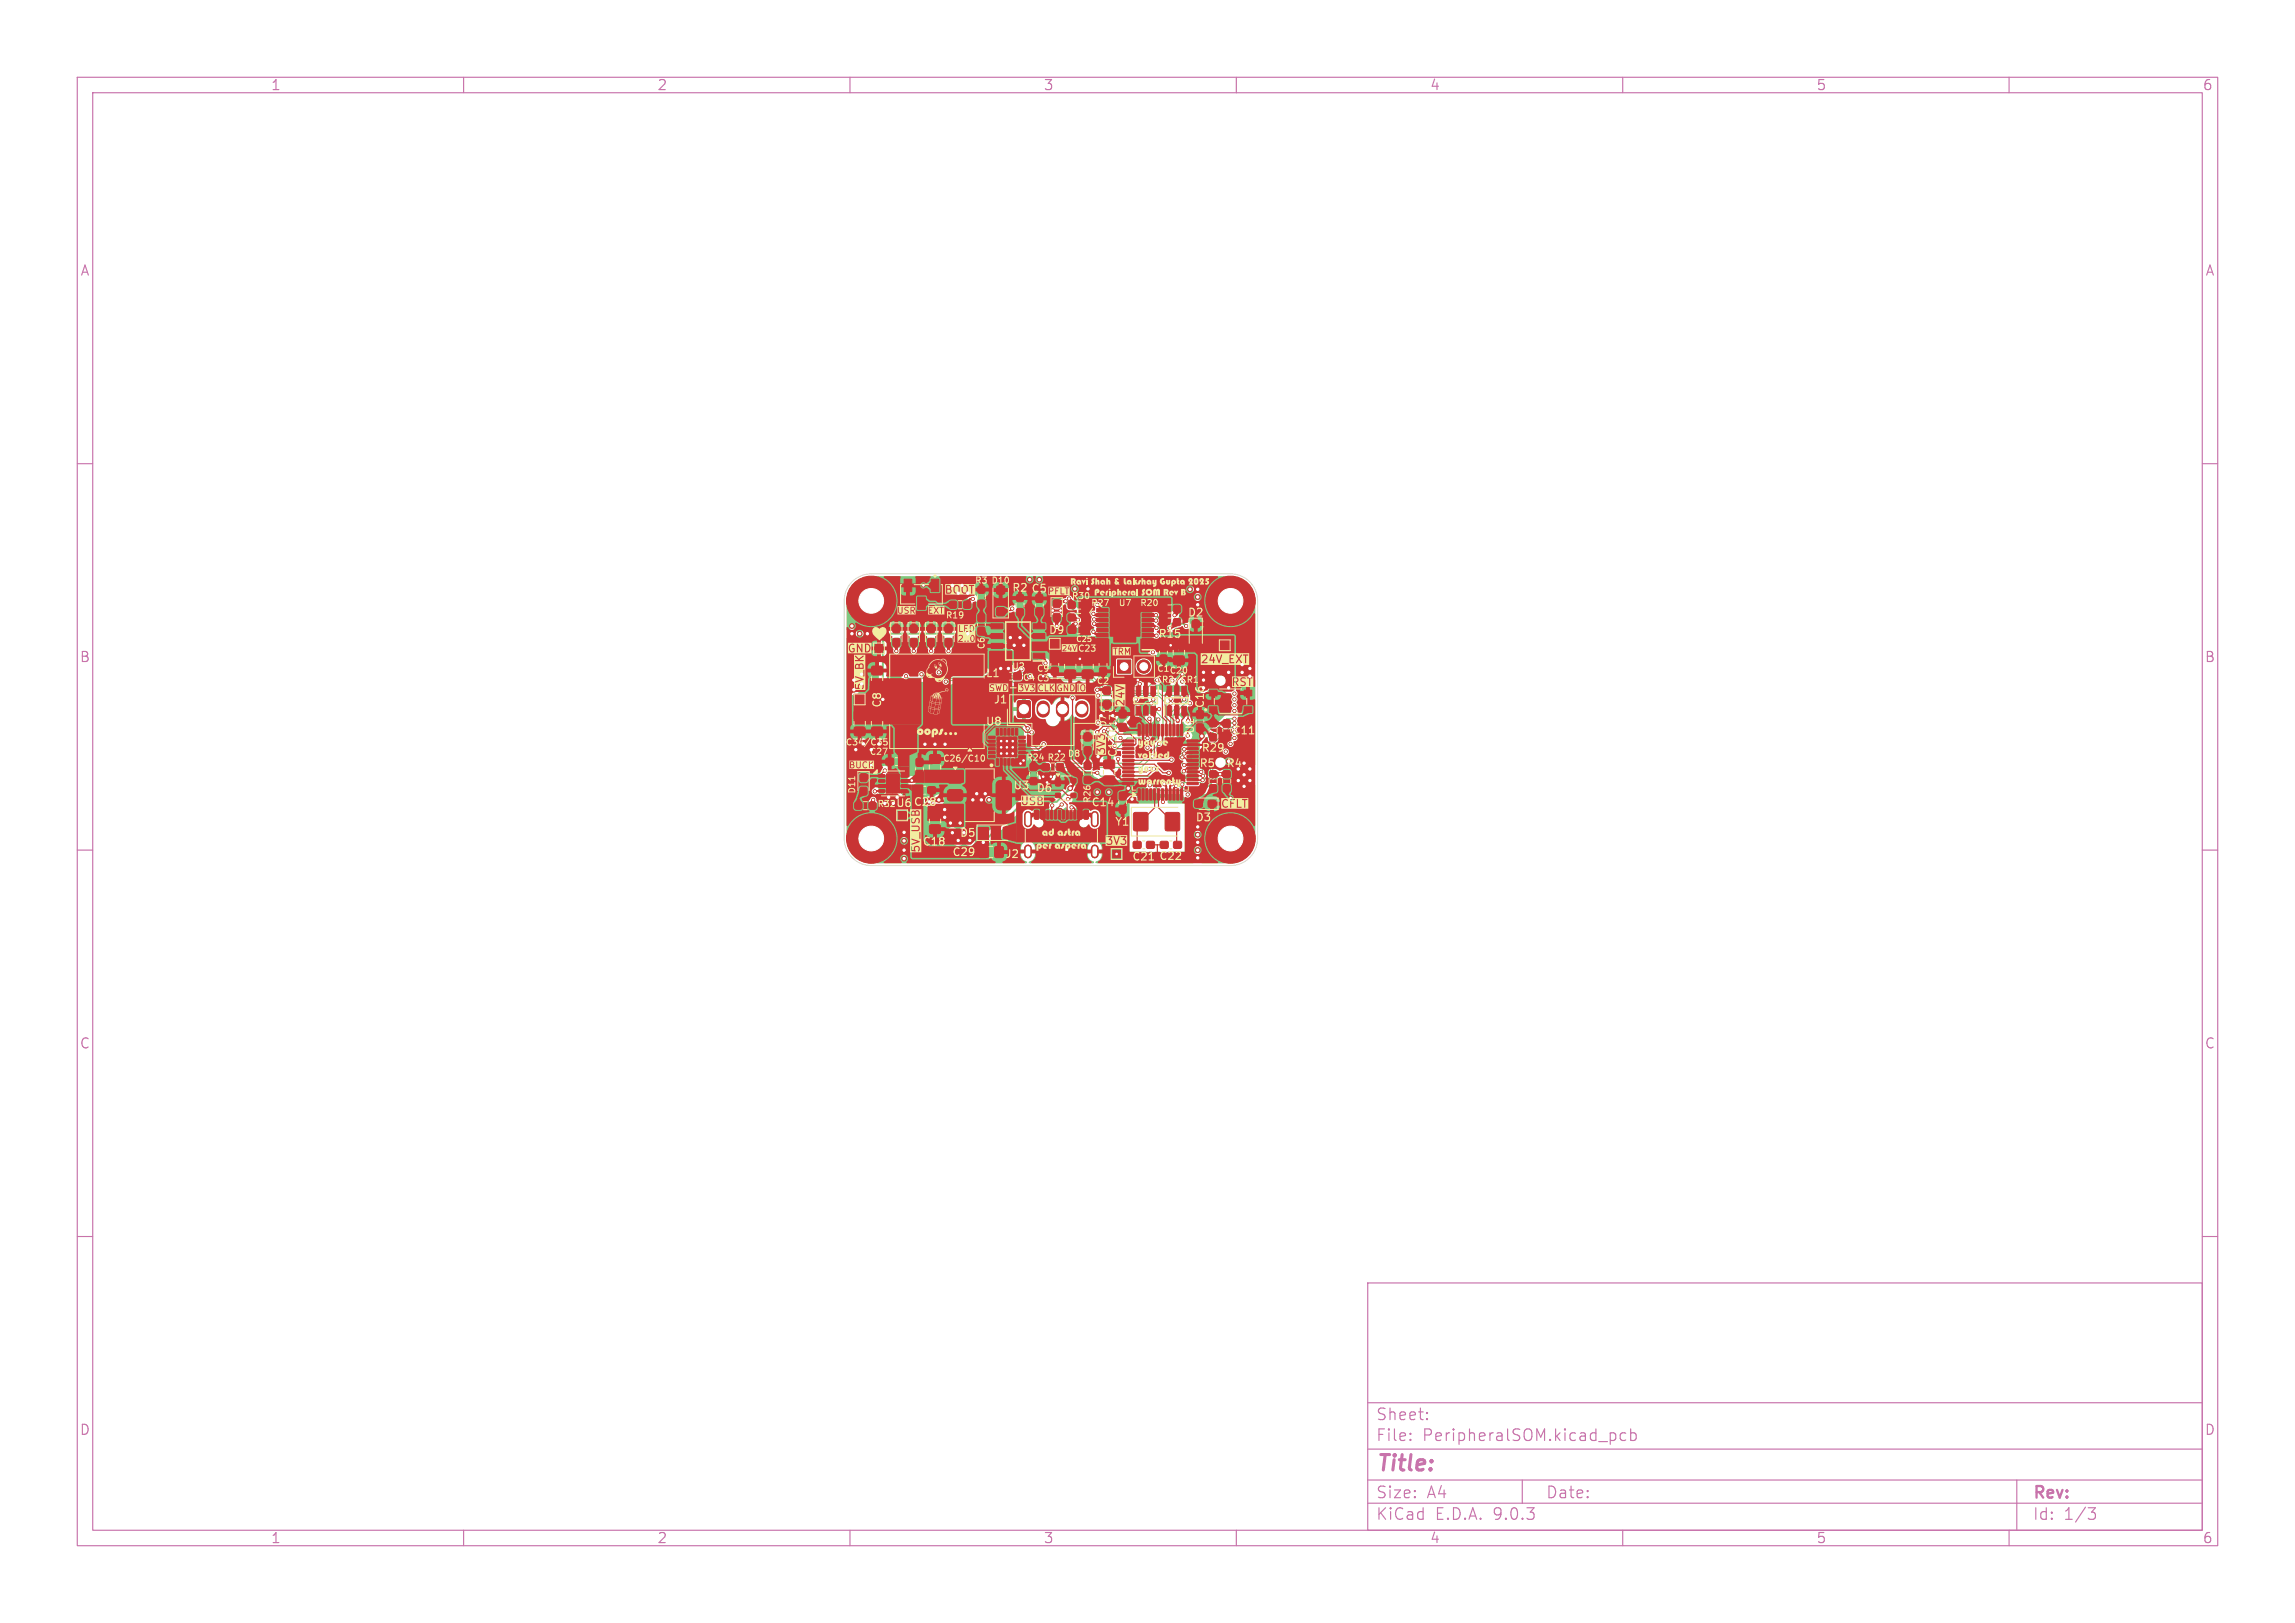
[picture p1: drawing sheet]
<svg xmlns="http://www.w3.org/2000/svg" width="297mm" height="210mm" viewBox="0 0 297 210" stroke-linecap="round" stroke-linejoin="round" font-family="sans-serif">
<defs><g id="words">
<text font-size="2.8" fill="#c872ab" x="178" y="190.9">Title:</text>
<g font-size="2.1" fill="#c872ab">
<text x="178" y="184">Sheet:</text>
<text x="178" y="186.7">File:</text>
<text x="184.1" y="186.7">PeripheralSOM.kicad_pcb</text>
<text x="178" y="196.9">KiCad</text>
<text x="178" y="194.1">Size:</text>
<text x="184.7" y="194.1">A4</text>
<text x="185.7" y="196.9">E.D.A.</text>
<text x="193.3" y="196.9">9.0.3</text>
<text x="200" y="194.1">Date:</text>
<text x="263" y="194.3">Rev:</text>
<text x="263" y="196.9">Id:</text>
<text x="267.1" y="196.9">1/3</text>
</g>
<g font-size="1.8" fill="#c872ab">
<text x="35" y="11.9">1</text>
<text x="85" y="11.9">2</text>
<text x="135" y="11.9">3</text>
<text x="185" y="11.9">4</text>
<text x="235" y="11.9">5</text>
<text x="285" y="11.9">6</text>
<text x="10.3" y="35.9">A</text>
<text x="285.4" y="35.9">A</text>
<text x="10.3" y="85.9">B</text>
<text x="285.3" y="85.9">B</text>
<text x="10.3" y="135.9">C</text>
<text x="285.3" y="135.9">C</text>
<text x="10.3" y="185.9">D</text>
<text x="285.3" y="185.9">D</text>
<text x="35" y="199.9">1</text>
<text x="85" y="199.9">2</text>
<text x="135" y="199.9">3</text>
<text x="185" y="199.9">4</text>
<text x="235" y="199.9">5</text>
<text x="285" y="199.9">6</text>
</g>
<g font-size="1.4" fill="#f2eda1">
<text x="130.9" y="76.8">R2 C5</text>
<text x="153.6" y="80">D2</text>
<text x="127.5" y="87.8">L1</text>
<text x="127.5" y="94.1">U8</text>
<text x="128.5" y="91.2">J1</text>
<text x="155.4" y="97.5">R29</text>
<text x="115.9" y="104.6">U6</text>
<text x="131.1" y="102.3">U3</text>
<text x="134.1" y="102.7">D6</text>
<text x="141.2" y="104.5">C14</text>
<text x="144.2" y="107">Y1</text>
<text x="154.6" y="106.5">D3</text>
<text x="119.3" y="109.6">C18</text>
<text x="123.2" y="111">C29</text>
<text x="130" y="111.2">J2</text>
<text x="146.4" y="111.5">C21 C22</text>
</g>
<g font-size="1.4" fill="#fff">
<text x="135.6" y="82.2">D9</text>
<text x="149.8" y="82.7">R15</text>
<text x="114.2" y="91.7" transform="rotate(-90 114.2 91.7)">C8</text>
<text x="154.7" y="95" transform="rotate(-90 154.7 95)">U1</text>
<text x="156" y="91.7" transform="rotate(-90 156 91.7)">C16</text>
<text x="159.4" y="95.2">C11</text>
<text x="144.7" y="98.1" transform="rotate(-90 144.7 98.1)">C13</text>
<text x="155.1" y="99.5">R5</text>
<text x="158.6" y="99.5">R4</text>
<text x="118.2" y="104.5">C28</text>
<text x="124.1" y="108.5">D5</text>
</g>
<g font-size="1.1" fill="#f2eda1">
<text x="126.1" y="75.7">R3 D10</text>
<text x="138.6" y="77.7">R30</text>
<text x="122.3" y="80.2">R19</text>
<text x="144.7" y="78.6">U7</text>
<text x="147.5" y="78.6">R20</text>
<text x="127.6" y="84.1" transform="rotate(-90 127.6 84.1)">C6</text>
<text x="134.1" y="87.1">C9</text>
<text x="139.4" y="84.5">C23</text>
<text x="141.9" y="88.7">C2</text>
<text x="122" y="98.6">C26/C10</text>
<text x="132.7" y="98.6">R24 R22</text>
<text x="138.1" y="98.1">D8</text>
<text x="110.8" y="102.8" transform="rotate(-90 110.8 102.8)">D11</text>
<text x="141.3" y="104" transform="rotate(-90 141.3 104)">R26</text>
</g>
<g font-size="1.1" fill="#fff">
<text x="141.1" y="78.6">R27</text>
<text x="130.9" y="86.8">U2</text>
<text x="132.3" y="88.2">C4 C3</text>
<text x="149.5" y="88.4">CR2/CR1</text>
<text x="149.7" y="87.1">C1 C20</text>
<text x="143.3" y="94.1" transform="rotate(-90 143.3 94.1)">D7</text>
<text x="144.6" y="94.9" transform="rotate(-90 144.6 94.9)">C17</text>
<text x="109.4" y="96.5">C34/C35</text>
<text x="112.5" y="97.8">C27</text>
<text x="113.5" y="104.6">R32</text>
</g>
<text font-size="1" fill="#f2eda1" x="139.2" y="83.2">C25</text>
</g></defs>
<g fill="none" stroke="#c872ab" stroke-width=".15">
<path d="M10 10h277v190h-277zM12 12h273v186h-273zM60 10v2M110 10v2M160 10v2M210 10v2M260 10v2M10 60h2M285 60h2M10 110h2M285 110h2M10 160h2"/>
<path d="M177 166h108v32h-108zM285 160h2M60 198v2M110 198v2M160 198v2M177 194.5h108M177 191.5h108M177 187.5h108M177 181.5h108M182.5 186.3h.1l-.1 .1M182.5 186.3v.1M182.5 185.5v.1"/>
<path d="M182.5 185.5h.1l-.1 .1M184.7 183.6v.1M184.7 183.6h-.1l.1 .1M184.7 182.8v.1M184.7 182.8h-.1l.1 .1M197 191.5v3M209 185.5l.1 .2v.4l-.1 .2M210 198v2M210.4 185.5l-.4-.1-.3 .3v.4l.1 .2 .2 .1 .4-.1M211 185.5l.5-.1 .2 .3v.4l-.1 .2-.1 .1-.5-.1M211 184.9v1.5M260 198v2"/>
<path d="M261 191.5v6.5M270.2 195.1h1l-.5 .6a.41 .41 0 0 1 .5 .3v.3l-.2 .2-.5 .1"/>
</g>
<g fill="#7fc87f" stroke="#7fc87f" stroke-width=".13">
<path d="M131.7 90.7h.2h1.4v.2v1.7v.2l-.2 .1-1.4-.1-.1-.2v-1.7z"/>
<path d="M144.6 85.4h1.7v1.7h-1.7z"/>
<circle cx="159.2" cy="108.5" r="1.8"/>
<circle cx="112.7" cy="108.5" r="1.8"/>
<circle cx="112.7" cy="77.8" r="1.8"/>
<circle cx="159.2" cy="77.8" r="1.8"/>
<circle cx="148" cy="86.2" r=".85"/>
<circle cx="153.2" cy="90.5" r=".2"/>
<circle cx="153.2" cy="97.5" r=".2"/>
<circle cx="154" cy="91" r=".2"/>
<circle cx="151.5" cy="90.4" r=".2"/>
<circle cx="151.5" cy="91" r=".2"/>
<circle cx="123.2" cy="107.7" r=".3"/>
<circle cx="129.6" cy="96.7" r=".2"/>
<circle cx="161.7" cy="99.5" r=".3"/>
<circle cx="117" cy="110" r=".3"/>
<circle cx="155" cy="111" r=".3"/>
<circle cx="110.2" cy="82" r=".3"/>
<circle cx="115" cy="103.1" r=".3"/>
<circle cx="112.7" cy="99" r=".2"/>
<circle cx="132" cy="82.5" r=".3"/>
<circle cx="147.2" cy="88" r=".2"/>
<circle cx="144" cy="92.6" r=".3"/>
<circle cx="160.7" cy="86" r=".3"/>
<circle cx="161.8" cy="101" r=".3"/>
<circle cx="142.5" cy="92.6" r=".3"/>
<circle cx="127.5" cy="102.7" r=".3"/>
<circle cx="122.3" cy="96.3" r=".3"/>
<circle cx="161" cy="100.2" r=".3"/>
<circle cx="125.9" cy="103.5" r=".3"/>
<circle cx="161" cy="101.7" r=".3"/>
<circle cx="126.4" cy="102.7" r=".3"/>
<circle cx="121" cy="96.3" r=".3"/>
<circle cx="142.1" cy="97.9" r=".3"/>
<circle cx="130.3" cy="96.7" r=".2"/>
<circle cx="155" cy="76.3" r=".3"/>
<circle cx="136" cy="100.5" r=".2"/>
<circle cx="110.5" cy="89.3" r=".3"/>
<circle cx="146.5" cy="103.4" r=".3"/>
<circle cx="124" cy="76.7" r=".3"/>
<circle cx="130.3" cy="95.9" r=".2"/>
<circle cx="131.1" cy="97.5" r=".2"/>
<circle cx="116.1" cy="103.1" r=".3"/>
<circle cx="127" cy="103.5" r=".3"/>
<circle cx="155" cy="107" r=".3"/>
<circle cx="137.1" cy="97.2" r=".2"/>
<circle cx="110.8" cy="97" r=".3"/>
<circle cx="117" cy="107.7" r=".3"/>
<circle cx="137.3" cy="79" r=".2"/>
<circle cx="135.5" cy="101.3" r=".2"/>
<circle cx="124" cy="108.8" r=".3"/>
<circle cx="119.7" cy="96.3" r=".3"/>
<circle cx="111.5" cy="88.5" r=".3"/>
<circle cx="130.8" cy="82.5" r=".3"/>
<circle cx="160.2" cy="101" r=".3"/>
<circle cx="161" cy="98.8" r=".3"/>
<circle cx="138.1" cy="109.9" r=".2"/>
<circle cx="136.3" cy="79" r=".2"/>
<circle cx="129.6" cy="97.5" r=".2"/>
<circle cx="112.2" cy="82" r=".3"/>
<circle cx="140.8" cy="76.2" r=".3"/>
<circle cx="125.2" cy="76.7" r=".3"/>
<circle cx="125.5" cy="108.8" r=".3"/>
<circle cx="132.5" cy="83.5" r=".3"/>
<circle cx="131.1" cy="96.7" r=".2"/>
<circle cx="131.1" cy="95.9" r=".2"/>
<circle cx="161.8" cy="86.5" r=".3"/>
<circle cx="130.3" cy="97.5" r=".2"/>
<circle cx="124.5" cy="75.7" r=".3"/>
<circle cx="115.6" cy="104" r=".3"/>
<circle cx="123.2" cy="75.7" r=".3"/>
<circle cx="152.4" cy="93.2" r=".2"/>
<circle cx="135" cy="100.5" r=".2"/>
<circle cx="160.7" cy="87" r=".3"/>
<circle cx="155" cy="109" r=".3"/>
<circle cx="155" cy="78.3" r=".3"/>
<circle cx="131.2" cy="83.5" r=".3"/>
<circle cx="129.6" cy="95.9" r=".2"/>
<circle cx="161.8" cy="87.5" r=".3"/>
<circle cx="110.5" cy="88" r=".3"/>
<circle cx="111.5" cy="87.3" r=".3"/>
<circle cx="121.5" cy="103.5" r=".3"/>
<circle cx="132.1" cy="98.8" r=".2"/>
<circle cx="155" cy="108" r=".3"/>
<circle cx="122.2" cy="105.7" r=".3"/>
<circle cx="155" cy="77.3" r=".3"/>
<circle cx="134.5" cy="75" r=".3"/>
<circle cx="117" cy="108.8" r=".3"/>
<circle cx="155" cy="110" r=".3"/>
<circle cx="146" cy="102" r=".3"/>
<circle cx="119.5" cy="75.8" r=".2"/>
<circle cx="144.5" cy="110.5" r=".2"/>
<circle cx="111.2" cy="82" r=".3"/>
<circle cx="142" cy="102.5" r=".3"/>
<circle cx="159.2" cy="103.3" r=".2"/>
<circle cx="132.5" cy="98.4" r=".2"/>
<circle cx="155.5" cy="95.3" r=".3"/>
<circle cx="149.9" cy="93.1" r=".2"/>
<circle cx="110.2" cy="81" r=".3"/>
<circle cx="154" cy="76.3" r=".3"/>
<circle cx="124.2" cy="106.5" r=".3"/>
<circle cx="128" cy="103.5" r=".3"/>
<circle cx="139.1" cy="76.2" r=".3"/>
<circle cx="122.2" cy="104.7" r=".3"/>
<circle cx="143.5" cy="102.5" r=".3"/>
<circle cx="123" cy="106.5" r=".3"/>
<circle cx="133.2" cy="75" r=".3"/>
<circle cx="149" cy="91" r=".2"/>
<circle cx="117" cy="111.1" r=".3"/>
<circle cx="147.5" cy="88.5" r=".2"/>
<circle cx="147" cy="90.5" r=".2"/>
<circle cx="159.8" cy="89.7" r=".2"/>
<circle cx="150" cy="91.7" r=".2"/>
<circle cx="159.8" cy="90.5" r=".2"/>
<circle cx="159.7" cy="91.2" r=".2"/>
<circle cx="153.2" cy="99" r=".2"/>
<circle cx="149.2" cy="90.5" r=".2"/>
<circle cx="159.8" cy="92" r=".2"/>
<circle cx="148.8" cy="93" r=".2"/>
<circle cx="137.4" cy="104.1" r=".2"/>
<circle cx="138.2" cy="103.4" r=".2"/>
<circle cx="127.2" cy="109" r=".3"/>
<circle cx="138.5" cy="102" r=".3"/>
<circle cx="159.2" cy="96.3" r=".2"/>
<circle cx="151.6" cy="98.3" r=".2"/>
<circle cx="155.4" cy="99.9" r=".2"/>
<circle cx="159.8" cy="93" r=".2"/>
<circle cx="149.2" cy="84.4" r=".2"/>
<circle cx="152.2" cy="101.7" r=".2"/>
<circle cx="155.8" cy="89" r=".3"/>
<circle cx="159" cy="87" r=".3"/>
<circle cx="157" cy="87" r=".3"/>
<circle cx="155.8" cy="88" r=".3"/>
<circle cx="159" cy="89" r=".3"/>
<circle cx="155.8" cy="87" r=".3"/>
<circle cx="151.5" cy="83.5" r=".2"/>
<circle cx="159.8" cy="93.6" r=".2"/>
<circle cx="155.7" cy="100.4" r=".2"/>
<circle cx="150.7" cy="101.5" r=".2"/>
<circle cx="151.7" cy="101.5" r=".2"/>
<circle cx="153" cy="101.5" r=".2"/>
<circle cx="158.6" cy="97.3" r=".2"/>
<circle cx="151.2" cy="100" r=".2"/>
<circle cx="155.6" cy="101" r=".2"/>
<circle cx="137.9" cy="77.8" r=".2"/>
<circle cx="141.5" cy="81.8" r=".2"/>
<circle cx="139.7" cy="85.3" r=".2"/>
<circle cx="157.9" cy="100.2" r=".2"/>
<circle cx="148.8" cy="101.6" r=".2"/>
<circle cx="119.2" cy="87.3" r=".2"/>
<circle cx="142" cy="94.7" r=".2"/>
<circle cx="118.2" cy="84.3" r=".2"/>
<circle cx="113" cy="103.5" r=".2"/>
<circle cx="118" cy="101" r=".2"/>
<circle cx="116" cy="84.2" r=".2"/>
<circle cx="117.3" cy="87.5" r=".2"/>
<circle cx="153.2" cy="96.9" r=".2"/>
<circle cx="149.7" cy="82.2" r=".2"/>
<circle cx="149.7" cy="81.2" r=".2"/>
<circle cx="151.4" cy="81.2" r=".2"/>
<circle cx="136.2" cy="104.2" r=".2"/>
<circle cx="138.7" cy="104.5" r=".2"/>
<circle cx="120.5" cy="84.3" r=".2"/>
<circle cx="121.5" cy="87" r=".2"/>
<circle cx="122.7" cy="84.3" r=".2"/>
<circle cx="138.8" cy="90.3" r=".2"/>
<circle cx="122.4" cy="88.2" r=".2"/>
<circle cx="153.2" cy="99.8" r=".2"/>
<circle cx="142" cy="100" r=".2"/>
<circle cx="142.1" cy="93.5" r=".2"/>
<circle cx="125.9" cy="77.5" r=".2"/>
<circle cx="149.6" cy="80.3" r=".2"/>
<circle cx="152" cy="79.6" r=".2"/>
<circle cx="149.6" cy="79.6" r=".2"/>
<circle cx="153.5" cy="81" r=".2"/>
<circle cx="142" cy="89.3" r=".2"/>
<circle cx="139.5" cy="80.2" r=".2"/>
<circle cx="141.6" cy="80.1" r=".2"/>
<circle cx="150.5" cy="103.8" r=".2"/>
<circle cx="153.7" cy="102.8" r=".2"/>
<circle cx="141.5" cy="79.4" r=".2"/>
<circle cx="138.4" cy="77.4" r=".2"/>
<circle cx="131" cy="78.7" r=".2"/>
<circle cx="153" cy="98" r=".2"/>
<circle cx="142.1" cy="90" r=".2"/>
<circle cx="142.9" cy="94.6" r=".2"/>
<circle cx="149.1" cy="97.9" r=".2"/>
<circle cx="133" cy="94.3" r=".2"/>
<circle cx="133.5" cy="94.7" r=".2"/>
<circle cx="150" cy="96.3" r=".2"/>
<circle cx="148.8" cy="99.5" r=".2"/>
<circle cx="148.5" cy="95.5" r=".2"/>
<circle cx="143.4" cy="94.4" r=".2"/>
<circle cx="149.3" cy="99.5" r=".2"/>
<circle cx="148.5" cy="96.7" r=".2"/>
<circle cx="125.2" cy="82" r=".3"/>
<circle cx="130.5" cy="86.5" r=".3"/>
<circle cx="129.5" cy="86.5" r=".3"/>
<circle cx="135.3" cy="85.8" r=".2"/>
<circle cx="139.2" cy="80.7" r=".2"/>
<circle cx="141.6" cy="80.7" r=".2"/>
<circle cx="135.1" cy="96.3" r=".2"/>
<circle cx="113.2" cy="102.4" r=".2"/>
<circle cx="114.5" cy="99.7" r=".2"/>
</g>
<path d="M135 91.5v.5M137.5 91.5v.5M140 91.5v.5" fill="none" stroke="#7fc87f" stroke-width="1.7"/>
<path d="M133 105.4v1.1M133 109.8v.8M141.7 105.4v1.1M141.7 109.8v.8" fill="none" stroke="#7fc87f" stroke-width="1"/>
<g fill="none" stroke="#7fc87f" stroke-width=".15">
<path d="M117.2 87.5l.3 .3h13.5l.2 .2h10.2l1.7 1.7h6.9l.3 .3h3.1l.3 .3v.4l-1.9 1.9v3.7l.7 .6h.7M119.3 87.3l.1 .1h13.8M121.5 87l.1 .1h13.6M122.4 88.2h.4l.1-.1h8l.2 .2h6.9l.8 .8v1.2M133 94.3v1.4l3.7 3.6h11l1.4-1.4M133.5 94.8l.5 .5v.7l2.7 2.8h10.8l2.5-2.5M135.8 87.7h5.8l1.6 1.7h4.9l1.4-1.4M142.1 90h7.8l1.1 1.1v5.2l1.7 1.7h.3M143.4 94.4v2M147 90.5v2l-2.7 2.8M148.5 95.5h-2.6l-1.5 1.5M149.3 90.5v.1l.2 .3v1.1l1 1v3.3l2.7 2.7"/>
<path d="M153.2 99.8l-.6 .6h-10.2l-.4-.4M153.2 90.5l-1.7 1.8v4.1l1.1 1.1h.6M159.1 94.1l-2.7 2.8v3.4l-.7 .7h-.1M159.3 95.5l-2.3 2.3v2.9l-1.3 1.2h-2.9l-.2-.2M159.3 94.8l-2.6 2.5v3.3l-.8 .8h-.4l-.2-.1h-2.1l-.2 .2M159.7 93h-1l-3 3v3.5M159.7 93.6h-.8l-2.8 2.8v3.6l-.4 .4M152.2 101.7h.4M152.6 101.7h.1M157.9 100.2l-2.1 2.1h-5.8l-.7-.7h-.5"/>
</g>
<path d="M137.9 77.8v.1l3.6 3.6v.3M149.6 79.6l1.1 1.1h2.5l.3 .3M125.2 82h-10l-.9 1v7.5M136 103.7v.1M136.4 103.7v.1M138.5 102l-1.8 1.8h-4.2l-5.3 5.2" fill="none" stroke="#7fc87f" stroke-width=".25"/>
<g fill="#7fc87f">
<path d="M147.6 90.5h1l.4 .6 .1 1.1a.15 .15 0 0 1 0 .2 .15 .15 0 0 1-.2 0 .61 .61 0 0 0-.7 .6 .61 .61 0 0 0 .7 .6 .61 .61 0 0 0 .4-.8l.2-.1 .5 .5v2.3l-.4 .3-.5 .6-.4-.3a.63 .63 0 0 0 .4-.8 .63 .63 0 0 0-.8-.4l-.3 .1h-2.2l-.3 .1-.2-.2 2.1-2.2 .1-1.7z"/>
<path d="M110.6 75.4a3.2 3.2 0 0 1 2.2-.8h46.4a3.2 3.2 0 0 1 3.2 3.2v8.1l-.1 .1a1.09 1.09 0 0 0-.9-.2 .72 .72 0 0 0-1-.4 .72 .72 0 0 0-.2 1.1 .74 .74 0 0 0 0 .9 .74 .74 0 0 0 .8 .3 .82 .82 0 0 0 1.4 .3v.1v10.8l-.1 .1-.5-.2a.77 .77 0 0 0-.8-.8 .77 .77 0 0 0-.8 .8 .72 .72 0 0 0-.6 .6 .72 .72 0 0 0 .4 .8v.1a.76 .76 0 0 0-.4 .9 .76 .76 0 0 0 .7 .6 .74 .74 0 0 0 .8 .6 .74 .74 0 0 0 .7-.7l.5-.2 .1 .1v6.9a3.2 3.2 0 0 1-3.2 3.2h-3.6l-.1-.1a.72 .72 0 0 0 0-1.1 .72 .72 0 0 0-1 0 .72 .72 0 0 0 0 1l-.1 .2h-12.5l-.1-.1v-.1a.89 .89 0 0 0 .8-.8l-.1-1.2a.9 .9 0 0 0-.9-.6 .9 .9 0 0 0-.8 .8v1.1a1.35 1.35 0 0 0 .8 .7l-.1 .2h-8.3l-.1-.1 .1-.1a.89 .89 0 0 0 .7-.8v-.8h3.6a.61 .61 0 0 0 .8 .6 .61 .61 0 0 0 .2-1 .61 .61 0 0 0-1 .2v.2h-3.6a.91 .91 0 0 0-.8-1 .91 .91 0 0 0-1 .8l.1 1.1a1.35 1.35 0 0 0 .7 .7l-.1 .2h-20.1a3.2 3.2 0 0 1-3.1-3.3h.9v.2a2.2 2.2 0 0 0 1.5 2 2.2 2.2 0 0 0 2.3-.5h2v.1a.7 .7 0 0 0 1.2 .3 .7 .7 0 0 0-.3-1.2 .7 .7 0 0 0-.9 .8h-2l.1-.1a2.2 2.2 0 0 0 .4-2.2h1.5v.1a.7 .7 0 0 0 .7 .5 .7 .7 0 0 0 .7-.6h4.8l.1 .2a1.11 1.11 0 0 0 .7 .5 .73 .73 0 0 0 .5 .9 .73 .73 0 0 0 .9-.4h.1a.72 .72 0 0 0 .6 .5 .72 .72 0 0 0 .7-.4h.4l.1 .1a.71 .71 0 0 0 .6 .5 .71 .71 0 0 0 .7-.4l.2-.4 3.9-3.9 .2 .1v1.7a.96 .96 0 0 0 .8 .6 .96 .96 0 0 0 1-.5 .62 .62 0 0 0 .7 .1 .62 .62 0 0 0 .3-.6h4.7v.2a.6 .6 0 0 0 .4 .5 .6 .6 0 0 0 .6-.2h.1a.9 .9 0 0 0 1 .5 .9 .9 0 0 0 .8-.8l-.1-1.4a.9 .9 0 0 0-.9-.7 .9 .9 0 0 0-.8 .9v.5l-.2 .1a.6 .6 0 0 0-.9 .4h-4.7v-.1a.62 .62 0 0 0-.9-.3l-.2-.1v-.5a.99 .99 0 0 0-1.3-.8v-.2l.2-.1h2.7l.1 .1a.62 .62 0 0 0 .6 .4 .62 .62 0 0 0 .6-.4l.1 .1a.64 .64 0 0 0 1 0h.2a.61 .61 0 0 0 .6 .6 .61 .61 0 0 0 .6-.6 .61 .61 0 0 0-.6-.7l.1-.3h7l.1 .2 .3 .4v6.1h7.1v-1.1h1a.7 .7 0 0 0 1.1 .5 .7 .7 0 0 0-.1-1.2h1.7v.2a2.21 2.21 0 0 0 3.4 1.8 2.21 2.21 0 0 0 0-3.8 2.21 2.21 0 0 0-3.4 1.8l-1.8-.1a.7 .7 0 0 0-.9 .8h-1v-2h1v.1a.7 .7 0 0 0 1.2 .3 .7 .7 0 0 0-.3-1.2 .7 .7 0 0 0-.9 .8h-1v-3.1h-2.1a.66 .66 0 0 0-.4-.7 .66 .66 0 0 0-.8 .1l-.1 .5-.1 .1h-2.6l-.1-.2a.71 .71 0 0 0-.4-1.1 .71 .71 0 0 0-.9 .8h-7v-.3l-.3-.4 .3-.2a.7 .7 0 0 0 .2-1.1 .7 .7 0 0 0-1.1 .2l-.3 .4-1.1 1.1h-4.1l-.2 .1-4.8 4.8-.7 .5-.2 .5h-.4a.78 .78 0 0 0-.7-1.1 .73 .73 0 0 0-.4-.9 .73 .73 0 0 0-.9 .4h-.2a.72 .72 0 0 0-.8-.4 .72 .72 0 0 0-.6 .7h-4.8a.7 .7 0 0 0-.7-.8 .7 .7 0 0 0-.7 .8h-1.5v-.1a2.2 2.2 0 0 0-2.4-1.4 2.2 2.2 0 0 0-1.9 2.1h-.9v-5h2.8v.2a.6 .6 0 0 0 .9 .4h.5v.2a.8 .8 0 0 0 1.3 .2 .75 .75 0 0 0 .8 .2 .75 .75 0 0 0 .4-.8h3.2l.1 .2a.7 .7 0 0 0 .6 .5 .7 .7 0 0 0 .7-.4l.1-.1 .2 .1a.7 .7 0 0 0 1-.5h3v.1a.8 .8 0 0 0 1.3 .3 .73 .73 0 0 0 .8 .1 .73 .73 0 0 0 .4-.7 .72 .72 0 0 0 .4-1.1 .72 .72 0 0 0-1.1-.1 .76 .76 0 0 0-.9-.1 .76 .76 0 0 0-.4 .7 .79 .79 0 0 0-.5 .8h-3v-.2a.7 .7 0 0 0-.6-.6 .7 .7 0 0 0-.7 .4h-.1l-.2-.1a.7 .7 0 0 0-1.1 .7h-3.1a.71 .71 0 0 0 .3-1.1 .71 .71 0 0 0-1.1 0 .76 .76 0 0 0-.9-.2 .76 .76 0 0 0-.4 .8 .79 .79 0 0 0-.5 .7h-.5h.1a.7 .7 0 0 0 0-1 .62 .62 0 0 0 .4-.9 .62 .62 0 0 0-.9-.2 .62 .62 0 0 0-.1 .9l-.4 .6h-2.8v-2.5h7.8a.6 .6 0 0 0 .5 .7 .6 .6 0 0 0 .7-.5 .6 .6 0 0 0-.4-.7h16.2v.2a.67 .67 0 0 0 .5 .5 .63 .63 0 0 0 .6 .8 .63 .63 0 0 0 .6-.8 .62 .62 0 0 0 .4-.9 .62 .62 0 0 0-1-.1 .67 .67 0 0 0-1.1 .3h-16.5l-.4 .2-.1 .3h-7.8v-1.3h4.3v.2a.61 .61 0 0 0 .9 .4 .61 .61 0 0 0 0-1 .61 .61 0 0 0-.9 .4h-4.3v-.7h2.5v.2a.61 .61 0 0 0 1 .4 .61 .61 0 0 0 0-1 .61 .61 0 0 0-1 .4h-2.5v-1.8h.4l.1 .1a.75 .75 0 0 0 .8 .5 .75 .75 0 0 0 .6-.8h.3a.32 .32 0 0 1 .3 .4 .75 .75 0 0 0 .9 .4 .75 .75 0 0 0 .5-.8h.1a.69 .69 0 0 0 .8-.5h4.6v.1a.77 .77 0 0 0 1.4 .2 .83 .83 0 0 0 1.3 0 .72 .72 0 0 0 1 .2 .72 .72 0 0 0 .1-1.1h6.2l.1 .5a.88 .88 0 0 0 0 .9 .64 .64 0 0 0 .1 .8 .64 .64 0 0 0 .8 0l.2 .1a1.04 1.04 0 0 1 .9 0 .69 .69 0 0 0 .5-1.1 .83 .83 0 0 0 0-.8 .62 .62 0 0 0-.1-.8 .62 .62 0 0 0-.8 0 .82 .82 0 0 0-.8 0 .6 .6 0 0 0-.9 .4h-6.3a.83 .83 0 0 0-1.1 .1h-.1a.79 .79 0 0 0-1.2 0 .73 .73 0 0 0-.8-.3 .73 .73 0 0 0-.5 .8l-4.5-.1a.71 .71 0 0 0-.7-.8 .71 .71 0 0 0-.8 .8h-.2a.34 .34 0 0 1-.4-.4 .75 .75 0 0 0-.9-.3 .75 .75 0 0 0-.5 .7 .74 .74 0 0 0-1 .8h-.4v-6.5h3.9l.1 .1a.7 .7 0 0 0 .9 .5 .7 .7 0 0 0 .4-.9l-.1-.5v-2.4h1.8a.93 .93 0 0 0 1 .8h4.2a.65 .65 0 0 0 .8 .6l.6-.3h7.4l.5 .3h6.7l.5 .5v.5l-.1 .5-.1 .1a1.32 1.32 0 0 0-1.8 .6h-.1a1.34 1.34 0 0 0-2.3-.2 1 1 0 0 0-.8-.6h-.3v1h-.6v-1a.83 .83 0 0 0-1 .7v.6h.8v.5h-.8a1.32 1.32 0 0 0 .1 1.1l.4 .2 .5 .1v-1.1h.6v1.1a.88 .88 0 0 0 1.1-.6h.1a1.54 1.54 0 0 0 1.4 .5 .92 .92 0 0 0 .9 .7 .92 .92 0 0 0 .9-.7 1.43 1.43 0 0 0 1.5-.8h.1a1.27 1.27 0 0 0 1.4 .7 1.27 1.27 0 0 0 1.1-1.1l-.1-.9a1.36 1.36 0 0 0-1.7-.9l-.2-.5v-.8l-.3-.4 .1-.1h2l.4 .3a1.09 1.09 0 0 0 0 1 .66 .66 0 0 0 .3 .7 .66 .66 0 0 0 .8 0h3.7l.1 .1 .1 .4v1.3l-2.3 2.3h-.2a.64 .64 0 0 0-.3-.7 .64 .64 0 0 0-.8 .1h-.3l.1-.4a.42 .42 0 0 1 .3-.6l.2-.2 .2 .1a.71 .71 0 0 0 1.1 .2 .71 .71 0 0 0-.1-1.1 .71 .71 0 0 0-1.1 .4h-.1a.72 .72 0 0 0-1-.5 .72 .72 0 0 0-.4 1 .72 .72 0 0 0 0 1.2 .64 .64 0 0 0-.3 1 .64 .64 0 0 0 1 0l.4 .2v1.1l.1 .3 .7 .7 .7 .1v.1l-.4 .7h-1.1l-.1-.2a.7 .7 0 0 0-.7-.9 .7 .7 0 0 0-.7 .9l-.1 .2h-4.3l-1.2-1.2h.7a.61 .61 0 0 0 .8 .7 .61 .61 0 0 0 .2-1 .61 .61 0 0 0-1 .2v.1h-.7l-.3-.3a.67 .67 0 0 0 0-.9 .67 .67 0 0 0-.9 0l-.2-.8-.4-.7-.3-.2a.66 .66 0 0 0-1-.5 .66 .66 0 0 0-.2 1v1l.1 .2 3.8 3.8 .2 .1h4.7l.1 .1a.61 .61 0 0 0 .4 .7l.6 .3h5.9l.2 .1-.1 .1a.63 .63 0 0 0-.1 .8 .63 .63 0 0 0 .8 .2l.6 .6 .2 .1h3.1l.1 .1a.61 .61 0 0 0 .6 .5 .61 .61 0 0 0 .6-.5l.1-.1 1.6-.1 1.9-1.8 .3-.2a.62 .62 0 0 0 .3-.7 .62 .62 0 0 0-.5-.4v-.2a.72 .72 0 0 0 .6-.8 .72 .72 0 0 0-.9-.6l-.1-.1v-.1l.3-.3h.2a.6 .6 0 0 0 .8 .3 .6 .6 0 0 0 .3-.8l.1-.1a.64 .64 0 0 0 .6-.8 .71 .71 0 0 0 .4-1l.1-.3-.1-1.6a.67 .67 0 0 0-.1-.7v-.1a.73 .73 0 0 0 .1-.8l.1-.3a1.04 1.04 0 0 1 0-.9l-.1-.3a.67 .67 0 0 0-.6-1 .79 .79 0 0 0-1-.8l-.1-.6 .1-.1a.72 .72 0 0 0 1-.6 .72 .72 0 0 0-.9-.7 .72 .72 0 0 0-.4 1l-.1 .1h-.6a.75 .75 0 0 0-.3-1 .75 .75 0 0 0-1 .2 .75 .75 0 0 0-.9-.2 .75 .75 0 0 0-.4 .8 .56 .56 0 0 1-.1 .7l.1 .3a.56 .56 0 0 1-.1 .7 .71 .71 0 0 0 1 .8 .71 .71 0 0 0 .3-1.2l.2-.4-.1-.5 .8 .1 .1 .1a.76 .76 0 0 0 .2 .8 .76 .76 0 0 0 .8 .2v.1a.73 .73 0 0 0 .8 .8l.2 .4-.2 .3 .2 .5-.2 .3 .2 .4-.2 .3 .1 .6-.7 .1-3.2 3.2-.1 3.5a.66 .66 0 0 0-.1 1.1v.3l-.1 .1h-1.9v-.2l.3-.2a.68 .68 0 0 0 .3-1 .79 .79 0 0 0-.2-1l.1-.4a.62 .62 0 0 0 .2-.7 .63 .63 0 0 0-.1-.8 .63 .63 0 0 0-.7-.1l-.3 .1-.4-.4v-1h.8a.61 .61 0 0 0 .8 .7 .61 .61 0 0 0 .2-1 .61 .61 0 0 0-1 .2v.1h-.8v-1.2a1.1 1.1 0 0 0 .8-.5 .66 .66 0 0 0 .6 .4 .66 .66 0 0 0 .7-.5 .62 .62 0 0 0-.5-.6 .62 .62 0 0 0-.8 .4h-.1l-.4-.5v-.1l1-1a.62 .62 0 0 0 .9-.2 .62 .62 0 0 0-.3-.9l-.1-.4-.4-.4-.3-.1h-2.8l-.5-.3h-.9v-.2l.5-.4a.6 .6 0 0 0 .7-.6h.7v.2a.66 .66 0 0 0 .6 .5 .66 .66 0 0 0 .6-.3l.2 .2a.61 .61 0 0 0 .9 0 .61 .61 0 0 0-.1-.9 .61 .61 0 0 0-.8 .2h-.2a.61 .61 0 0 0-.7-.4 .61 .61 0 0 0-.5 .5h-.7v-.1a.67 .67 0 0 0-1.1-.3l-1 .9h-.2l-.2-.5-.1-.5a1.29 1.29 0 0 0 1.5-1 1.29 1.29 0 0 0-1.2-1.5 1.69 1.69 0 0 0-1.3 .6l-.1-.1a.44 .44 0 0 0-.3-.5h-1.8l-.3 .2-.1 .2v1.8l.2 .2 .2 .1h1.8l.3-.2v-.4h.2l.3 .4a.71 .71 0 0 0-.5 .6 .71 .71 0 0 0 .2 .7l.1 .2-.2 .1h-3.3l-1.8-1.6-5.6-.1-.8-.6 .1-.2a.61 .61 0 0 0 .4-.9 .61 .61 0 0 0-1-.1 .61 .61 0 0 0 .3 1v.1l-.1 .1h-2.1l-.1-.1a.64 .64 0 0 0-.7-.5 .64 .64 0 0 0-.6 .6 .36 .36 0 0 1-.4-.4 .74 .74 0 0 0-1.1-.2 .79 .79 0 0 0-.8-.1 .79 .79 0 0 0-.5 .7h-6.7a.69 .69 0 0 0-1.1 .3l-1.1 .1a.65 .65 0 0 0-.6-.3 .65 .65 0 0 0-.6 .5l-.1 .1-.7-.1a.61 .61 0 0 0-.6-.3 .61 .61 0 0 0-.6 .5h-1.8v-2.2h24.3v.1a.61 .61 0 0 0 1 .5 .61 .61 0 0 0 0-1.1 .61 .61 0 0 0-1 .5h-24.3v-1h.6v.1a.61 .61 0 0 0 .7 .6 .61 .61 0 0 0 .5-.7h1v.1a.61 .61 0 0 0 .7 .6 .61 .61 0 0 0 .6-.7h1v.1a.61 .61 0 0 0 .7 .6 .61 .61 0 0 0 .5-.7h1v.1a.61 .61 0 0 0 .7 .6 .61 .61 0 0 0 .6-.6h25.2v.2a.61 .61 0 0 0 .9 .4 .61 .61 0 0 0 0-1 .61 .61 0 0 0-.9 .4h-25.2v-.1a.61 .61 0 0 0-.7-.6 .61 .61 0 0 0-.6 .6h-1v-.2a.61 .61 0 0 0-.7-.4 .61 .61 0 0 0-.5 .6h-1l-.1-.2a.61 .61 0 0 0-.6-.4 .61 .61 0 0 0-.6 .6h-1v-.2a.61 .61 0 0 0-.7-.4 .61 .61 0 0 0-.5 .6h-.6v-.9l.7-.8h9.1l.6 .2 .5-.1h4.3l.2 .3 .4 .3a.75 .75 0 0 0 .3 .9 .75 .75 0 0 0 .9-.2 .75 .75 0 0 0 .9 .3 .75 .75 0 0 0 .5-.8h17.7v.2a.61 .61 0 0 0 .9 .4 .61 .61 0 0 0 0-1 .61 .61 0 0 0-.9 .4h-17.7l-.2-.3-.3-.4a.72 .72 0 0 0-.4-.8 .72 .72 0 0 0-.9 .2 .76 .76 0 0 0-.9-.3 .76 .76 0 0 0-.5 .8l-4.3-.1a.7 .7 0 0 0 .2-.8 .7 .7 0 0 0-.9-.4l-.4 .2h-9.6l-1.2 1.2-.1 .2v6.9l-.2 .8h-3.9v-2.5h.2l.3 .6a.72 .72 0 0 0 .1 1.2 .72 .72 0 0 0 1-.7h.1a.72 .72 0 0 0 .8-.4 .72 .72 0 0 0-.2-.9 .75 .75 0 0 0 .2-.9 .75 .75 0 0 0-.8-.4 .95 .95 0 0 0-.6 .7 .74 .74 0 0 0-.9 .8h-.2v-5.5v-.1h.2a.7 .7 0 0 0 .7 .2 .7 .7 0 0 0 .5-.6h.5l.1 .1a.7 .7 0 0 0 1.1 .3 .7 .7 0 0 0-.2-1.2 .7 .7 0 0 0-1 .8h-.5v-.2a.72 .72 0 0 0-.5-.6 .72 .72 0 0 0-.8 .2l-.1-.1v-.5h26.5a.61 .61 0 0 0 .8 .7 .61 .61 0 0 0 .3-1 .61 .61 0 0 0-1 .2l-.1 .1h-26.5v-3.3h.9v.3a2.2 2.2 0 0 0 1.8 2 2.2 2.2 0 0 0 2.5-1.2h15.6v.1a.6 .6 0 0 0 .6 .6 .6 .6 0 0 0 .6-.5h4v.2a.62 .62 0 0 0 .5 .5 .62 .62 0 0 0 .6-.2 .69 .69 0 0 0 .8 .1 .69 .69 0 0 0 .4-.7h.2l.9 .9-.1 .4a.62 .62 0 0 0 0 1.1 .62 .62 0 0 0 .9-.5h.2l.9 1a.63 .63 0 0 0 .8 .6 .63 .63 0 0 0 .3-1v-.1a.7 .7 0 0 0 .2-.7v-.4l-.1-.4v-.2h6.9l.1 .5a.97 .97 0 0 0 .1 .9 .83 .83 0 0 0 .1 .9 .61 .61 0 0 0-.1 .8 .61 .61 0 0 0 .8 .1 .61 .61 0 0 0 .2-.8l.1-.1h1a.6 .6 0 0 0 .7-.5l.1-.1 .9 .1a.61 .61 0 0 0 .9 .1 .61 .61 0 0 0-.1-.9l-.5-.3h-.7a.33 .33 0 0 1 0-.5 .61 .61 0 0 0-.8-.7 .61 .61 0 0 0-.3 1l-.1 .2h-.5l-.8-1a.61 .61 0 0 0-.7-.2 .61 .61 0 0 0-.4 .5h-6.9l-.1-.6a.84 .84 0 0 0 .6-.6h11.7v.2a.7 .7 0 0 0 1.2 .3 .7 .7 0 0 0-.2-1.2h1.7v.3a2.21 2.21 0 0 0 3.4 1.7 2.21 2.21 0 0 0 0-3.7 2.21 2.21 0 0 0-3.4 1.7h-1.8a.7 .7 0 0 0-.9 .7h-11.7v-.1a.61 .61 0 0 0-.9-.5 .61 .61 0 0 0-.2 1v.1a.72 .72 0 0 0-.5 1.1v.2h-.2l-2-2.1v-.1a.62 .62 0 0 0-.1-1 .62 .62 0 0 0-1 .3 .69 .69 0 0 0-.2 1.1l-.8 .3a.61 .61 0 0 0-.6-.2 .61 .61 0 0 0-.5 .5h-4v-.1a.61 .61 0 0 0-.5-.7 .61 .61 0 0 0-.7 .6l-15.6-.1a2.19 2.19 0 0 0-1-2.8h8.7l.1 .2a1.11 1.11 0 0 0 .7 .5 .74 .74 0 0 0 .4 .9 .74 .74 0 0 0 .9-.2l.4 .2a.25 .25 0 0 1 .3 .3 .61 .61 0 0 0 1.1 .2 .61 .61 0 0 0-.4-1l-.2-.6h14.3v.1a.7 .7 0 0 0 .7 .5 .7 .7 0 0 0 .7-.6h12.8v.2a.7 .7 0 0 0 1.2 .3 .7 .7 0 0 0-.3-1.2 .7 .7 0 0 0-.9 .7h-12.8a.7 .7 0 0 0-.7-.8 .7 .7 0 0 0-.7 .8h-14.3l-.3-.2a.25 .25 0 0 1-.3-.1 .25 .25 0 0 1 0-.3 .72 .72 0 0 0-.5-.6 .72 .72 0 0 0-.8 .2 .76 .76 0 0 0-.9-.2 .76 .76 0 0 0-.5 .7h-8.8a2.2 2.2 0 0 0-3.2 1.8h-.9l.2-1.2 .4-.5z"/>
<path d="M119.3 87.2l.1-.1 .2 .4-.4-.1z"/>
<path d="M127.1 108.7l.5-.2 .2 .2-.3 .5-.3-.2z"/>
<path d="M152.9 97.4l.3-.1v.4l-.3-.1z"/>
<path d="M137.9 77.8l.2-.1 .1 .3-.2 .2-.2-.2z"/>
<path d="M138.2 101.8l.3 .2 .2 .2-.5 .3-.2-.2z"/>
<path d="M152.2 101.5l.4 .1-.3 .2-.1-.1z"/>
<path d="M153 101.3l.3-.1-.1 .4-.2-.1z"/>
<path d="M146.8 90.5h.4l-.1 .4h-.2z"/>
<path d="M152.6 98l.4-.2v.2l-.1 .2z"/>
<path d="M149.8 96.2l.3 .2-.3 .2-.1-.1z"/>
<path d="M121.6 86.8l.3 .2v.1l-.4 .1v-.2z"/>
<path d="M141.3 81.5l.2-.2 .2 .3-.2 .1h-.2z"/>
<path d="M153 99.7l.3 .3-.3 .1-.1-.1z"/>
<path d="M138.7 89.9h.2l.1 .4h-.4z"/>
<path d="M153.1 90.4l.3 .3-.4 .1-.1-.1z"/>
<path d="M148.1 95.4l.4-.1v.4l-.4-.1z"/>
<path d="M132.8 94.3h.4l-.1 .3h-.2z"/>
<path d="M122.4 88l.4 .1v.2l-.4 .1z"/>
<path d="M148.8 101.4l.4 .1v.2l-.4 .1z"/>
<path d="M157.7 100.1l.3 .2-.3 .2-.1-.1z"/>
<path d="M149.2 90.5h.2l.1 .3-.1 .1-.3-.2z"/>
<path d="M149 97.8l.2 .2-.3 .2-.1-.1z"/>
<path d="M155.6 100.8l.3-.1 .1 .1-.2 .3-.2-.2z"/>
<path d="M124.7 81.9l.5-.2v.6l-.5-.2z"/>
<path d="M152.9 98.8l.1-.1 .4 .1-.3 .3z"/>
<path d="M142.1 89.8l.4 .1v.2l-.4 .1z"/>
<path d="M159.4 93.5l.3-.1v.3l-.3-.1z"/>
<path d="M149.7 81.1h.4v.3h-.4z"/>
<path d="M117.3 87.5l.1-.1 .1 .4-.3-.1z"/>
<path d="M133.5 94.8l.2-.2 .1 .4-.1 .1-.3-.2z"/>
<path d="M142 100l.2-.1 .1 .3-.1 .1-.3-.1z"/>
<path d="M159.4 92.9l.3-.1v.4l-.3-.1z"/>
<path d="M149.6 79.6l.2-.1 .2 .3-.2 .2-.3-.2z"/>
<path d="M152.9 96.9l.3-.1v.3l-.3-.1z"/>
<path d="M151 81.1h.4v.3h-.4z"/>
<path d="M155.6 100.2l.3-.1 .1 .1-.2 .3z"/>
<path d="M143.2 94.5h.4l-.1 .3h-.2z"/>
<path d="M153.3 80.6l.3 .2-.3 .3-.2-.3z"/>
</g>
<g fill="#c83434" stroke="#c83434" stroke-width=".13">
<path d="M144 110h1v1h-1z"/>
<path d="M156.6 99.8l.2-.1 .6 .1 .1 .1-.1 .7-.2 .1-.6-.1-.1-.2z"/>
<path d="M156.6 101.6l.2-.1 .6 .1 .1 .2-.1 .6-.2 .1-.6-.1-.1-.1z"/>
<path d="M120.3 99.8l.2-.1 1.2 .1v.2v.8l-.2 .1-1.2-.1v-.2z"/>
<path d="M120.3 97.7l.2-.1 1.2 .1v.2v.8l-.2 .1-1.2-.1v-.1z"/>
<path d="M150.2 83.1l.1-.1 .7 .1v.1v.8l-.2 .1-.6-.1-.1-.2z"/>
<path d="M150.2 84.8l.1-.1 .7 .1v.2v.7l-.2 .1-.6-.1-.1-.1z"/>
<path d="M142.8 90.7l.2-.1 .7 .1v.1v.8l-.2 .1-.7-.1v-.2z"/>
<path d="M142.8 88.9h.2h.7v.2v.7l-.2 .1-.7-.1v-.1z"/>
<path d="M158 83h1v1h-1z"/>
<path d="M126.6 77.7l.2-.1 .6 .1 .1 .2-.1 .6-.2 .1-.6-.1-.1-.1z"/>
<path d="M126.6 75.9l.2-.1 .6 .1 .1 .1-.1 .7-.2 .1-.6-.1-.1-.2z"/>
<path d="M120.1 80.9h.2h.6l.1 .2-.1 .7-.2 .1-.6-.1-.1-.1z"/>
<path d="M120.1 82.7l.2-.1 .6 .1 .1 .1-.1 .8-.2 .1-.6-.1-.1-.2z"/>
<path d="M112.8 92h.2h1.2v.2v.9l-.2 .1-1.2-.1v-.2z"/>
<path d="M112.8 94.1h.2h1.2v.2v.9h-.2h-1.2v-.2z"/>
<path d="M111.3 100.2l.2-.1 .7 .1v.1v.8l-.2 .1-.7-.1v-.2z"/>
<path d="M111.3 101.9h.2h.7v.2v.7l-.2 .1-.7-.1v-.1z"/>
<path d="M128.9 98.2h.3v.8h-.3z"/>
<path d="M129.4 98.2h.3v.8h-.3z"/>
<path d="M129.9 98.2h.3v.8h-.3z"/>
<path d="M130.4 98.2h.3v.8h-.3z"/>
<path d="M130.9 98.2h.3v.8h-.3z"/>
<path d="M131.4 98.2h.3v.8h-.3z"/>
<path d="M131.8 97.8h.9v.3h-.9z"/>
<path d="M131.8 97.3h.9v.3h-.9z"/>
<path d="M131.8 96.8h.9v.3h-.9z"/>
<path d="M131.8 96.3h.9v.3h-.9z"/>
<path d="M131.8 95.8h.9v.3h-.9z"/>
<path d="M131.8 95.3h.9v.3h-.9z"/>
<path d="M131.4 94.3h.3v.8h-.3z"/>
<path d="M130.9 94.3h.3v.8h-.3z"/>
<path d="M130.4 94.3h.3v.8h-.3z"/>
<path d="M129.9 94.3h.3v.8h-.3z"/>
<path d="M129.4 94.3h.3v.8h-.3z"/>
<path d="M128.9 94.3h.3v.8h-.3z"/>
<path d="M127.9 95.3h.9v.3h-.9z"/>
<path d="M127.9 95.8h.9v.3h-.9z"/>
<path d="M127.9 96.3h.9v.3h-.9z"/>
<path d="M127.9 96.8h.9v.3h-.9z"/>
<path d="M127.9 97.3h.9v.3h-.9z"/>
<path d="M127.9 97.8h.9v.3h-.9z"/>
<path d="M129 95.4h2.6v2.5h-2.6z"/>
<path d="M140.1 84.7l.2-.1 1.1 .1 .1 .1-.1 .9-.2 .1-1.1-.1-.1-.2z"/>
<path d="M140.1 86.7h.2h1.1l.1 .2-.1 .9h-.2h-1.1l-.1-.2z"/>
<path d="M158.3 101.6l.2-.1 .7 .1v.2v.6l-.2 .1-.7-.1v-.1z"/>
<path d="M158.3 99.8l.2-.1 .7 .1v.1v.7l-.2 .1-.7-.1v-.2z"/>
<path d="M138.3 77.9l.1-.1 .7 .1 .1 .2-.1 .6-.2 .1-.6-.1-.1-.2z"/>
<path d="M140.1 77.9l.2-.1 .6 .1 .1 .2-.1 .6-.1 .1-.7-.1-.1-.2z"/>
<path d="M147.3 102.1h.3v1.4h-.1h-.2z"/>
<path d="M147.8 102.1h.3v1.4h-.1h-.2z"/>
<path d="M148.3 102.1h.3v1.4h-.1h-.2z"/>
<path d="M148.8 102.1h.3v1.4h-.1h-.2z"/>
<path d="M149.3 102.1h.3v1.4h-.1h-.2z"/>
<path d="M149.8 102.1h.3v1.4h-.1h-.2z"/>
<path d="M150.3 102.1h.3v1.4h-.1h-.2z"/>
<path d="M150.8 102.1h.3v1.4h-.1h-.2z"/>
<path d="M151.3 102.1h.3v1.4h-.1h-.2z"/>
<path d="M151.8 102.1h.3v1.4h-.1h-.2z"/>
<path d="M152.3 102.1h.3v1.4h-.1h-.2z"/>
<path d="M152.8 102.1h.3v1.4h-.1h-.2z"/>
<path d="M153.6 101.3l1.4-.1 .1 .3h-.1h-1.3z"/>
<path d="M153.6 100.8l1.4-.1 .1 .3h-.1h-1.3z"/>
<path d="M153.6 100.3l1.4-.1 .1 .3h-.1h-1.3z"/>
<path d="M153.6 99.8l1.4-.1 .1 .3h-.1h-1.3z"/>
<path d="M153.6 99.3l1.4-.1 .1 .3h-.1h-1.3z"/>
<path d="M153.6 98.8l1.4-.1 .1 .3h-.1h-1.3z"/>
<path d="M153.6 98.3l1.4-.1 .1 .3h-.1h-1.3z"/>
<path d="M153.6 97.8l1.4-.1 .1 .3h-.1h-1.3z"/>
<path d="M153.6 97.3l1.4-.1 .1 .3h-.1h-1.3z"/>
<path d="M153.6 96.8l1.4-.1 .1 .3h-.1h-1.3z"/>
<path d="M153.6 96.3l1.4-.1 .1 .3h-.1h-1.3z"/>
<path d="M153.6 95.8l1.4-.1 .1 .3h-.1h-1.3z"/>
<path d="M152.8 93.8h.3v1.3l-.1 .1-.2-.1z"/>
<path d="M152.3 93.8h.3v1.3l-.1 .1-.2-.1z"/>
<path d="M151.8 93.8h.3v1.3l-.1 .1-.2-.1z"/>
<path d="M151.3 93.8h.3v1.3l-.1 .1-.2-.1z"/>
<path d="M150.8 93.8h.3v1.3l-.1 .1-.2-.1z"/>
<path d="M150.3 93.8h.3v1.3l-.1 .1-.2-.1z"/>
<path d="M149.8 93.8h.3v1.3l-.1 .1-.2-.1z"/>
<path d="M149.3 93.8h.3v1.3l-.1 .1-.2-.1z"/>
<path d="M148.8 93.8h.3v1.3l-.1 .1-.2-.1z"/>
<path d="M148.3 93.8h.3v1.3l-.1 .1-.2-.1z"/>
<path d="M147.8 93.8h.3v1.3l-.1 .1-.2-.1z"/>
<path d="M147.3 93.8h.3v1.3l-.1 .1-.2-.1z"/>
<path d="M145.3 95.8l1.4-.1v.3h-1.4z"/>
<path d="M145.3 96.3l1.4-.1v.3h-1.4z"/>
<path d="M145.3 96.8l1.4-.1v.3h-1.4z"/>
<path d="M145.3 97.3l1.4-.1v.3h-1.4z"/>
<path d="M145.3 97.8l1.4-.1v.3h-1.4z"/>
<path d="M145.3 98.3l1.4-.1v.3h-1.4z"/>
<path d="M145.3 98.8l1.4-.1v.3h-1.4z"/>
<path d="M145.3 99.3l1.4-.1v.3h-1.4z"/>
<path d="M145.3 99.8l1.4-.1v.3h-1.4z"/>
<path d="M145.3 100.3l1.4-.1v.3h-1.4z"/>
<path d="M145.3 100.8l1.4-.1v.3h-1.4z"/>
<path d="M145.3 101.3l1.4-.1v.3h-1.4z"/>
<path d="M158.3 93.2l.2-.1 .7 .1v.1v.8l-.2 .1-.7-.1v-.2z"/>
<path d="M158.3 94.9l.2-.1 .7 .1v.2v.7l-.2 .1-.7-.1v-.1z"/>
<path d="M131.7 90.7h.2h1.4v.2v1.7v.2l-.2 .1-1.4-.1-.1-.2v-1.7z"/>
<path d="M154.9 93.7l.1-.1 .7 .1 .1 .2-.1 .8h-.2h-.6l-.1-.2z"/>
<path d="M154.9 92l.1-.1 .7 .1 .1 .2-.1 .7-.2 .1-.6-.1-.1-.1z"/>
<path d="M142.9 100.5l.2-.1 1.1 .1 .1 .1-.1 .9-.2 .1-1.1-.1-.1-.2z"/>
<path d="M142.9 98.4l.2-.1 1.1 .1 .1 .2-.1 .8-.2 .1-1.1-.1-.1-.2z"/>
<path d="M151.9 82.8h.2h1.1l.1 .2-.1 .9-.2 .1-1.1-.1-.1-.2z"/>
<path d="M151.9 84.9h.2h1.1l.1 .2-.1 .9h-.2h-1.1l-.1-.2z"/>
<path d="M136 82.8h1v1h-1z"/>
<path d="M122.9 77.8h.2h.7v.2v.7h-.2h-.7l-.1-.2z"/>
<path d="M124.7 77.8h.2h.7v.2v.7h-.2h-.7v-.2z"/>
<path d="M138.3 81.1l.1-.1 .8 .1 .1 .2-.1 .6-.2 .1-.7-.1-.1-.2z"/>
<path d="M140 81.1l.2-.1 .7 .1 .1 .2-.1 .6-.1 .1-.8-.1-.1-.2z"/>
<path d="M148.9 88.8h.6v1.1h-.6z"/>
<path d="M148 88.8h.6v1.1h-.6z"/>
<path d="M147 88.8h.6v1.1h-.6z"/>
<path d="M147 91.4h.6v1.1h-.6z"/>
<path d="M148 91.4h.6v1.1h-.6z"/>
<path d="M148.9 91.4h.6v1.1h-.6z"/>
<path d="M116.2 105h1v1h-1z"/>
<path d="M136.7 98.8h.2h.7v.2v.7h-.2h-.7v-.2z"/>
<path d="M134.9 98.8h.2h.7v.2v.7h-.2h-.7l-.1-.2z"/>
<path d="M151.9 108.9l.2-.1 .8 .1v.2v.6l-.2 .1-.8-.1-.1-.1z"/>
<path d="M150.2 108.9l.2-.1 .7 .1 .1 .2-.1 .6-.1 .1-.8-.1-.1-.1z"/>
<path d="M146.7 108.9l.2-.1 .7 .1 .1 .2-.1 .6-.1 .1-.8-.1-.1-.1z"/>
<path d="M148.4 108.9l.2-.1 .8 .1v.2v.6l-.2 .1-.8-.1-.1-.1z"/>
<path d="M122.7 100l.3-.1h1.4l.2 .3-.1 1-.3 .2-1.4-.1-.2-.3z"/>
<path d="M122.7 102.3l.3-.1h1.4l.2 .3-.1 1-.3 .2-1.4-.1-.2-.3z"/>
<path d="M129 101.1l.3-.1h1.1l.2 .1 .2 .2 .1 3-.1 .2-.2 .2-1.3 .1-.3-.3-.1-3z"/>
<path d="M122.7 104.6l.3-.1h1.4l.2 .3-.1 1-.3 .2-1.4-.1-.2-.3z"/>
<path d="M116.4 98.1h.2h.7l.1 .2-.1 .7h-.1h-.8l-.1-.2z"/>
<path d="M114.7 98.1h.1h.8l.1 .2-.1 .7h-.2h-.7l-.1-.2z"/>
<path d="M136.3 77.7l.2-.1 .7 .1v.1v.8l-.2 .1-.7-.1v-.2z"/>
<path d="M136.3 79.4h.2h.7v.2v.7l-.2 .1-.7-.1v-.1z"/>
<path d="M151 91.4h.6v1.1h-.6z"/>
<path d="M152 91.4h.6v1.1h-.6z"/>
<path d="M152.9 91.4h.6v1.1h-.6z"/>
<path d="M152.9 88.8h.6v1.1h-.6z"/>
<path d="M152 88.8h.6v1.1h-.6z"/>
<path d="M151 88.8h.6v1.1h-.6z"/>
<path d="M117.8 80.9h.2h.7v.2v.7l-.2 .1-.7-.1v-.1z"/>
<path d="M117.8 82.7l.2-.1 .7 .1v.1v.8l-.2 .1-.7-.1v-.2z"/>
<path d="M122.3 80.9h.2h.7v.2v.7l-.2 .1-.7-.1v-.1z"/>
<path d="M122.3 82.7l.2-.1 .7 .1v.1v.8l-.2 .1-.7-.1v-.2z"/>
<path d="M120.5 75h1v1.6h-1z"/>
<path d="M118.7 77.3h1v1.6h-1z"/>
<path d="M117 75h1v1.6h-1z"/>
<path d="M146.7 105.2l.2-.1h1.4l.2 .1 .1 .2v1.9l-.1 .1-.2 .1h-1.4l-.2-.1v-.1v-1.9z"/>
<path d="M150.8 105.2l.2-.1h1.4l.2 .1 .1 .2v1.9l-.1 .1-.2 .1h-1.4l-.2-.1v-.1v-1.9z"/>
<path d="M113.2 83.4h1.1v1h-1.1z"/>
<path d="M110.6 92h.2h1.1l.1 .2-.1 .9-.2 .1-1.1-.1-.1-.2z"/>
<path d="M110.6 94.1h.2h1.1l.1 .2-.1 .9h-.2h-1.1l-.1-.2z"/>
<path d="M156.6 95l.2-.1 .6 .1 .1 .2-.1 .6-.2 .1-.6-.1-.1-.1z"/>
<path d="M156.6 93.2l.2-.1 .6 .1 .1 .1-.1 .7-.2 .1-.6-.1-.1-.2z"/>
<path d="M131.2 87.1l.2-.1 .7 .1 .1 .2-.1 .6-.1 .1-.8-.1-.1-.2z"/>
<path d="M129.5 87.1l.1-.1 .8 .1 .1 .2-.1 .6-.2 .1-.7-.1-.1-.2z"/>
<path d="M136.1 84.7l.2-.1 .6 .1 .1 .1-.1 .8-.2 .1-.6-.1-.1-.2z"/>
<path d="M136.1 86.4l.2-.1 .6 .1 .1 .1-.1 .8-.2 .1-.6-.1-.1-.2z"/>
<path d="M118.6 99.9l.2-.1 .6 .1 .1 .2-.1 .7-.2 .1-.6-.1-.1-.1z"/>
<path d="M118.6 98.2l.2-.1 .6 .1 .1 .1-.1 .8-.2 .1-.6-.1-.1-.2z"/>
<path d="M123.6 88.1l.1-.1h3.5l.2 .1 .1 .2v5l-.1 .1-.2 .1h-3.5l-.1-.1-.1-.1v-5z"/>
<path d="M115.1 88.1l.1-.1h3.5l.2 .1 .1 .2v5l-.1 .1-.2 .1h-3.5l-.1-.1-.1-.1v-5z"/>
<path d="M115.6 80.9h.2h.6l.1 .2-.1 .7-.2 .1-.6-.1-.1-.1z"/>
<path d="M115.6 82.7l.2-.1 .6 .1 .1 .1-.1 .8-.2 .1-.6-.1-.1-.2z"/>
<path d="M133.9 104.9l.4-.1 .1 .1 .1 .9-.1 .2h-.4l-.1-.1z"/>
<path d="M134.7 104.9l.4-.1 .1 .1 .1 .9-.1 .2h-.4l-.1-.1z"/>
<path d="M136 104.9h.3v1l-.1 .1-.2-.1z"/>
<path d="M137 104.9h.3v1l-.1 .1-.2-.1z"/>
<path d="M137.5 104.9h.3v1l-.1 .1-.2-.1z"/>
<path d="M138.5 104.9h.3v1l-.1 .1-.2-.1z"/>
<path d="M139.5 104.9l.4-.1 .1 .1 .1 .9-.1 .2h-.4l-.1-.1z"/>
<path d="M140.3 104.9l.4-.1 .1 .1 .1 .9-.1 .2h-.4l-.1-.1z"/>
<path d="M139 104.9h.3v1l-.1 .1-.2-.1z"/>
<path d="M138 104.9h.3v1l-.1 .1-.2-.1z"/>
<path d="M136.5 104.9h.3v1l-.1 .1-.2-.1z"/>
<path d="M135.5 104.9h.3v1l-.1 .1-.2-.1z"/>
<path d="M138.3 79.5l.1-.1 .7 .1 .1 .2-.1 .6-.2 .1-.6-.1-.1-.2z"/>
<path d="M140.1 79.5l.2-.1 .6 .1 .1 .2-.1 .6-.1 .1-.7-.1-.1-.2z"/>
<path d="M144.9 93.6h.1h.7l.1 .2-.1 .8h-.2h-.6l-.1-.2z"/>
<path d="M144.9 91.9l.1-.1 .7 .1 .1 .2-.1 .8h-.2h-.6l-.1-.2z"/>
<path d="M113.7 100.3l.8-.1v.3l-.8 .1z"/>
<path d="M113.7 100.9h.8v.3h-.8z"/>
<path d="M113.7 101.6l.8-.1v.3l-.8 .1z"/>
<path d="M113.7 102.2h.8v.3h-.8z"/>
<path d="M116.6 102.2h.8v.3h-.8z"/>
<path d="M116.6 101.6l.8-.1v.3l-.8 .1z"/>
<path d="M116.6 100.9h.8v.3h-.8z"/>
<path d="M116.6 100.3l.8-.1v.3l-.8 .1z"/>
<path d="M114.7 100.2h1.7v2.4h-1.7z"/>
<path d="M133.7 84.5h1.5v.7h-1.5z"/>
<path d="M133.7 83.3h1.5v.6h-1.5z"/>
<path d="M133.7 82h1.5v.6h-1.5z"/>
<path d="M133.7 80.7h1.5v.7h-1.5z"/>
<path d="M128.3 80.7h1.5v.7h-1.5z"/>
<path d="M128.3 82h1.5v.6h-1.5z"/>
<path d="M128.3 83.3h1.5v.6h-1.5z"/>
<path d="M128.3 84.5h1.5v.7h-1.5z"/>
<path d="M120.3 104.7l.2-.1 1.2 .1v.2v.8l-.2 .1-1.2-.1v-.1z"/>
<path d="M120.3 106.8l.2-.1 1.2 .1v.2v.8l-.2 .1-1.2-.1v-.2z"/>
<path d="M126.6 81.2l.2-.1 .6 .1 .1 .2-.1 .7-.2 .1-.6-.1-.1-.1z"/>
<path d="M126.6 79.5l.2-.1 .6 .1 .1 .1-.1 .8-.2 .1-.6-.1-.1-.2z"/>
<path d="M156.5 91.5h1v.7h-1z"/>
<path d="M161 91.5h1v.7h-1z"/>
<path d="M156.5 89.3h1v.8h-1z"/>
<path d="M161 89.3h1v.8h-1z"/>
<path d="M151.9 78.4l.2-.1 .6 .1 .1 .2-.1 .6-.1 .1-.7-.1-.1-.2z"/>
<path d="M150.1 78.4l.1-.1 .7 .1 .1 .2-.1 .6-.2 .1-.6-.1-.1-.2z"/>
<path d="M151.9 80.1l.2-.1 .6 .1 .1 .2-.1 .6-.1 .1-.7-.1-.1-.2z"/>
<path d="M150.1 80.1l.1-.1 .7 .1 .1 .2-.1 .6-.2 .1-.6-.1-.1-.2z"/>
<path d="M147.8 83.3h1.5v.4h-1.5z"/>
<path d="M147.8 82.6h1.5v.5h-1.5z"/>
<path d="M147.8 82h1.5v.4h-1.5z"/>
<path d="M147.8 81.3h1.5v.5h-1.5z"/>
<path d="M147.8 80.7h1.5v.4h-1.5z"/>
<path d="M147.8 80h1.5v.5h-1.5z"/>
<path d="M147.8 79.4h1.5v.4h-1.5z"/>
<path d="M147.8 78.7h1.5v.5h-1.5z"/>
<path d="M141.9 78.7h1.5v.5h-1.5z"/>
<path d="M141.9 79.4h1.5v.4h-1.5z"/>
<path d="M141.9 80h1.5v.5h-1.5z"/>
<path d="M141.9 80.7h1.5v.4h-1.5z"/>
<path d="M141.9 81.3h1.5v.5h-1.5z"/>
<path d="M141.9 82h1.5v.4h-1.5z"/>
<path d="M141.9 82.6h1.5v.5h-1.5z"/>
<path d="M141.9 83.3h1.5v.4h-1.5z"/>
<path d="M144.4 79.5h2.4v3.5h-2.4z"/>
<path d="M133.3 98.8h.2h.7v.2v.7h-.2h-.7v-.2z"/>
<path d="M133.3 100.7l.2-.1 .7 .1v.1v.7l-.2 .1-.7-.1v-.2z"/>
<path d="M129 78.7l.2-.1 .8 .1 .1 .2-.1 .7-.2 .1-.8-.1-.1-.1z"/>
<path d="M129 75.9l.2-.1 .8 .1 .1 .2-.1 .7-.2 .1-.8-.1-.1-.1z"/>
<path d="M134.1 78.7l.2-.1 .6 .1 .1 .2-.1 .7-.2 .1-.6-.1-.1-.1z"/>
<path d="M134.1 77l.2-.1 .6 .1 .1 .1-.1 .8-.2 .1-.6-.1-.1-.2z"/>
<path d="M137.8 84.7l.2-.1 1.2 .1v.1v.9l-.2 .1-1.2-.1v-.2z"/>
<path d="M137.8 86.7h.2h1.2v.2v.9h-.2h-1.2v-.2z"/>
<path d="M110.8 90h.9v1h-.9z"/>
<path d="M136.6 100.8l.5-.1 .2 .1v.7l-.1 .2h-.5l-.1-.1z"/>
<path d="M136.6 102.7h.6v.5h-.6z"/>
<path d="M138.6 102.7h.6v.5h-.6z"/>
<path d="M138.6 100.8h.6v.5h-.6z"/>
<path d="M126.7 109.6l.2-.1 .8 .1 .1 .2-.1 1.1-.2 .1-.8-.1-.1-.2z"/>
<path d="M128.8 109.6l.1-.1 .9 .1 .1 .2-.1 1.1-.2 .1-.8-.1-.1-.2z"/>
<path d="M140.3 100.5l.2-.1 .7 .1v.2v.6l-.2 .1-.7-.1v-.1z"/>
<path d="M140.3 98.7l.2-.1 .7 .1v.1v.7l-.2 .1-.7-.1v-.2z"/>
<path d="M118.4 101.8h.1h.8l.1 .2-.1 .7h-.2h-.7l-.1-.2z"/>
<path d="M120.1 101.8h.2h.7l.1 .2-.1 .7h-.1h-.8l-.1-.2z"/>
<path d="M112.8 88.3h.2h1.2v.2v.9h-.2h-1.2v-.2z"/>
<path d="M112.8 86.2h.2h1.2v.2v.9l-.2 .1-1.2-.1v-.2z"/>
<path d="M140.3 94.9h.2h.7v.2v.7l-.2 .1-.7-.1v-.1z"/>
<path d="M140.3 96.7l.2-.1 .7 .1v.1v.8l-.2 .1-.7-.1v-.2z"/>
<path d="M156.4 103.6l.2-.1 .7 .1 .1 .2-.1 .6-.2 .1-.7-.1-.1-.2z"/>
<path d="M154.6 103.6l.2-.1 .8 .1v.2v.6l-.2 .1-.8-.1v-.2z"/>
<path d="M112.5 103.8h.2h.6l.1 .2-.1 .7h-.1h-.7l-.1-.2z"/>
<path d="M110.7 103.8h.1h.7l.1 .2-.1 .7h-.2h-.6l-.1-.2z"/>
<path d="M131.6 78.8l.2-.1 .6 .1 .1 .2-.1 .6-.2 .1-.6-.1-.1-.1z"/>
<path d="M131.6 77l.2-.1 .6 .1 .1 .1-.1 .7-.2 .1-.6-.1-.1-.2z"/>
<path d="M126.8 107.2h.1h.6l.1 .2-.1 .9-.1 .1-.6-.1-.1-.2z"/>
<path d="M130.1 107.2h.1h.6l.1 .2-.1 .9-.1 .1-.6-.1-.1-.2z"/>
<path d="M144.6 85.4h1.7v1.7h-1.7z"/>
<path d="M144.9 102.5h.1h.7l.1 .2-.1 .8h-.2h-.6l-.1-.2z"/>
<path d="M144.9 104.3l.1-.1 .7 .1 .1 .1-.1 .8-.2 .1-.6-.1-.1-.2z"/>
<path d="M154.3 80.3h.2h.7v.2v.7l-.2 .1-.7-.1v-.2z"/>
<path d="M154.3 82.8h.2h.7v.2v.7l-.2 .1-.7-.1v-.2z"/>
<path d="M142.3 84.7l.2-.1 .7 .1v.1v.8l-.2 .1-.7-.1v-.2z"/>
<path d="M142.3 86.4l.2-.1 .7 .1v.2v.7l-.2 .1-.7-.1v-.1z"/>
<circle cx="159.2" cy="108.5" r="1.8"/>
<circle cx="159.2" cy="108.5" r="3.2"/>
<circle cx="112.7" cy="108.5" r="1.8"/>
<circle cx="112.7" cy="108.5" r="3.2"/>
<circle cx="112.7" cy="77.8" r="1.8"/>
<circle cx="112.7" cy="77.7" r="3.2"/>
<circle cx="159.2" cy="77.8" r="1.8"/>
<circle cx="159.2" cy="77.7" r="3.2"/>
<circle cx="148" cy="86.2" r=".85"/>
<circle cx="153.2" cy="90.5" r=".2"/>
<circle cx="153.2" cy="97.5" r=".2"/>
<circle cx="154" cy="91" r=".2"/>
<circle cx="151.5" cy="90.4" r=".2"/>
<circle cx="151.5" cy="91" r=".2"/>
<circle cx="123.2" cy="107.7" r=".3"/>
<circle cx="129.6" cy="96.7" r=".2"/>
<circle cx="161.7" cy="99.5" r=".3"/>
<circle cx="117" cy="110" r=".3"/>
<circle cx="155" cy="111" r=".3"/>
<circle cx="110.2" cy="82" r=".3"/>
<circle cx="115" cy="103.1" r=".3"/>
<circle cx="112.7" cy="99" r=".2"/>
<circle cx="132" cy="82.5" r=".3"/>
<circle cx="147.2" cy="88" r=".2"/>
<circle cx="144" cy="92.6" r=".3"/>
<circle cx="160.7" cy="86" r=".3"/>
<circle cx="161.8" cy="101" r=".3"/>
<circle cx="142.5" cy="92.6" r=".3"/>
<circle cx="127.5" cy="102.7" r=".3"/>
<circle cx="122.3" cy="96.3" r=".3"/>
<circle cx="161" cy="100.2" r=".3"/>
<circle cx="125.9" cy="103.5" r=".3"/>
<circle cx="161" cy="101.7" r=".3"/>
<circle cx="126.4" cy="102.7" r=".3"/>
<circle cx="121" cy="96.3" r=".3"/>
<circle cx="142.1" cy="97.9" r=".3"/>
<circle cx="130.3" cy="96.7" r=".2"/>
<circle cx="155" cy="76.3" r=".3"/>
<circle cx="136" cy="100.5" r=".2"/>
<circle cx="110.5" cy="89.3" r=".3"/>
<circle cx="146.5" cy="103.4" r=".3"/>
<circle cx="124" cy="76.7" r=".3"/>
<circle cx="130.3" cy="95.9" r=".2"/>
<circle cx="131.1" cy="97.5" r=".2"/>
<circle cx="116.1" cy="103.1" r=".3"/>
<circle cx="127" cy="103.5" r=".3"/>
<circle cx="155" cy="107" r=".3"/>
<circle cx="137.1" cy="97.2" r=".2"/>
<circle cx="110.8" cy="97" r=".3"/>
<circle cx="117" cy="107.7" r=".3"/>
<circle cx="137.3" cy="79" r=".2"/>
<circle cx="135.5" cy="101.3" r=".2"/>
<circle cx="124" cy="108.8" r=".3"/>
<circle cx="119.7" cy="96.3" r=".3"/>
<circle cx="111.5" cy="88.5" r=".3"/>
<circle cx="130.8" cy="82.5" r=".3"/>
<circle cx="160.2" cy="101" r=".3"/>
<circle cx="161" cy="98.8" r=".3"/>
<circle cx="138.1" cy="109.9" r=".2"/>
<circle cx="136.3" cy="79" r=".2"/>
<circle cx="129.6" cy="97.5" r=".2"/>
<circle cx="112.2" cy="82" r=".3"/>
<circle cx="140.8" cy="76.2" r=".3"/>
<circle cx="125.2" cy="76.7" r=".3"/>
<circle cx="125.5" cy="108.8" r=".3"/>
<circle cx="132.5" cy="83.5" r=".3"/>
<circle cx="131.1" cy="96.7" r=".2"/>
<circle cx="131.1" cy="95.9" r=".2"/>
<circle cx="161.8" cy="86.5" r=".3"/>
<circle cx="130.3" cy="97.5" r=".2"/>
<circle cx="124.5" cy="75.7" r=".3"/>
<circle cx="115.6" cy="104" r=".3"/>
<circle cx="123.2" cy="75.7" r=".3"/>
<circle cx="152.4" cy="93.2" r=".2"/>
<circle cx="135" cy="100.5" r=".2"/>
<circle cx="160.7" cy="87" r=".3"/>
<circle cx="155" cy="109" r=".3"/>
<circle cx="155" cy="78.3" r=".3"/>
<circle cx="131.2" cy="83.5" r=".3"/>
<circle cx="129.6" cy="95.9" r=".2"/>
<circle cx="161.8" cy="87.5" r=".3"/>
<circle cx="110.5" cy="88" r=".3"/>
<circle cx="111.5" cy="87.3" r=".3"/>
<circle cx="121.5" cy="103.5" r=".3"/>
<circle cx="132.1" cy="98.8" r=".2"/>
<circle cx="155" cy="108" r=".3"/>
<circle cx="122.2" cy="105.7" r=".3"/>
<circle cx="155" cy="77.3" r=".3"/>
<circle cx="134.5" cy="75" r=".3"/>
<circle cx="117" cy="108.8" r=".3"/>
<circle cx="155" cy="110" r=".3"/>
<circle cx="146" cy="102" r=".3"/>
<circle cx="119.5" cy="75.8" r=".2"/>
<circle cx="144.5" cy="110.5" r=".2"/>
<circle cx="111.2" cy="82" r=".3"/>
<circle cx="142" cy="102.5" r=".3"/>
<circle cx="159.2" cy="103.3" r=".2"/>
<circle cx="132.5" cy="98.4" r=".2"/>
<circle cx="155.5" cy="95.3" r=".3"/>
<circle cx="149.9" cy="93.1" r=".2"/>
<circle cx="110.2" cy="81" r=".3"/>
<circle cx="154" cy="76.3" r=".3"/>
<circle cx="124.2" cy="106.5" r=".3"/>
<circle cx="128" cy="103.5" r=".3"/>
<circle cx="139.1" cy="76.2" r=".3"/>
<circle cx="122.2" cy="104.7" r=".3"/>
<circle cx="143.5" cy="102.5" r=".3"/>
<circle cx="123" cy="106.5" r=".3"/>
<circle cx="133.2" cy="75" r=".3"/>
<circle cx="149" cy="91" r=".2"/>
<circle cx="117" cy="111.1" r=".3"/>
<circle cx="147.5" cy="88.5" r=".2"/>
<circle cx="147" cy="90.5" r=".2"/>
<circle cx="159.8" cy="89.7" r=".2"/>
<circle cx="150" cy="91.7" r=".2"/>
<circle cx="159.8" cy="90.5" r=".2"/>
<circle cx="159.7" cy="91.2" r=".2"/>
<circle cx="153.2" cy="99" r=".2"/>
<circle cx="149.2" cy="90.5" r=".2"/>
<circle cx="159.8" cy="92" r=".2"/>
<circle cx="148.8" cy="93" r=".2"/>
<circle cx="137.4" cy="104.1" r=".2"/>
<circle cx="138.2" cy="103.4" r=".2"/>
<circle cx="127.2" cy="109" r=".3"/>
<circle cx="138.5" cy="102" r=".3"/>
<circle cx="159.2" cy="96.3" r=".2"/>
<circle cx="151.6" cy="98.3" r=".2"/>
<circle cx="155.4" cy="99.9" r=".2"/>
<circle cx="159.8" cy="93" r=".2"/>
<circle cx="149.2" cy="84.4" r=".2"/>
<circle cx="152.2" cy="101.7" r=".2"/>
<circle cx="155.8" cy="89" r=".3"/>
<circle cx="159" cy="87" r=".3"/>
<circle cx="157" cy="87" r=".3"/>
<circle cx="155.8" cy="88" r=".3"/>
<circle cx="159" cy="89" r=".3"/>
<circle cx="155.8" cy="87" r=".3"/>
<circle cx="151.5" cy="83.5" r=".2"/>
<circle cx="159.8" cy="93.6" r=".2"/>
<circle cx="155.7" cy="100.4" r=".2"/>
<circle cx="150.7" cy="101.5" r=".2"/>
<circle cx="151.7" cy="101.5" r=".2"/>
<circle cx="153" cy="101.5" r=".2"/>
<circle cx="158.6" cy="97.3" r=".2"/>
<circle cx="151.2" cy="100" r=".2"/>
<circle cx="155.6" cy="101" r=".2"/>
<circle cx="137.9" cy="77.8" r=".2"/>
<circle cx="141.5" cy="81.8" r=".2"/>
<circle cx="139.7" cy="85.3" r=".2"/>
<circle cx="157.9" cy="100.2" r=".2"/>
<circle cx="148.8" cy="101.6" r=".2"/>
<circle cx="119.2" cy="87.3" r=".2"/>
<circle cx="142" cy="94.7" r=".2"/>
<circle cx="118.2" cy="84.3" r=".2"/>
<circle cx="113" cy="103.5" r=".2"/>
<circle cx="118" cy="101" r=".2"/>
<circle cx="116" cy="84.2" r=".2"/>
<circle cx="117.3" cy="87.5" r=".2"/>
<circle cx="153.2" cy="96.9" r=".2"/>
<circle cx="149.7" cy="82.2" r=".2"/>
<circle cx="149.7" cy="81.2" r=".2"/>
<circle cx="151.4" cy="81.2" r=".2"/>
<circle cx="136.2" cy="104.2" r=".2"/>
<circle cx="138.7" cy="104.5" r=".2"/>
<circle cx="120.5" cy="84.3" r=".2"/>
<circle cx="121.5" cy="87" r=".2"/>
<circle cx="122.7" cy="84.3" r=".2"/>
<circle cx="138.8" cy="90.3" r=".2"/>
<circle cx="122.4" cy="88.2" r=".2"/>
<circle cx="153.2" cy="99.8" r=".2"/>
<circle cx="142" cy="100" r=".2"/>
<circle cx="142.1" cy="93.5" r=".2"/>
<circle cx="125.9" cy="77.5" r=".2"/>
<circle cx="149.6" cy="80.3" r=".2"/>
<circle cx="152" cy="79.6" r=".2"/>
<circle cx="149.6" cy="79.6" r=".2"/>
<circle cx="153.5" cy="81" r=".2"/>
<circle cx="142" cy="89.3" r=".2"/>
<circle cx="139.5" cy="80.2" r=".2"/>
<circle cx="141.6" cy="80.1" r=".2"/>
<circle cx="150.5" cy="103.8" r=".2"/>
<circle cx="153.7" cy="102.8" r=".2"/>
<circle cx="141.5" cy="79.4" r=".2"/>
<circle cx="138.4" cy="77.4" r=".2"/>
<circle cx="131" cy="78.7" r=".2"/>
<circle cx="153" cy="98" r=".2"/>
<circle cx="142.1" cy="90" r=".2"/>
<circle cx="142.9" cy="94.6" r=".2"/>
<circle cx="149.1" cy="97.9" r=".2"/>
<circle cx="133" cy="94.3" r=".2"/>
<circle cx="133.5" cy="94.7" r=".2"/>
<circle cx="150" cy="96.3" r=".2"/>
<circle cx="148.8" cy="99.5" r=".2"/>
<circle cx="148.5" cy="95.5" r=".2"/>
<circle cx="143.4" cy="94.4" r=".2"/>
<circle cx="149.3" cy="99.5" r=".2"/>
<circle cx="148.5" cy="96.7" r=".2"/>
<circle cx="125.2" cy="82" r=".3"/>
<circle cx="130.5" cy="86.5" r=".3"/>
<circle cx="129.5" cy="86.5" r=".3"/>
<circle cx="135.3" cy="85.8" r=".2"/>
<circle cx="139.2" cy="80.7" r=".2"/>
<circle cx="141.6" cy="80.7" r=".2"/>
<circle cx="135.1" cy="96.3" r=".2"/>
<circle cx="113.2" cy="102.4" r=".2"/>
<circle cx="114.5" cy="99.7" r=".2"/>
</g>
<path d="M135 91.5v.5M137.5 91.5v.5M140 91.5v.5" fill="none" stroke="#c83434" stroke-width="1.7"/>
<path d="M133 105.4v1.1M133 109.8v.8M141.7 105.4v1.1M141.7 109.8v.8" fill="none" stroke="#c83434" stroke-width="1"/>
<g fill="none" stroke="#c83434" stroke-width=".15">
<path d="M119.3 78.1l1.7-.1 .2 .3h2.1M119.5 75.8h1.5M125.9 77.5h-.4l-.3 .3v.5M131 78.8l-.2 .2h-1.1l-.2 .2M114.5 99.7l-.4 .4v.3M116 83.3v1M118.2 83.3v1M120.5 83.3v1M122.8 83.3v1M130.1 98.6v1l3.3 3.3h3.5l1.2 1.2v1.8l-.3 .3h-.4l-.3-.3v-.5M130.6 98.6v1l2.6 2.7h4.3l.7 .6h.7l-.5 .5h-.2M131.7 87.1v.4"/>
<path d="M133 94.3l-.5-.6h-3.9l-1.2 1.2v1.1l.4 .4h.6M133.5 94.8h-.7l-.8-.8h-3.3l-1 1v.8l.1 .1h.6M134.5 84.8h.2l.6 .6v.4M135.1 96.3l-.6 .6h-2.2M138.8 90.3v8l1.7 1.7h1.5M142.9 94.6l1.4 1.4M143.7 94h-.9l-.8 .8M144.6 96.9h1.4M144.7 98.2v.6l.6 .6h.7M144.8 95h1.5l.7 .7v.6l-.1 .1h-.9M145.2 95.9h.8M146 98.9h3.4l1.1 1.1h.7"/>
<path d="M147.3 92v.2l1.6 1.6M147.5 88.5l-.2 .2v1.5l-.3 .3M148.4 94.5h.1v1M148.7 93l.2 .2v1.3M148.7 99.5l-.3 .4h-2.4M149.2 92l.2 .2v2.3M149.2 89.4l.1 1.1M149.2 92h.1M149.3 99.5l-.8 .9h-2.5M149.9 94.5v1.1l-.5 .5v1.5l-.3 .3M150 91.8h-.5l-.3 .2M150.4 94.5v1.3l-.4 .5"/>
<path d="M150.4 88.7v4.1l.5 .5v1.2M151.5 90.4l-.2-.1v-.9l-.5 .5v2.8l.6 .7v1.1M151.5 91l-.2 .2v1.4l.6 .6v1.3M151.6 98.3l-.1 .1h-5.5M153 98h.3l.4 .4h.6M153.2 89.4l.5 .5v.9l.3 .2M153.2 89.4v1.1M153.7 93.3v-.8l-.5-.5v.9l-.3 .3v1.3M154.3 97.4l-.1 .1h-1M154.3 96.9h-1.1M154.3 98.9l-.1 .1h-1M154.3 99.9h1.2"/>
<path d="M154.3 99.4h-.7l-.4 .4M154.8 93.4h2l.2 .2M157 93.6h1.7M157 93.6h.1M161.5 91.8l-.7 .7h-3.1l-.7-.7v1.8M114.1 102.4h-.9M136.2 104.2l-.1 .1v1.1M136.8 104.6h.5l.3 .3v.5M137.4 104.1l-.8 .7v.6M138.7 104.5h.2l.2 .2v.7M148.9 109.3h1.8M149.4 102.8v1.7l-1.8 1.8v.2l-.4 .4v2.4"/>
<path d="M149.8 109.3v1.3M149.9 102.8v1.7l2.4 2.4v2.3l.1 .1M150.4 102.8v.9l.1 .1M152.2 101.7l-.3 .2v.9M153 101.5v1.2l-.1 .1M154.3 100.4h1.4M154.3 100.9l.1 .1h1.2"/>
</g>
<path d="M121 98.2l-.4 .4h-1.6M136.5 86.8l.4 .5h1.6M142.8 86.9l-.4 .4h-1.7M134.2 105.4h-.6l-.6 .6M140.6 105.4h.5l.6 .6" fill="none" stroke="#c83434" stroke-width=".5"/>
<g fill="none" stroke="#c83434" stroke-width=".25">
<path d="M127 78.1v1.8M132 79.2v1.8l1.3 1.3h1.2l-.1-.1M134.5 79.2v1.8M137.9 77.8h-1l-.2 .2M138.7 79.9l.3 .3h.5M138.7 77.8v.5M141.5 79.4l.2 .2h1M148.5 79.6h1.1M152.3 78.8v.7l-.1 .1h-.2M127 81.7l.7 .6h1.3M129 81l-.2-.2h-2.4l-1.2 1.2M132.3 97.4h.6"/>
<path d="M133.7 98.2v1.1h1.6M136.7 80v1M137.2 99.3l1.7 1.7v.6l-.4 .4M139.2 80.7h-.3l-.1 .1-.1 .7M140.7 97.3v1.8M141.5 81.8l.5 .4h.7M141.6 80.7l.2 .2h.9M141.6 80.1h1l.1 .2M143.2 89.2l-1.2 .1M143.5 98.9v.4l1.6 1.6h.9M144.9 94.1h.4l.3 .4h1.8M147.4 93.2l.5 .5v.8"/>
<path d="M148.5 82.2h1.1M148.5 80.9h.8l.4 .4M148.5 80.3h1.1M149 91h-.6l-.1 .1v.9M152.3 88v1.4M152.3 80.5l-.7 .8M156.1 89.7h2l.2 .2M157 95.4l-1.2-1.2h-.5l.2 .2v1.2l-.3 .3h-.9M111.7 102.5l-.6 .7v1.1M113 103.5l-.1 .1v.7M114.1 100.4h-2.3l-.1 .1M116.7 105.5h1.8"/>
<path d="M140.7 100.9h2.8l.4 .5h2.1v.9l-.7 .7M145.5 102.8h1.9M146.5 103.4h-.2l-1 1v.3M150.7 101.5l.2 .2v1.1M151.7 101.5l-.3 .2v1.1M157 100.2h1.7M157 102l-2.1 2M158.7 102v.8l.6 .5"/>
</g>
<g fill="#c83434">
<path d="M117.8 83.5l.5-.4 .4 .4-.4 .6h-.1z"/>
<path d="M124.9 77.8l.7-.4v.6l-.4 .2z"/>
<path d="M149.3 81.1l.2-.2 .3 .2-.3 .3z"/>
<path d="M134.4 99.1l.6-.3 .3 .5-.3 .4-.6-.3z"/>
<path d="M155.1 99.8l.3-.1v.4l-.3-.1z"/>
<path d="M138.8 80.7l.3-.2 .1 .2v.2h-.3z"/>
<path d="M156 93.3l.7-.2 .3 .5-.4 .4-.6-.5z"/>
<path d="M151.9 101.9l.2 .2-.2 .6-.1-.6z"/>
<path d="M146.1 98.4l.6-.2 .2 .1v.1l-.2 .1z"/>
<path d="M120.4 83.9h.2l.1 .3h-.4z"/>
<path d="M141.6 80h.4v.3h-.4z"/>
<path d="M155.4 94.7h.3l.1 .5h-.6z"/>
<path d="M145.6 102.5l.6 .2v.2l-.5 .5-.4-.4z"/>
<path d="M152 101.6l.2 .1v.2l-.3 .1z"/>
<path d="M150.9 93.6h.1l.1 .2-.2 .6-.1-.6z"/>
<path d="M131.4 87l.7-.4 .1 .1v.6l-.5 .2z"/>
<path d="M138.6 101.3l.3-.3 .3 .3-.2 .4z"/>
<path d="M142.9 94.6l.1-.1 .2 .4-.1 .1-.3-.2z"/>
<path d="M141.1 100.5l.6 .3v.2l-.6 .4-.3-.5z"/>
<path d="M119.7 77.5l.5 .4v.2l-.5 .4-.4-.5z"/>
<path d="M141.7 79.5l.2-.1 .7 .2-.7 .2-.2-.1z"/>
<path d="M148.4 95.1h.2l.1 .4h-.4z"/>
<path d="M138.3 101.7l.5-.2 .2 .2-.3 .5-.2-.2z"/>
<path d="M116.8 105.5l.5-.5 .4 .4 .1 .2-.6 .4z"/>
<path d="M122.3 83.5l.5-.4 .4 .4-.4 .6h-.1z"/>
<path d="M157.5 100.1l.4-.1v.4l-.4-.1z"/>
<path d="M153.3 98.8l.3 .1v.2l-.3 .1z"/>
<path d="M112.8 103.5l.4 .1-.2 .3h-.2z"/>
<path d="M149 97.7l.5-.1-.2 .3h-.2z"/>
<path d="M158.7 102l.5 .3-.4 .7-.5-.6z"/>
<path d="M155.2 95.3h.3l.3 .1-.4 .4-.2-.1z"/>
<path d="M155.3 94.2l.5-.3 .4 .5-.2 .2-.4 .1z"/>
<path d="M136 104.3l.2-.1 .1 .1-.1 .3h-.2z"/>
<path d="M150.4 102.8l.2 .7-.1 .2h-.2v-.2z"/>
<path d="M139 104.7h.2v.2l-.1 .5-.1-.5z"/>
<path d="M151.3 89.4l.3 .5-.2 .3h-.1l-.3-.3z"/>
<path d="M141.7 82.1l.2-.2 .8 .1v.2l-.8 .1z"/>
<path d="M138.3 77.5l.2-.2 .2 .3-.2 .2-.3-.2z"/>
<path d="M148.6 80.2l.7-.2 .2 .1v.3l-.2 .1z"/>
<path d="M147.3 89.4l.3 .5-.3 .4-.3-.4z"/>
<path d="M151.4 93.6h.1l.1 .2-.2 .6-.1-.6z"/>
<path d="M131.6 79.5l.4-.3 .5 .3-.4 .7h-.2z"/>
<path d="M122.4 78.2l.6-.4 .3 .5-.3 .4-.6-.4z"/>
<path d="M138.3 77.6l.2-.2 .5 .4-.3 .5-.5-.2z"/>
<path d="M115.4 93.7h3.8l-.5 .5v3l-.1 .1-.9 .5v1.4h-1.5v-1.4l-.4-.5v-3.1z"/>
<path d="M149.1 99.5h.2l.1 .2-.3 .2-.1-.1z"/>
<path d="M151.3 101.9h.3l-.2 .9z"/>
<path d="M138.8 104.3l.3 .2-.1 .1-.3 .1v-.2z"/>
<path d="M154.4 100.4l.6-.2 .2 .1v.1l-.2 .1z"/>
<path d="M154.4 99.9l.6-.2 .2 .1v.1l-.2 .1z"/>
<path d="M128 80.7a1.37 1.37 0 0 1 1 .3l-.7 .2-.3-.2z"/>
<path d="M156.2 94.7l.1-.1 .9 .3-.2 .5-.5 .2z"/>
<path d="M151.3 91h.2l.1 .2-.2 .1h-.1z"/>
<path d="M132.3 97.4l.5-.1v.2h-.1z"/>
<path d="M145.9 101.4h.2l.2 .5h-.6z"/>
<path d="M151.5 101.4l.3 .2-.5 .2z"/>
<path d="M115.9 83.9h.2l.1 .3h-.4z"/>
<path d="M147.4 88.5l.2 .3-.3 .6-.2-.6z"/>
<path d="M149.9 94.5l.2 .7-.1 .2h-.1l-.1-.2z"/>
<path d="M127.8 96.4l.1-.1 .4 .1-.4 .1z"/>
<path d="M136.3 80.2l.5-.3 .4 .4-.3 .6h-.3z"/>
<path d="M145.2 99.2h.8v.2h-.7l-.2-.1z"/>
<path d="M153.2 90.1h.1l.1 .4h-.3z"/>
<path d="M146.1 96.4l.6-.2 .2 .2-.2 .1z"/>
<path d="M161 91.8h.5l.2 .4-.8 .3-.1-.1z"/>
<path d="M146.1 98.9l.6-.2 .2 .1v.1l-.2 .1z"/>
<path d="M151.4 81.1l.3-.1 .1 .2-.3 .2z"/>
<path d="M135.2 85.4h.2l.1 .4h-.4z"/>
<path d="M112.9 103.4l.4 .4-.4 .4-.4-.4z"/>
<path d="M111 103.3h.2l.4 .6-.5 .3-.5-.3z"/>
<path d="M153.2 89.4l.3-.1 .3 .5-.1 .1h-.2z"/>
<path d="M144.4 93.8l.2-.2h.4l.3 .5-.5 .3z"/>
<path d="M154.4 100.9l.7-.1 .1 .1v.1z"/>
<path d="M113.5 100.3l.3-.1 .3 .2-.3 .2-.3-.1z"/>
<path d="M146 101.4l.2 .1-.1 .2h-.2v-.2z"/>
<path d="M128 82.2l.3-.2 .7 .3-.7 .3-.3-.2z"/>
<path d="M153.5 98.9l.1-.1 .7 .1v.1l-.8 .1z"/>
<path d="M151.8 80.3l.5 .2 .2 .5-.8 .3-.2-.1z"/>
<path d="M149.2 92l.3 .5v.3h-.2l-.2-.3z"/>
<path d="M153.2 89.4l.3 .5-.2 .3h-.1l-.3-.3z"/>
<path d="M147.3 92l.3-.1 .3 .8-.1 .1-.4-.3z"/>
<path d="M142 89.1h.4v.2l-.4 .1z"/>
<path d="M142.2 100.8l.8-.4 .5 .6-.6 .5-.7-.5z"/>
<path d="M151 89.3l.3 .1-.3 .5h-.1l-.1-.1z"/>
<path d="M142.3 89.1l.6-.2 .3 .5-.4 .4-.5-.4z"/>
<path d="M143.5 101l.7-.4 .6 .7v.2l-.8 .1z"/>
<path d="M157 91.8l.4 .4-.3 .4h-.2l-.3-.4z"/>
<path d="M151.9 93.6h.1l.1 .2-.2 .6-.1-.6z"/>
<path d="M140.3 97.5l.5-.4 .4 .4-.3 .6h-.3z"/>
<path d="M152.2 88.5h.2l.2 .3-.3 .6-.3-.6z"/>
<path d="M114.1 100l.2 .2-.2 .2-.1-.2z"/>
<path d="M146.3 103.2l.2 .2 .1 .3-.5 .1-.2-.2z"/>
<path d="M151.3 92l.3 .5-.1 .3-.3-.3z"/>
<path d="M114.7 100.1h1.6l.1 .6v1.3l.2 .2h.9l.2 .2v.3h-3v-.2v-.5h-1v-.5h1v-.3z"/>
<path d="M150.9 99.9l.3-.1v.4l-.3-.1z"/>
<path d="M120.1 104.3l.3-.1 .4-.2h3.9v2.9l-2.1 .1-.1-.1v-.4l-.3-.2-2.1-.1z"/>
<path d="M113.5 102.3l.2-.1 .4 .2-.4 .1-.2-.1z"/>
<path d="M148.6 79.6l.7-.2 .2 .1v.2l-.2 .1z"/>
<path d="M116.6 101.6l1.4-.1v.9l-.4-.4h-1z"/>
<path d="M157.3 93.1l.6 .4v.2l-.6 .4-.3-.5z"/>
<path d="M148.6 80.9l.7-.1 .2 .1-.2 .2z"/>
<path d="M145.1 96.8l.2-.1 .7 .2-.7 .1h-.2z"/>
<path d="M141.9 94.6l.3-.2 .1 .1-.1 .4z"/>
<path d="M118 101.5h1.4l.1 .1v7.2l.7 .7h5.6l.7-.7v-1.7l1.4-.1 .1 .1v3.8l-9.9 .1z"/>
<path d="M157 91.8h.5l.2 .6-.1 .1-.8-.3z"/>
<path d="M116.2 99.2h1.5v1.3l-1.1 .1-.1-.9-.3-.3z"/>
<path d="M122.7 83.9h.1l.1 .3h-.3z"/>
<path d="M149.9 96.1l.3-.2 .1 .1-.1 .4z"/>
<path d="M148.7 93h.2l.1 .3-.4-.1z"/>
<path d="M153.5 99.4l.1-.1 .7 .1v.1l-.7 .1z"/>
<path d="M149.5 91.5l.3 .2v.1l-.3 .4-.3-.2z"/>
<path d="M146.1 99.9l.6-.2 .2 .1v.1l-.2 .1z"/>
<path d="M131.5 103.9l4.2-.1a.35 .35 0 0 1 .1 .5l-.1 .3a.43 .43 0 0 0-.4 .3v1l.1 .3h1.5l.4 .3 2.4-.1a.6 .6 0 0 0 .4 .7 .6 .6 0 0 0 .7-.4h.1a.87 .87 0 0 0 1 .5l.2-.1 .2-.4 .1-1.3a.77 .77 0 0 0-1.3-.5l-.4-.3-.4 .1-.2 .1v1.1l-.3 .2-.1 .3h-1.7l.4-.2h.8l.2-.2 .1-1.1-.2-.4-.5-.4h-.3a.15 .15 0 0 1-.2-.1 .15 .15 0 0 1 .2-.2h4.6l.1 5.1-11.6 .1-.1-2.4h.8a.72 .72 0 0 0 .7 .6 .72 .72 0 0 0 .8-.5h.1a.6 .6 0 0 0 1 .2 .6 .6 0 0 0-.2-1v-.9l-.2-.3h-.6l-.3 .2h-.1a.7 .7 0 0 0-1.2 .5v1.2h-.8z"/>
<path d="M123.3 87.8l3.9-.1 .8-.7v-2.7l2.9-.1 .1 9.2-2.5 .1-.3 .2h-4.9z"/>
<path d="M149.2 89.4l.3 .5-.2 .3h-.1l-.3-.3z"/>
<path d="M129.9 78.6l.7 .3v.2l-.6 .5-.5-.5z"/>
<path d="M149.3 82.1h.3v.3l-.3-.1z"/>
<path d="M118.2 83.9h.1l.1 .3h-.3z"/>
<path d="M149.6 91.7l.4-.1v.3l-.4-.1z"/>
<path d="M141.7 80h1v.2l-.8 .2-.2-.1z"/>
<path d="M137.5 77.7l.4-.1v.4l-.4-.1z"/>
<path d="M114.3 99.6l.3 .3-.3 .1-.1-.1z"/>
<path d="M139.6 77.4h11.8l.2 .1v2.9l-.2 .4a.42 .42 0 0 0-.4 .5 .42 .42 0 0 0 .5 .4l.1 .4-.2 .1h-1.2l-.4-.3a.13 .13 0 0 1-.1-.1 .13 .13 0 0 1 .1-.2 .5 .5 0 0 0 0-.8l-.1-.1a.65 .65 0 0 0 .2-.8 .47 .47 0 0 0 0-.5 .47 .47 0 0 0-.5-.2h-1.6l-.2 .1v3l-.1 .1h-.4l-.1 .7-2.8 .1-.1-.2v-.6h-.4l-.1-.1v-3.7l-.2-.1h-.7l-.4-.5a.43 .43 0 0 0-.6 0 .43 .43 0 0 0 0 .6v.4a.44 .44 0 0 0-.6 .3 .44 .44 0 0 0 .2 .5l-.1 .3 .1 .3a.65 .65 0 0 0 .3 .8v.1a.54 .54 0 0 0-.4 .8l-1.6 .1v-1.5a.5 .5 0 0 0 .3-.5 .5 .5 0 0 0-.3-.5z"/>
<path d="M148.9 93.6h.1l.1 .2-.2 .6-.1-.6z"/>
<path d="M147.1 94.3h.2l.1 .2-.1 .1h-.2z"/>
<path d="M153.5 97.4l.1-.1 .7 .1v.1l-.8 .1z"/>
<path d="M152.5 82.3h7.1h.1v7l-.3 .2h-1l-.3-.2h-.4l-.1-.2h-1.1l-.2 .2-.5 .2-.8-.1v-1.3h2.3a.68 .68 0 0 0 1 .6 .68 .68 0 0 0 0-1.2 .68 .68 0 0 0-1 .5v.1h-2.3v-3.3l-.5-.5h-2z"/>
<path d="M146.1 100.4l.6-.2 .2 .1v.1l-.2 .1z"/>
<path d="M120 75.7l.5-.4 .5 .4-.5 .5-.5-.4z"/>
<path d="M125.5 77.4l.4-.1v.4l-.4-.1z"/>
<path d="M153.1 97.8l.3 .2-.4 .2v-.2z"/>
<path d="M118.4 99.7l6.2-.1 .1 .1v1.5l-.1 .1h-5v-1.5h-1.1l-.1 .4z"/>
<path d="M134.4 80.4h.2l.2 .3-.3 .3-.3-.3z"/>
<path d="M153.1 99.6l.3-.1 .1 .1-.1 .3z"/>
<path d="M155.3 100.3l.3-.1v.4l-.3-.1z"/>
<path d="M156.9 92.6h.2l.3 .6-.4 .4-.5-.4z"/>
<path d="M113.3 102.2l.3 .1v.1l-.3 .2-.1-.2z"/>
<path d="M134.9 96.2l.3 .3-.4 .1-.1-.1z"/>
<path d="M132.7 94l.1-.1 .3 .2-.3 .3z"/>
<path d="M148.6 99.4l.3 .3-.4 .1-.1-.1z"/>
<path d="M133.6 98.3h.3l.3 .6-.5 .3-.4-.3z"/>
<path d="M148.6 90.9l.4-.1v.4l-.4-.1z"/>
<path d="M153.7 90.7l.4 .1-.1 .2h-.2z"/>
<path d="M153.5 96.8l.1-.1 .7 .2-.7 .1h-.1z"/>
<path d="M141.8 80.7h.1l.7 .2-.7 .2-.3-.2z"/>
<path d="M132.3 96.9l.4-.1h.1v.2h-.1z"/>
<path d="M147.1 102.7l.2-.1 .1 .2-.1 .1h-.2z"/>
<path d="M148.2 91l.4 .4-.3 .6-.3-.6z"/>
<path d="M149.4 93.6h.1l.1 .2-.2 .6-.1-.6z"/>
<path d="M138.6 90.3h.4l-.1 .4h-.2z"/>
<path d="M149.2 90.1h.1l.1 .4h-.3z"/>
<path d="M130.8 78.7h.2v.2l-.3 .2z"/>
<path d="M133.1 94.7l.4-.1v.3l-.4-.1z"/>
<path d="M135.8 82.4h5.8l.3 .2h1.6l.1 .1-.1 3.4h-7.6z"/>
<path d="M157.9 100l.4 .1v.2l-.4 .1z"/>
<path d="M127 81.7l.5-.3 .3 .8v.2l-.9-.2z"/>
<path d="M137 77.6l.7 .1v.2l-.5 .6-.4-.4z"/>
<path d="M125.1 81.7l.5-.2 .2 .2-.3 .5-.3-.2z"/>
<path d="M141.5 79.4l.2-.1 .1 .2v.2l-.3-.1z"/>
<path d="M137.2 99.2l.5-.1 .3 .8-.2 .2-.8-.4z"/>
<path d="M145.1 102.5l.8-.3h.2l-.3 1-.5-.2z"/>
<path d="M157.8 100l.6-.3 .3 .5-.3 .4-.6-.3z"/>
<path d="M145.7 101.9l.6 .3-.4 .4-.2-.2z"/>
<path d="M157.8 93.5l.6-.4 .3 .5-.4 .5-.5-.4z"/>
<path d="M150.8 101.9h.3l-.2 .9z"/>
<path d="M151.2 98.3l.3-.2 .1 .2v.2h-.4z"/>
<path d="M153.7 92.9h.1l.1 .3h-.3z"/>
<path d="M138.4 81l.4-.4 .4 .5-.5 .4z"/>
<path d="M150.7 101.5l.1-.1 .2 .4-.4-.2z"/>
<path d="M139.1 80.1l.4-.1v.4l-.4-.1z"/>
<path d="M149.2 79.5l.4-.1v.4l-.4-.1z"/>
<path d="M127.8 95.8h.1l.4 .1-.4 .1h-.1z"/>
<path d="M115.6 83.5l.4-.4 .5 .4-.4 .6h-.2z"/>
<path d="M153.3 96.8h.3v.2l-.2 .1-.2-.2z"/>
<path d="M152.8 101.5h.4l-.1 .4h-.2z"/>
<path d="M141.6 99.9l.4-.1v.4l-.4-.1z"/>
<path d="M140.6 98.1h.3l.3 .6-.5 .4-.4-.4z"/>
<path d="M149.2 80.1h.4v.4l-.4-.1z"/>
<path d="M141.6 80.7l.2-.1 .1 .2v.2l-.3-.1z"/>
<path d="M134.5 84.9l.7 .1 .2 .4-1-.2z"/>
<path d="M141.5 81.7l.2-.1 .2 .3-.2 .2-.3-.2z"/>
<path d="M133.5 83.1l2-.1 .3-.6v2.2l-.3-.3-1.9-.1z"/>
<path d="M138.7 79.9l.5-.3a.72 .72 0 0 1 .3 .7l-.6 .1z"/>
<path d="M147.3 88.5h.2l.1 .2-.2 .1h-.1z"/>
<path d="M148.4 94.5h.2v.9h-.2l-.1-.2z"/>
<path d="M156.5 101.8l.5 .2 .2 .5-.9 .3-.1-.1z"/>
<path d="M148.7 93.7l.1-.1 .1 .1v.8h-.1z"/>
<path d="M145.3 94.1l.5-.3 .4 .5v.3h-.7z"/>
<path d="M148.6 82.2l.7-.2 .2 .1v.2l-.2 .1z"/>
<path d="M154.4 95.9l.6-.2 .3 .3h-.3z"/>
<path d="M152.9 93.6h.1l.1 .2-.2 .6-.1-.6z"/>
<path d="M146.9 90.3l.3-.1 .1 .1-.1 .3z"/>
<path d="M154.9 103.5l.8-.4 .2 .2-.3 .8-.5-.1z"/>
<path d="M151.3 91.1l.3 .3-.3 .6-.2-.6z"/>
<path d="M153.5 98.2h.1h.7v.2h-.7z"/>
<path d="M136.6 80.6h.3v.4h-.3z"/>
<path d="M155.2 100.9l.4-.1v.3l-.4-.1z"/>
<path d="M134.1 98.8l.6 .3v.3l-.6 .3-.3-.5z"/>
<path d="M111.3 102.2l.5 .2 .1 .5-.7 .3h-.2z"/>
<path d="M120.1 83.5l.4-.4 .5 .4-.4 .6h-.2z"/>
<path d="M153.2 92l.3-.1 .3 .5-.1 .1h-.2z"/>
<path d="M157.3 99.7l.6 .4v.2l-.6 .3-.3-.4z"/>
<path d="M133.4 82.2l.3-.2 .7 .3-.7 .3-.3-.2z"/>
<path d="M134.1 79.5l.4-.3 .5 .3-.4 .7h-.2z"/>
<path d="M110.5 89.8h1.5l.5-.5v-1.4l.1-.1h4.3a.52 .52 0 0 0 .7 0h1.5h.1v5.9h-8.7z"/>
<path d="M147.6 82.7l1.8-.1a.71 .71 0 0 0 .7-.2h2.4v1.9h2l.2 .1h-5.1a.44 .44 0 0 0-.4-.4 .44 .44 0 0 0-.4 .4h-1.1l-.1-.1z"/>
<path d="M144.5 98.2h.4l-.1 .4h-.2z"/>
<path d="M130.9 98.2h.7l.3-.4h.8v1.3l-1.7 .1z"/>
<path d="M155.3 94.2l.5 .3-.1 .7h-.3l-.5-.5z"/>
<path d="M145.1 95.9l.2-.1 .7 .1-.7 .1z"/>
<path d="M150.4 94.5l.2 .7-.1 .2h-.2v-.2z"/>
<path d="M129.8 107l1.7-.5v2.5l-1.7-.5z"/>
<path d="M151.3 90.1l.3 .2-.1 .1-.2 .1z"/>
<path d="M150.4 103.4h.1l.2 .3-.2 .1-.2-.1z"/>
<path d="M112.1 100.1l.6 .2v.2l-.5 .5-.4-.4z"/>
<path d="M129.3 98h.5l-.1 .2v.9h-.3v-.9z"/>
<path d="M116.6 100.9l1.2-.1 .7-.6v-.4h1.1v1.5h-2.9l-.1-.1z"/>
<path d="M126.9 78.9h.2l.4 .6-.5 .4-.5-.4z"/>
<path d="M129 95.4h2.6v2.5h-2.6z"/>
<path d="M151.9 79.2l.4-.4 .4 .4-.4 .5z"/>
<path d="M138.5 100.4l.5 .3-.1 .3-.3 .1-.2-.5z"/>
<path d="M153.2 92l.3 .5-.2 .3h-.1l-.3-.3z"/>
<path d="M145.1 101.3l.9 .1-.9 .1z"/>
<path d="M153.3 97.3l.3 .1v.2l-.3 .1z"/>
<path d="M152.9 101.9h.2v.9h-.2l-.1-.7z"/>
<path d="M126.6 78.5l.4-.4 .5 .4-.4 .6h-.2z"/>
<path d="M145.9 103.5l.4-.4h.7l.1 .1 .1 .5a.17 .17 0 0 1 .1 .1 .17 .17 0 0 1 0 .2h-1.2l-.3-.3z"/>
<path d="M144.1 100l.4-.2 .3-.4 .3 .2v.7l-.3 .4h-.2l-.5-.5z"/>
<path d="M147.8 94.5h.2h.1v1.2a.5 .5 0 0 0 .5 .2 .5 .5 0 0 0 .4-.5h.2a.17 .17 0 0 1 .3 0 .17 .17 0 0 1-.1 .3l-.3 .4v.5a.35 .35 0 0 1-.4-.2 .41 .41 0 0 0-.6 .3 .41 .41 0 0 0 .3 .5 .41 .41 0 0 0 .5-.3h.2v.5l-.3 .2-.1 .4-.1 .1h-1.6l-.1-.5 .1-.6a.49 .49 0 0 1 .2-.6l.1-.8 .1-.1 .4 .2z"/>
<path d="M151.9 90.2l.8-.1a.17 .17 0 0 1 .2 .1 .17 .17 0 0 1 0 .2v.5h-.4v2.1l.1 .1v.3v.1h-.3h-.1v-.4l-.2-.2v-2h-.1l-.1-.2z"/>
<path d="M114.4 74.6h2l.2 .1-.1 .8h2l-.1-.9h.1h1.9l.1 .1-.2 .2v.3l-.4 .3a.44 .44 0 0 0-.6-.1 .44 .44 0 0 0 0 .7 .44 .44 0 0 0 .5-.1l.5 .3v.3l.2 .2 1.1-.1 .1-.1v-.5h16.9v.2a.5 .5 0 0 0 .5 .4 .5 .5 0 0 0 .5-.5h13.9v.1a.5 .5 0 0 0 .8 .4 .5 .5 0 0 0 0-.9 .5 .5 0 0 0-.8 .4h-13.9v-.2a.51 .51 0 0 0-.6-.3 .51 .51 0 0 0-.4 .4h-16.9v-.1h6.8v.1h2v-.1a.74 .74 0 0 0-.8-.7v.8h-.4v-.8l-.6 .2-.2 .2v.3h-.5a.73 .73 0 0 0-.8-.7v.7h-.5v-.7l-.4 .2-.3 .5h-4.3v-1.1l-.2-.2 .2-.1h11h.1a.54 .54 0 0 0 .1 .8 .54 .54 0 0 0 .7 0 .54 .54 0 0 0 .1-.8h.3l.1 .1a.52 .52 0 0 0 .1 .7 .52 .52 0 0 0 .7 0 .52 .52 0 0 0 0-.7l.1-.1h22.5h.1v.2a3.4 3.4 0 0 0-.7 5.4 3.4 3.4 0 0 0 5.4-.8l.1 .1v9.3l-.1 .1-.6-.1v1.8l.6-.1 .1 .1v16.2l-.1 .1a3.4 3.4 0 0 0-5.4-.8 3.4 3.4 0 0 0 .7 5.4l-.1 .2h-15.3l-.1-.1a1.36 1.36 0 0 0 .6-1.2h-.7v-.4h1.8l.1 1.1 1.1 .1 .2-.1v-1.1l-.1-.2h-1.1l-.2 .2h-1.8l.7-.1-.1-.7h.6l.2-.3v-3.8h.9l.3 .5 .4 .2v-.8l-1.6 .1v-1.2l-.3-.3h-3.7l-.1-.1 .2-.3v-.5l-.3-.3h2.3a.5 .5 0 0 0 .5 .6 .5 .5 0 0 0 .5-.6h.5v.2a.5 .5 0 0 0 .8 .3 .5 .5 0 0 0 0-.8 .5 .5 0 0 0-.8 .3h-.5l-.1-.2a.5 .5 0 0 0-.5-.2 .5 .5 0 0 0-.4 .4h-2.5l-.1-.2 .6-1-.1-.5-.3-.2a1.95 1.95 0 0 1-1.2-1.5 .43 .43 0 0 0-.4-.4h-.7l-.2 .1-.1 .2v.6a.66 .66 0 0 0 .5 .5l.2 .1v.9h.6l-.1-.5 .1-.1 .4 .3 .2 .4v.3l-.3 .3-.2 .5-.2-.2 .1-.5h-1.7v.4l-.1 .1h-1.3l-.1-.2 .1-.5h-1.9l-.6-.5h3.9v.2h.6v-.8l-.5 .3-.1 .3h-3.9l-1.2-1.2v-.1l.1-.1h1.5l.4-.1 .1 .4 .3 .2-.1 .2a.72 .72 0 0 0-.5 .7h1.9a1.01 1.01 0 0 0-.6-.7l.1-.2 .4-.2 .4 .2h.7l.2-.1 .1-.2v-.7l-.1-.2-.2-.1h-.7l-.5 .2-.2-.2-.3-.6-.6-.7 .1-.1h1l.8-.5a.4 .4 0 0 0 0-.7 .4 .4 0 0 0-.6 .1l-.4 .5h-1.4v-1.5l.1-.1 .4 .1a.41 .41 0 0 0 .5-.3 .41 .41 0 0 0-.4-.5l-.3-.4-.6-.4h-1.3l-.1-.8 .1-.1h.1l.2 .3 .2 .1 1.4 .1a.45 .45 0 0 0 .4-.4l-.1-2-.3-.2-1.4-.1-.2 .2-.2 .3h-.2v-1.7h10.4v.2a.34 .34 0 0 1 .1 .5 .5 .5 0 0 0 .6 .5v.5h1.9l-.1-.5h2.5a.4 .4 0 0 0 .3 .5 .4 .4 0 0 0 .5-.2l.2-.4 .4 .1v-2.1h-.1a.49 .49 0 0 0-.5-.2 .49 .49 0 0 0-.3 .5l-.3 .1v1.4l-.2 .3h-2.5l-.2-.1a.3 .3 0 0 1 0-.6v-.7l-.2-.3h-.8l-.6 .2h-.2a.4 .4 0 0 0-.5 .3h-10.4v-1l1-.1 .2-.3v-.4h.5v.2a.4 .4 0 0 0 .6 .3 .4 .4 0 0 0 .1-.7h1.9l.3 .5 .4 .2v-.8h-.7v.1h-2a.4 .4 0 0 0-.6 .2h-.5v-.4a.45 .45 0 0 0 0-.7 .45 .45 0 0 0-.7 .3l-.3 .2-.2-.1v-2.4l-.1-.2-.7-.1-.1-.2h-2.5v3.1l-.6 .6h-4l-.2 .3 .1 5.9 .3 .2h4.3l.1 .1v.1l-.7 .7v1.2l.6 .7 .1 1.5 .9 .1v.7l.1 .2 .9-.1 .1 .7 .6 .5v.2h-.2v2.2h1.2v-1.1l.1-.1 1.7 1.7h3.1l.3 .2-.1 .2a.35 .35 0 0 1-.6 .1l-.2-.1h-4.2l-.1-.4h-1.2v2.1h.4l.6-.3 .1 1.3-.1 .1-1.6 .5-.1 .2 .1 1.4 .2 .2 1.7 .5h.6l-.1 .7h.7v.5h-.7l.1 .6 .5 .5v.2h-2.8l-.1-.1v-.1a.84 .84 0 0 0 .7-1h-1l-.1-.1v-.1l-.2-.1-.1-.1v-.1h1.4a.79 .79 0 0 0-.9-1v1h-.5v-1l-.4 .1-.2 .2-.2-.1v-2.1l-.1-.2-.2-.1h-1.3l-.2 .1-.1 1.8-.7 .6h-5.2l-.7-.7 .1-.6 .4 .3a3.1 3.1 0 0 0 1.7-.1l.3-.3v-.4h-1v.9h-.4v-1.1h.2v-.2l.1-.1h1.2l.3 .2h2l.3-.1 .1-.2-.1-3 .2-.5h2.4v.2a.59 .59 0 0 0 .9 .4 1.18 1.18 0 0 0 .9 1.3h.4v-2.1l-1.4-.1a.5 .5 0 0 0-.8 .3h-2.4v-.2h-3l.1 .5-.1 .1h-1.4l-.4 .2-.4 .2-.2-.1v-.9l.1-.1 1 .1a.73 .73 0 0 0 .8-.7h-.8v.7h-.6h.1v-.9h.3v-.3h1l-.1-.4 .1-.1h.9l.2 .1a1.11 1.11 0 0 0-.6 1.1h3v-.3a1.28 1.28 0 0 0-.6-.8l.3-.2h3.6v1.3h1.3v-2.2a1.04 1.04 0 0 0-1.3 .9h-3.6l.2-.2v-1.5l-.2-.2-.2-.1h-2.7l-.1-.1 .4-.4v-.4h-1.1l-.1-.1v-.2h-.2v-.1v-.1h1.4v-.2a.79 .79 0 0 0-1-.7v.9h-.4v-.9h-.3a1.06 1.06 0 0 0-.8 .6l-.4-.1-.1 1h-.4l-.1-1 .2-.4v-2.9l.5-.5 .1-.2v-5.5h2.5a.4 .4 0 0 0 .5 .5 .4 .4 0 0 0 .2-.7 .4 .4 0 0 0-.7 .1v.1h-2.5v-.5a.4 .4 0 0 0 0-.7h1.6v.2a.4 .4 0 0 0 .6 .2 .4 .4 0 0 0 0-.6 .4 .4 0 0 0-.6 .2h-1.6a.42 .42 0 0 0-.5 .1 .42 .42 0 0 0-.1 .5h-.1h-1h-.1a.42 .42 0 0 0-.5-.4 .42 .42 0 0 0-.4 .4h-2l-.1-.1v-.4h-2.4l.1 .6-.1 .3v1.3l-.4 .3h-1.4l-.2 .2-.1 .1 .1 3.9-.3 .7h4.7v-.4h.6l.3 .3v3a.18 .18 0 0 1 0 .2 .18 .18 0 0 1-.2 .1v1.9l.6-.1 .3 .4v.3h-1.6l.2-.3v-1h-.8l.2 .6-.5 .6-1 .1-.7-.2h-.6l-.4 .2v.9l.1 .2 .2 .1h.8l.6-.6h.6l.1 .3-.3 .5h.5v.4h-.5a.45 .45 0 0 0-.3 .7 .45 .45 0 0 0 .7 .1h2.5l.3 .3h.4v-.3h.4v.3h.5h.1v2h-.1l-.4-.2h-1.1l-.2 .2v1l.2 .2h1.1l.4-.2h.1v4.9l.1 .2 .2 .1h9.9a.2 .2 0 0 1 .2-.1 .2 .2 0 0 1 .2 .1l.4 .3v.2h-11.4l-.1-.1a.52 .52 0 0 0 .1-.8 .52 .52 0 0 0-.8 0 .52 .52 0 0 0 .1 .7l-.1 .2h-2.1l-.1-.1v-.1a3.4 3.4 0 0 0 1.7-2.8h.4v.2a.5 .5 0 0 0 .8 .3 .5 .5 0 0 0 0-.8 .5 .5 0 0 0-.8 .3h-.4h.1a3.4 3.4 0 0 0-3-3.6v-.1l.3-.2 .1-.2v-.7l-.2-.3a.41 .41 0 0 0-.4-.5 .41 .41 0 0 0-.4 .4l-.4 .5v.6l.3 .3v.2a3.9 3.9 0 0 0-2.8 1.8l-.1-.1v-2.8h.8v.6l.2 .3h.9l.3-.3v-.6l-.3-.7 .7-.2 .2-.4v-.7l-.1-.2-.2-.1-.6-.1a.46 .46 0 0 0-.4 .6l-.4 1.1-.3 .7h-.8v-5.7h5.3v-.7a.73 .73 0 0 0-.8 .7h-4.5v-3.3h.4l.2 .4 .3 .3a3.1 3.1 0 0 0 1.7-.1l.2-.2 .3 .3a3.1 3.1 0 0 0 1.7-.1l.3-.3v-.4h-1v.8h-.5v-.8h-1.7v.8h-.5v-.8h-1v.1h-.4v-8.6h2.7v.1h2.4a.78 .78 0 0 0-1-.8v.8h-.5v-.8h-.3l-.3 .1-.3 .3v.3h-2.7v-2h3.2l.2 .4a2.82 2.82 0 0 0 1.6 0l.1-.3v-.3h-.7v.7h-.5v-.7h-.7v.2h-3.2v-1h3.2v.3h1.9v-.5l-.4-.3h-.3v.8h-.5v-.8l-.5 .1-.2 .4h-3.2v-1.5h1.1a.5 .5 0 0 0 .7 .6 .5 .5 0 0 0 .3-.8h3.3l.2 .4 .3 .3-.2 .4v.7l.3 .6a.42 .42 0 0 0 .5 .5 .42 .42 0 0 0 .3-.6l.3-.5v-.7l-.2-.4 .3-.3 .2-.4h.3l.1 .4 .3 .3-.1 .4v.7l.3 .6a.42 .42 0 0 0 .4 .5 .42 .42 0 0 0 .3-.6l.3-.5v-.7l-.1-.4 .3-.3 .1-.4h.3l.2 .4 .3 .3-.2 .4v.7l.3 .6a.42 .42 0 0 0 .5 .5 .42 .42 0 0 0 .3-.6l.3-.5v-.7l-.2-.4 .3-.3 .2-.4h.3l.1 .4 .3 .3-.1 .4v.7l.3 .6a.42 .42 0 0 0 .4 .5 .42 .42 0 0 0 .3-.6l.3-.5v-.7l-.1-.4 .4-.4v-.4h-1.9v.1h-.3v-.1h-2v.1h-.3v-.1l-7.5 .1a.5 .5 0 0 0-.6-.2 .5 .5 0 0 0-.4 .4h-1.1v-.6v-.2l.2 .1a.52 .52 0 0 0 .7 .2 .52 .52 0 0 0 .2-.7l.2-.1a3.4 3.4 0 0 0 2.7 .4h1.4v.1h2v-.1h.3v.1h1.9v-.1h.3v.1h2v-.1h.3v.1h1.9v-.1a.73 .73 0 0 0-.7-.6v.7h-.5v-.7l-.4 .1-.3 .5h-.3a.73 .73 0 0 0-.7-.6v.7h-.6v-.7l-.4 .1-.3 .5h-.3a.73 .73 0 0 0-.7-.6v.7h-.5v-.7l-.4 .1-.3 .5h-.3a.73 .73 0 0 0-.8-.6v.7h-.4v-.7l-.5 .1-.3 .5h-1.4a3.4 3.4 0 0 0 2.5-3.8h2.4v1.7l.2 .2 1.1-.1 .1-.1 .1-.3 .4-.3h.5l.3 .2h1.1l.7 .4h.7l.3-.2v-.7h.5v.6l.2 .3h.8l.3-.2 .1-.7 .4-.2v.7l.3 .5-.3 .5 .1 1-.9 .8-.5 .3a.5 .5 0 0 0-.1 .8 .5 .5 0 0 0 .8-.2l.2-.4 .3-.2 .2 .6 .2 .1 1.2 .3a.14 .14 0 0 1 .2 .1 .14 .14 0 0 1-.1 .2l-.1 .4h2.5l-.1-.3-.2-.2-.1-1a.2 .2 0 0 1-.1-.2 .2 .2 0 0 1 .2-.2v-.7l-.1-.2h-2.2v-1l-.3-.6 .1-.1h1.2v.7a.45 .45 0 0 0 .4 .4h.9l.6-.6 .7-.2 .1 .6 .3 .6v.9l1.4 1.4h.2a.29 .29 0 0 1 0 .5v1l.2 .4v.8l.2 .1h.6l.5 .1 .1 .2a.43 .43 0 0 0 .1 .4 .43 .43 0 0 0 .5 .1l.1 .1-.1 .3h.9l.1 .1v.1l.2 .1v1l.6-.1a.86 .86 0 0 0 .9 .5h.9l.5-.2 .5 .2h.4v-.8h-1.8v.8h-.5v-.9l.1-.1h.2v-.2l.1-.1h2.1v.3h.3v1h.3a1.08 1.08 0 0 0 .7-.5l.4 .1h.6a.73 .73 0 0 0 .7-.8h-.7v.8h-.5v-1h.3v-.3h.9l.1-1.2h.6v1.7l.1 .2h1.9l.1-.2v-1h.5a1.05 1.05 0 0 0 1.3 1.2 1.05 1.05 0 0 0 .6-1.7h.7l.1 .4 .5 .3h.8l.4-.2a.9 .9 0 0 0 .9 .4h.8a.75 .75 0 0 0 .7-.8h-1v.8h-.5v-.8h-1l-.1-.2h-.4v.8h-.5v-.8l-1.4 .1a1.05 1.05 0 0 0-1.2-.4 1.05 1.05 0 0 0-.7 .9h-.5v-.7l-.1-.2h-1.8l-.2 .2h-.6v-2.1l3.1 .1 .4-.1 .1 1 .1 .2 1.4 .1a.55 .55 0 0 0 .6 .1l.1 .3h1.9l.2 .2h2.1l-.1-.6h.9l.2 .3v4.6l.3 .2 .9 .1a.63 .63 0 0 0 .7 .8l.9-.1 .3-.1 .1-.2v-.3h-.8v.7h-.5v-.8l.1-.1h.2l.1-.3h.4l.9 .3h.8a.63 .63 0 0 1 .1 .9l.1 .1a.3 .3 0 0 1-.1 .5l.1 .2a.26 .26 0 0 1 0 .4v.3l-.2 .1h-1.3l-.1-.1-.1-.7-.1-.1h-1.2l-.1 .1v.3h-.1l-.4-.2-.3-.1v.8h.7l.3 .2 .2 .2-.2 .3-.2 .1v-.3h-2v.3l.2 .3-.3 .3-.1-.1 .1-.5-.2-.2v-.4l-.1-.3 1.1 .1v-.8a.73 .73 0 0 0-.7 .7h-.4l-.2-.3 .1-.4a.44 .44 0 0 0 .6-.3 .44 .44 0 0 0-.4-.5v-.9a1.37 1.37 0 0 1-.3-1l-.4-.2a.95 .95 0 0 0-.2-.8 .43 .43 0 0 0 .3-.5 .43 .43 0 0 0-.5-.3 .43 .43 0 0 0-.3 .4l-.5 .5a.44 .44 0 0 0-.7 0 .44 .44 0 0 0 .1 .6l-.1 .2-.6 .1-.7-.9a.42 .42 0 0 0-.7 0 .42 .42 0 0 0 .2 .6l-.1 .2h-.4l-.3-.2-.3-.1v2.1a.24 .24 0 0 1-.3 .3l-.4 .5h-.8l-.2 .1v1.3l.2 .1 .3 .1 .5 .2a.35 .35 0 0 1-.4 .4 .66 .66 0 0 0-.3 .6l-.1 .1h-.7l-.4-.4-.1-.3 .4-.4 .1-.4h-2l.1 .6a.64 .64 0 0 0-.5 .5h-1.3l-.1-.1a.42 .42 0 0 0-.4-.5 .42 .42 0 0 0-.4 .5 .42 .42 0 0 0 .5 .3l.1 .2-.2 .1-.5 .4-.6-.2v.7h.8a.6 .6 0 0 0 .6-.2l.6 .2 .9 1v.1a.4 .4 0 0 0 .2 .7l.5 .3h.4l.1 .4-.1 .2h-.4l-.2 .1-.6-.1v1l-.3 .1v.2h-.1h-1.1l.1 .4a.35 .35 0 0 1-.5 .1l-.4 .1h-.1v-.9l-.1-.3h1v.1h1v-.8a.79 .79 0 0 0-1 .7h-1l-.2-.3 .3-.7v-.7l-.1-.4a.85 .85 0 0 0 .4-.8h-1.9v.4l.3 .2a.3 .3 0 0 1 0 .6v.7l.3 .6-.3 .6a.2 .2 0 0 1-.2 .3l-.8-.9v-3.1l1.4 .1v-.7a.73 .73 0 0 0-.7 .6h-.7v-2.1v-.2l.2 .1a1.05 1.05 0 0 0 1.1 .2 1.05 1.05 0 0 0 .7-.9v-.6h1.2a.73 .73 0 0 0 .7 .7v-.8h.5v.8l.3-.1 .3-.2a.13 .13 0 0 1 .1-.1 .13 .13 0 0 1 .1 .1v.2h2v-.1a.73 .73 0 0 0-.8-.7v.8h-.5v-.8l-.3 .1-.2 .2a.13 .13 0 0 1-.2 .1 .13 .13 0 0 1-.1-.1v-.2h-1.9v.1h-1.2v-.1a1.1 1.1 0 0 0-1.9-.7l-.1-.1a.42 .42 0 0 0-.2-.7 .42 .42 0 0 0-.5 .4l-.1 .1-.5-.2v1h-.6v-1a1.66 1.66 0 0 0-1.1 1l-.1-.1a1.05 1.05 0 0 0-1.1-.6 1.05 1.05 0 0 0-1 .9l.1 .9a1.19 1.19 0 0 0 1.3 .8 .93 .93 0 0 0 .8 .9 .93 .93 0 0 0 1-.7h.1v-1h.6v1l.6-.3 .1 .1v5.2l1.8 1.9-.2 .4v.6l.1 .3 .2 .1h.7l.6-.3 .4-.1 .9 .6 2.5-.1v.4l-.7 .2-.1 .2-.1 .9a.36 .36 0 0 1-.1 .6l-.2 .5h.9h.1v.2l.2 .1v1l.6-.2 .1 .1v4.5h2l.3 .1 .3-.1 .3 .1 .5-.1 .7 .1 .2-.1 .4 .1 2.4-.1v-.3h1.2a.5 .5 0 0 0 .7 .6 .5 .5 0 0 0 .2-.8 .5 .5 0 0 0-.9 .1v.1h-1.2v-2h1.2a.5 .5 0 0 0 .7 .6 .5 .5 0 0 0 .2-.8 .5 .5 0 0 0-.9 .1v.1h-1.2v-3.9h-.2a.13 .13 0 0 1-.1-.2 .13 .13 0 0 1 .1-.1h1.3v.6l.2 .3 .8 .1 .4-.2 .3 .3a1.23 1.23 0 0 0 1 .2 .73 .73 0 0 0 .8-.7h-.8v.7h-.6h.1v-.9l.2-.1 .1-.2h1a.87 .87 0 0 0-.9-.8v-.2l.2-.1a.45 .45 0 0 0 .5-.4v-.6h.4v.8l.8 .8a.41 .41 0 0 0 .7 .2 .41 .41 0 0 0-.3-.7l.1-.5v-.6l-.2-.3-.8-.1-.2 .1-.1 .3h-.4l-.3-.3-.7-.1a.45 .45 0 0 0-.4 .5 1.98 1.98 0 0 1-1.5 1.5l-.3 .1-.1 .3h-1.3l.2-.1v-.5a.43 .43 0 0 0 .7 0 .43 .43 0 0 0-.1-.7l-.5 .1-.1-.1v-.5l.1-.2h1.6h.2l.2-.4a.46 .46 0 0 0 .6-.1 .46 .46 0 0 0 0-.6l.1-.2h.2a.46 .46 0 0 0 .4 .5h.6l.6-.3 .5 .3 .8-.1 .2-.3v-.8l-.4-.2h-.6l-.5 .3-.6-.3h-.6l-.3 .2-.1 .7h-.2l-.3-.5a.44 .44 0 0 0-.5-.4v-.8h2a.74 .74 0 0 0 .6 .6 .74 .74 0 0 0 .8-.4 .52 .52 0 0 0 .7-.1 .52 .52 0 0 0-.1-.7 .52 .52 0 0 0-.8 .1h-.1a.68 .68 0 0 0-.7-.1 .68 .68 0 0 0-.4 .6h-2v-1.5h2.9a.4 .4 0 0 0 .5 .4 .4 .4 0 0 0 .2-.6 .4 .4 0 0 0-.6 .1l-.1 .1h-2.9v-.2l.3-.5-2.5 .1a.51 .51 0 0 0-.2 .7l-.1 .3a.43 .43 0 0 0-.2 .5 .43 .43 0 0 0 .5 .3v.2a.5 .5 0 0 0-.1 .8 .43 .43 0 0 0-.2 .6 .43 .43 0 0 0 .5 .2l.1 .4v.4a.31 .31 0 0 1-.5 .1l-.1 .1a.45 .45 0 0 1-.7 .1 .54 .54 0 0 0-.9 .1h-.1a.42 .42 0 0 0-.6-.3 .42 .42 0 0 0-.1 .7l-.2 .1h-.5l-.4-.1-.1-.1a.42 .42 0 0 0-.5-.5 .42 .42 0 0 0-.3 .6l-.2 .1h-1l-.1 .1-.1 .5h-.5l-.1-.2 .2-.5a.38 .38 0 0 0 .4-.4l.2-.4h-1.1h-.1v-.2l2.5-.1 1.2-1 .6 .5 .8 .2a.4 .4 0 0 0 .6-.4 .4 .4 0 0 0-.6-.4l-.5 .1-.8-.8-.1-.2h.1h1.7a.43 .43 0 0 0 .4-.6 .43 .43 0 0 0-.7 0h-1.6l.1-1.4 .1-.1a.4 .4 0 0 0 .6-.2l.1-.3a.61 .61 0 0 0 .2-.6l.5-.1h1.8l.2-.1 .3 .3-.4 .6h2.5l-.1-.2 .6-.6 .5 .7h.7l.2-.1 .2-.3v-.6l-.3-.3-.7-.3v-.2h.6l.5-.3 .6 .4h.7l.2-.1 .1 .2a.62 .62 0 0 0 .1 .7 .46 .46 0 0 0-.1 .5l-.1 .1a.41 .41 0 0 0-.5 .5 .41 .41 0 0 0 .6 .3 .41 .41 0 0 0 .2-.6l.1-.1a.43 .43 0 0 0 .4-.2 .43 .43 0 0 0-.1-.5v-.2a.4 .4 0 0 0 .1-.5l.1-.3-.1-.9 .1-.5h.7l.8-.4 .4-.1 .1-.9-.2-.2-1.1 .1-.1 .1-.1 .7-.1 .1h-.4l-.1-.4a.34 .34 0 0 1 .1-.5l-.1-.2a.34 .34 0 0 1 .1-.5l-.2-.5h.5l.3 .4 .5 .1v-.7h-.8v.2h-.5a.62 .62 0 0 0-.1-.8h.6v.1h.8v-.6l-.5 .1-.3 .4h-.5l-.1-7.1-.3-.2h-7l-.3 .2h-.5v-.7l1.1-.5a.18 .18 0 0 1 .2 0 .18 .18 0 0 1 .1 .2l.2 .2h.4l.2 .2 .3 .1 .7 .1a.74 .74 0 0 0 .7-.8h-.7v.8h-.5v-1.3h1.2a.74 .74 0 0 0-.7-.7v.7h-.5v-.7a.94 .94 0 0 0-.8 .8l-.7 .1v-.6l-.4-.4 .4-.6v-.7l-.4-.3h-.8v-.7l-.2-.2h2.9v.1a.5 .5 0 0 0 .8 .4 .5 .5 0 0 0 0-.9 .5 .5 0 0 0-.8 .4l-14.8-.1-.3 .2-.1 .3-.1 .1-.5-.5a.52 .52 0 0 0-.8 .2h-1.6l-.2 .4v.7l.2 .3h.8l.2-.1 .4-.5h.2a.72 .72 0 0 0 .5 .8l.9-.1 .1 .3-.2 .1-.8-.1-.4 .3v.7l.4 .5-.4 .5v.6l.1 .3-.1 .1h-2.1l-.4 .1-.1-.5a.2 .2 0 0 1-.2-.2 .2 .2 0 0 1 .2-.2v-.8l-.1-.1h-.4l-.1-.2 .4-.8h.9v.7l.3 .7a.42 .42 0 0 0 .4 .5 .42 .42 0 0 0 .4-.6l.2-.6v-.7l-.1-.2-.2-.1h-.7l-.2 .1-.1 .2h-.9v-.7a.36 .36 0 0 1 .1-.6l.2-.5h-2l.1 .3 .4 .4-.2 .4v.7l.4 .8-.2 .2h-.4l-.1 .1v.8l.2 .3-.4 .2-1-1a1.37 1.37 0 0 1 .3-1.2l.1-.8-.3-.4v-.1a.81 .81 0 0 0 .6-.8h-2l.1 .3 .2 .3-.1 .2a.52 .52 0 0 0-.6 .2l-.7-.2h-.8l-.2 .1-.2 .3h-1.2l.2-.3v-.7l-.3-.4v-.1l.4-.3 .2-.3h.5v.3l.2 .2a1.26 1.26 0 0 0 1 .2l.4-.1 .3-.2h3.1v.1h2v-.1a.73 .73 0 0 0-.8-.7v.8h-.4v-.8l-.5 .1-.3 .6h-.5a.73 .73 0 0 0-.8-.7v.7h-.5v-.7l-.4 .1-.3 .6h-.6l.1-.5h-.8v.8h-.5h.1v-.8l-1.3 .1v-.2h-2l.1 .6-.8 .2-.7 .4-.1 .3h-.5l-.1-.3-.2-.1h-.8a1.49 1.49 0 0 1-1.6 .4l-.2-.3h-.8l-.3-.2-.1-.3-.1-.2h-1.1l-.2 .2h-2.4l-.1-.6h.5l.1 .3a2.82 2.82 0 0 0 1.6 .1l.3-.3v-.7h-.7v1.1h-.6v-1.1h-.7v.6h-.5a4 4 0 0 0-1.7-1.9z"/>
<path d="M134 109.2h6.6l.2 .1-.1 .6h.7v.5h-.7a1.26 1.26 0 0 0 .6 1.2l-.1 .1h-7.7l-.1-.1a1.36 1.36 0 0 0 .6-1.2h-.7v-.5h.7z"/>
</g>
<path d="M141.4 78.7l-.4 .6M130.8 89h.7M136 87.8h1.5" fill="none" stroke="#f2eda1" stroke-width=".15"/>
<g fill="#f2eda1">
<path d="M120.1 78.4h2.1v1.1h-2.1v-.9h.1v.8h.5l-.1-.1h-.3v-.3h.3l-.1-.1h-.2v-.3h.5l.3 .4-.3 .3 .1 .1 .3-.3 .2 .3h.1l-.3-.4 .3-.5 .3 .1v.8h.1v-.8h.2v-.1h-.7l-.2 .4-.3-.4-.8 .1z"/>
<path d="M135 107.6a.35 .35 0 0 1 .4-.1 .35 .35 0 0 1 .2 .3v.4h-.3v-.4a.1 .1 0 0 0-.1-.1 .1 .1 0 0 0-.1 .1 .11 .11 0 0 0 .2 .1v.3a.35 .35 0 0 1-.4-.2 .35 .35 0 0 1 .1-.4z"/>
<path d="M135.8 107.6l.3-.1v.2h-.1a.1 .1 0 0 0 0 .1 .1 .1 0 0 0 .1 .1 .1 .1 0 0 0 0-.1v-.6h.3v.6a.36 .36 0 0 1-.5 .3 .36 .36 0 0 1-.1-.5z"/>
<path d="M136.9 107.6a.35 .35 0 0 1 .4-.1 .35 .35 0 0 1 .3 .3v.4h-.3v-.4a.1 .1 0 0 0-.1-.1 .1 .1 0 0 0-.1 .1 .11 .11 0 0 0 .2 .1v.3a.35 .35 0 0 1-.4-.2 .35 .35 0 0 1 0-.4z"/>
<path d="M137.8 107.6l.3-.1v.2l-.1 .1a.32 .32 0 0 1-.4 .4v-.3h.2z"/>
<path d="M138.2 107.2h.2v.3h.2v.2h-.2l.2 .2v.3l-.4-.2z"/>
<path d="M138.8 107.5h.3l-.2 .7h-.2z"/>
<path d="M139.2 107.6a.35 .35 0 0 1 .4-.1 .35 .35 0 0 1 .2 .3v.4h-.3v-.4a.1 .1 0 0 0-.1-.1 .1 .1 0 0 0 0 .1 .1 .1 0 0 0 .1 .1v.3a.35 .35 0 0 1-.4-.2 .35 .35 0 0 1 .1-.4z"/>
<path d="M134.2 109.2a.36 .36 0 0 1 .6 .2 .36 .36 0 0 1-.4 .4v-.2h.1a.1 .1 0 0 0 .1-.1 .11 .11 0 0 0-.2-.1 .1 .1 0 0 0 0 .1v.6h-.3v-.7z"/>
<path d="M135 109.2a.35 .35 0 0 1 .4 0 .35 .35 0 0 1 .2 .3h-.4v-.1h.2a.12 .12 0 0 0-.2 0 .12 .12 0 0 0 0 .2 .12 .12 0 0 0 .2 0l.1 .2a.36 .36 0 0 1-.5-.1 .36 .36 0 0 1 0-.5z"/>
<path d="M135.8 109.2l.3-.1-.1 .7h-.3z"/>
<path d="M136.6 109.2a.35 .35 0 0 1 .4 0 .35 .35 0 0 1 .2 .3v.3h-.3v-.3a.1 .1 0 0 0-.1-.1 .1 .1 0 0 0 0 .1 .1 .1 0 0 0 .1 .1v.2a.35 .35 0 0 1-.4-.1 .35 .35 0 0 1 .1-.5z"/>
<path d="M137.5 109.2h.3v.2l-.1 .1a.32 .32 0 0 1-.4 .3v-.2l.1-.1z"/>
<path d="M138 109.2a.36 .36 0 0 1 .5 .2 .36 .36 0 0 1-.4 .4v-.2h.1a.1 .1 0 0 0 .1-.1 .1 .1 0 0 0-.1-.1 .1 .1 0 0 0-.1 .1v.6h-.3v-.7z"/>
<path d="M138.7 109.2a.35 .35 0 0 1 .4 0 .35 .35 0 0 1 .2 .3h-.4l.1-.1h.1a.12 .12 0 0 0-.2 0 .12 .12 0 0 0 0 .2 .12 .12 0 0 0 .2 0l.1 .2a.36 .36 0 0 1-.5-.1 .36 .36 0 0 1 0-.5z"/>
<path d="M139.5 109.2l.3-.1-.1 .7h-.3z"/>
<path d="M140 109.2a.35 .35 0 0 1 .4 0 .35 .35 0 0 1 .2 .3v.3h-.3v-.3a.1 .1 0 0 0-.1-.1 .1 .1 0 0 0-.1 .1 .11 .11 0 0 0 .2 .1v.2a.35 .35 0 0 1-.4-.1 .35 .35 0 0 1 .1-.5z"/>
<path d="M118.8 94.4a.43 .43 0 0 1 .7 .1 .43 .43 0 0 1-.3 .6 .43 .43 0 0 1-.5-.4h.3a.12 .12 0 0 0 .1 .1 .12 .12 0 0 0 .1-.2 .12 .12 0 0 0-.2 0l-.3 .1z"/>
<path d="M119.7 94.4a.43 .43 0 0 1 .7 .1 .43 .43 0 0 1-.3 .6 .43 .43 0 0 1-.5-.4h.3a.12 .12 0 0 0 .2 .1 .12 .12 0 0 0 0-.2 .12 .12 0 0 0-.2 0l-.3 .1z"/>
<path d="M120.7 94.4a.43 .43 0 0 1 .7 .2 .43 .43 0 0 1-.5 .5v-.3a.13 .13 0 0 0 .2-.1 .14 .14 0 0 0-.2-.2 .13 .13 0 0 0 0 .2v.7h-.3v-.8z"/>
<path d="M121.7 94.4l.4-.1v.3l-.1 .1a.41 .41 0 0 1-.5 .4v-.3l.1-.1z"/>
<circle cx="122.4" cy="94.9" r=".2"/>
<circle cx="123" cy="94.9" r=".2"/>
<circle cx="123.7" cy="94.9" r=".2"/>
</g>
<path d="M154.5 88.3h.5M154.5 87.7l.3-.2v.8" fill="none" stroke="#f2eda1" stroke-width=".13"/>
<g fill="#f2eda1">
<path d="M118 78.6l.2 .1 .1 .2h-.3z"/>
<path d="M116.1 78.4h2.4v1.1h-2.4v-.9h.1v.6l.2 .2 .4-.1v-.6h.2l.1 .2 .4 .2-.1 .2h-.4l.2 .1h.3l.1-.2-.1-.2-.3-.2 .1-.2 .3 .1v-.1h.2l.1 .8 .1-.4 .3 .4h.1l-.2-.4 .2-.2v-.2l-.2-.1h-1l-.2 .2h-.2l-.1-.2v.7l-.2 .1-.1-.1-.1-.7-.2 .1z"/>
<path d="M141.7 76.3a.3 .3 0 0 1 .5 0 .3 .3 0 0 1-.2 .5v-.4l-.1 .6h-.2z"/>
<path d="M142.4 76.5l.4-.1 .1 .2 .1 .2h-.4v-.1h.1a.11 .11 0 0 0-.1 0 .11 .11 0 0 0 0 .1 .11 .11 0 0 0 .1 0l.2 .2a.32 .32 0 0 1-.5 0 .32 .32 0 0 1 0-.5z"/>
<path d="M143.1 76.5l.3-.1-.1 .6h-.2z"/>
<path d="M143.5 76.4h.2v.6h-.2z"/>
<path d="M143.9 76.5a.32 .32 0 0 1 .6 .1 .32 .32 0 0 1-.4 .5v-.3l.1-.1-.1-.1v.1v.6h-.3v-.6z"/>
<path d="M144.6 76.2h.2v.3l.2-.1 .1 .1v.5h-.2l-.1-.3v.3h-.2z"/>
<path d="M145.3 76.5l.4-.1 .1 .2v.2h-.3v-.1h.1a.11 .11 0 0 0-.1 0 .11 .11 0 0 0 0 .1 .11 .11 0 0 0 .1 0l.1 .2a.32 .32 0 0 1-.4 0 .32 .32 0 0 1 0-.5z"/>
<path d="M146 76.5l.3-.1-.1 .6h-.3z"/>
<path d="M146.4 76.5l.2-.1a.31 .31 0 0 1 .4 .3v.3h-.3v-.3h-.1v.1h.1l-.1 .3a.32 .32 0 0 1-.3-.2 .32 .32 0 0 1 .1-.4z"/>
<path d="M147.1 76.2h.2v.8h-.2z"/>
<path d="M147.9 76.3l.3-.1v.2l-.1 .1a.36 .36 0 0 1 0 .4 .36 .36 0 0 1-.4 .1v-.2h.2l-.1-.3z"/>
<path d="M148.4 76.3a.44 .44 0 0 1 .7 .1 .44 .44 0 0 1-.3 .7 .44 .44 0 0 1-.5-.5h.2a.19 .19 0 0 0 .3 .2 .19 .19 0 0 0 0-.3 .19 .19 0 0 0-.3 .1h-.2z"/>
<path d="M149.3 76.3l.2-.1a.16 .16 0 0 0 .2 .1 .16 .16 0 0 0 .1-.1l.3 .1v.7h-.2l-.1-.6v.6h-.2l-.1-.6v.6h-.3z"/>
<path d="M150.6 76.2h.4l.2 .1v.2l-.1 .2 .2 .3h-.3l-.1-.2v-.2l.1-.1-.1-.1-.1 .6h-.2z"/>
<path d="M151.4 76.5l.3-.1 .2 .2v.2h-.3v-.1h.1a.11 .11 0 0 0-.1 0 .11 .11 0 0 0-.1 .1 .11 .11 0 0 0 .2 0l.1 .2a.32 .32 0 0 1-.4 0 .32 .32 0 0 1 0-.5z"/>
<path d="M151.9 76.4h.2l.1 .2 .1-.2h.2l-.3 .7z"/>
<path d="M152.8 76.2h.3a.22 .22 0 0 1 .3 .1 .22 .22 0 0 1-.1 .3l.2 .1-.1 .3h-.3v-.2h.1l-.1-.1 .1-.2-.1-.1v.6h-.3z"/>
<circle cx="143.6" cy="76.3" r=".11"/>
</g>
<path d="M114.8 95.6h-.4v.4l.3-.1 .1 .4-.1 .1-.3-.1" fill="none" stroke="#f2eda1" stroke-width=".13"/>
<g fill="#f2eda1">
<path d="M134.3 88.4h2.2v1.1h-2.2v-.6h.1v.3l.2 .2 .2 .1 .2-.2a.35 .35 0 0 1-.5-.2 .35 .35 0 0 1 .3-.4h.1v-.1h.3v.9l.5-.1v-.1h-.4v-.7h.6v.9l.1-.1v-.4l.3 .4h.1l-.3-.5 .3-.3v-.1l-.4 .4-.1-.4h-1.2l-.4 .4z"/>
<path d="M125.8 82.3a.39 .39 0 0 1 0 .6 .48 .48 0 0 1 0-.6z"/>
<path d="M125.6 81a.34 .34 0 0 1 .4 .3 .34 .34 0 0 1-.4 .4z"/>
<path d="M123.9 80.8h2.3v2.4h-2.3v-.2l.2 .1 .5-.1-.4-.1h.6l.1 .2 .1-.2h.2l.1 .2 .1-.1-.1-.1h-1.1l.4-.4h1v.4l.2 .2 .2-.1 .1-.3v-.4l-.2-.1h-.2l-.1 .3h-1l-.1-.3-.3-.1-.2 .2h.4l.1 .2-.6 .5v-2.1h.2l.1 .9 .4-.1h-.4v-.8h.6v.9l.5-.1h-.1h-.3v-.3l.3-.1-.1-.1h-.2v-.2l.6-.1v.9l.4-.1 .2-.3-.1-.4-.2-.1h-1.9z"/>
<path d="M138.6 74.8h.4l.2 .1v.2l-.1 .2 .2 .3h-.3l-.1-.2v-.2l.1-.1-.1-.1-.1 .6h-.2z"/>
<path d="M139.4 75.1l.1-.1a.31 .31 0 0 1 .4 .3v.3h-.2v-.3h-.2v.1h.2l-.1 .3a.32 .32 0 0 1-.3-.2 .32 .32 0 0 1 .1-.4z"/>
<path d="M139.9 75h.3v.2l.1-.2h.2l-.3 .7z"/>
<path d="M140.5 75h.3v.6h-.3z"/>
<path d="M141.3 74.9l.3-.1v.2l-.1 .1a.36 .36 0 0 1 .1 .4 .36 .36 0 0 1-.4 .1v-.2h.1l-.1-.3z"/>
<path d="M141.7 74.8h.3v.3l.1-.1 .2 .1v.5h-.2l-.1-.3v.3h-.3z"/>
<path d="M142.5 75.1l.1-.1a.31 .31 0 0 1 .4 .3v.3h-.2v-.3h-.2v.1h.2l-.1 .3a.32 .32 0 0 1-.3-.2 .32 .32 0 0 1 .1-.4z"/>
<path d="M143.2 74.8h.2v.3l.1-.1 .2 .1v.5h-.2l-.1-.3v.3h-.2z"/>
<path d="M144.3 74.9l.3-.1 .1 .1 .1 .2-.3-.1 .2 .3h.1v.2l.1 .1-.5 .1-.1-.2-.1-.1h.3v-.1l-.3 .1z"/>
<path d="M145.4 74.8h.3v.5l.1 .1-.1 .2a.27 .27 0 0 1-.3-.3z"/>
<path d="M145.9 75.1l.2-.1a.31 .31 0 0 1 .3 .3v.3h-.2v-.3h-.1v.1h.1l-.1 .3a.32 .32 0 0 1-.3-.2 .32 .32 0 0 1 .1-.4z"/>
<path d="M146.6 74.8h.2v.8h-.2z"/>
<path d="M146.9 75h.3l-.1 .3 .1 .3h-.2l-.2-.4z"/>
<path d="M147.4 75.1l.2-.1v.4a.29 .29 0 0 1-.4 .3v-.3h.1z"/>
<path d="M147.7 74.8h.3v.3l.1-.1 .1 .1 .1 .5h-.3v-.3v.3h-.3z"/>
<path d="M148.5 75.1l.1-.1a.31 .31 0 0 1 .4 .3v.3h-.2v-.3h-.2v.1h.1v.3a.32 .32 0 0 1-.3-.2 .32 .32 0 0 1 .1-.4z"/>
<path d="M149.1 75h.3v.4v-.4h.3v.7l-.2 .2h-.3v-.2h.2v-.1h-.1l-.1-.1z"/>
<path d="M150.2 74.9l.2-.1h.3v.3a.21 .21 0 0 0-.4 .1 .19 .19 0 0 0 .3 .2h-.1v-.2h.2a.35 .35 0 0 1-.3 .5 .35 .35 0 0 1-.3-.5z"/>
<path d="M150.9 75h.2l.1 .4v-.4h.2v.4a.27 .27 0 0 1-.2 .3 .27 .27 0 0 1-.3-.3z"/>
<path d="M151.7 75.1a.32 .32 0 0 1 .5 .1 .32 .32 0 0 1-.4 .5v-.3l.2-.1-.1-.1-.1 .1v.6h-.2v-.6z"/>
<path d="M152.3 74.8h.2v.2h.1v.3h-.1l.1 .1v.3l-.3-.2z"/>
<path d="M152.8 75.1l.1-.1a.31 .31 0 0 1 .4 .3v.3h-.2v-.3h-.1v.1h.1l-.1 .3a.32 .32 0 0 1-.3-.2 .32 .32 0 0 1 .1-.4z"/>
<path d="M153.9 74.9l.2-.1 .2 .1 .1 .2-.2 .3h.2v.2h-.6l.3-.5-.1-.1-.1 .3-.1-.2z"/>
<path d="M154.6 74.9l.1-.1a.35 .35 0 0 1 .4 .1 .35 .35 0 0 1 0 .4 .3 .3 0 0 1-.3 .4 .3 .3 0 0 1-.3-.4v-.2h.2v.3h.1v-.4l-.3 .1z"/>
<path d="M155.3 74.9l.3-.1 .1 .1 .1 .2-.1 .3h.1v.2h-.5l.2-.5v-.1l-.2 .3-.1-.2z"/>
<path d="M156.1 74.8h.3v.2l-.2 .1a.3 .3 0 0 1 .2 .4 .3 .3 0 0 1-.4 .1v-.2a.14 .14 0 0 0 .2 0 .14 .14 0 0 0 0-.2 .14 .14 0 0 0-.2 0z"/>
<path d="M147.3 95.8h.3v.4l.1-.4h.2v.7l-.2 .3h-.3v-.2h.2l.1-.2-.2 .1-.1-.1z"/>
<path d="M148.1 95.9a.36 .36 0 0 1 .6 .1 .36 .36 0 0 1-.2 .5 .36 .36 0 0 1-.5-.3h.3a.1 .1 0 0 0 .1 0 .1 .1 0 0 0 .1-.1 .1 .1 0 0 0-.2 0l-.3 .1z"/>
<path d="M148.9 95.8h.2l.1 .5v-.5h.3v.4a.3 .3 0 0 1-.4 .3 .3 .3 0 0 1-.2-.3z"/>
<path d="M149.6 95.6h.2v.3h-.2z"/>
<path d="M149.8 95.8h.3l.1 .2v-.2h.3l-.3 .7z"/>
<path d="M150.6 95.9a.35 .35 0 0 1 .4-.1 .35 .35 0 0 1 .2 .4h-.4v-.1h.1a.12 .12 0 0 0-.1 0 .12 .12 0 0 0-.1 .1 .12 .12 0 0 0 .2 0l.1 .2a.36 .36 0 0 1-.4 0 .36 .36 0 0 1 0-.5z"/>
<path d="M147.2 97.5h.2l.1 .2 .1-.2h.2l-.3 .7z"/>
<path d="M147.9 97.6a.36 .36 0 0 1 .6 .1 .36 .36 0 0 1-.2 .5 .36 .36 0 0 1-.5-.4h.3a.1 .1 0 0 0 .1 .1 .1 .1 0 0 0 .1-.1 .1 .1 0 0 0-.2 0h-.3z"/>
<path d="M148.6 97.5h.3v.7h-.3z"/>
<path d="M149.1 97.6l.3-.1v.3v-.1a.11 .11 0 0 0-.1 .2 .1 .1 0 0 0 .1 0 .1 .1 0 0 0 .1-.1v-.6h.2v.6a.36 .36 0 0 1-.5 .4 .36 .36 0 0 1-.1-.6z"/>
<path d="M149.9 97.6a.35 .35 0 0 1 .4-.1 .35 .35 0 0 1 .2 .4h-.4v-.2h.2a.12 .12 0 0 0-.2 0 .12 .12 0 0 0 0 .2 .12 .12 0 0 0 .2 0l.1 .2a.36 .36 0 0 1-.5 0 .36 .36 0 0 1 0-.5z"/>
<path d="M150.7 97.6l.3-.1v.3v-.1a.11 .11 0 0 0-.1 .2 .1 .1 0 0 0 .1 0 .1 .1 0 0 0 .1-.1v-.6h.2v.6a.36 .36 0 0 1-.5 .4 .36 .36 0 0 1-.1-.6z"/>
<path d="M147.3 99.2h.3v.4l.1-.4h.2v.7l-.2 .3h-.3v-.3h.2l.1-.1h-.2l-.1-.1z"/>
<path d="M148.1 99.3a.36 .36 0 0 1 .6 0 .36 .36 0 0 1-.2 .6 .36 .36 0 0 1-.5-.4h.3a.1 .1 0 0 0 .1 .1 .11 .11 0 0 0 .1-.2 .11 .11 0 0 0-.2 .1h-.3z"/>
<path d="M148.9 99.2h.2l.1 .4v-.4h.3v.4a.3 .3 0 0 1-.4 .3 .3 .3 0 0 1-.2-.4z"/>
<path d="M149.7 99.2h.3l-.1 .7h-.3z"/>
<path d="M147.3 100.9h.3v.4l.1-.4h.2l.1 .4v-.4h.3l-.1 .5-.2 .2-.2-.1h-.2h-.2l-.1-.2z"/>
<path d="M148.5 100.9a.35 .35 0 0 1 .4 0 .35 .35 0 0 1 .2 .3v.3h-.3v-.3a.1 .1 0 0 0-.1-.1 .1 .1 0 0 0-.1 .1 .11 .11 0 0 0 .2 .1v.2a.35 .35 0 0 1-.4-.1 .35 .35 0 0 1 .1-.5z"/>
<path d="M149.3 100.9l.3-.1-.1 .7h-.3z"/>
<path d="M149.8 100.9l.3-.1-.2 .7h-.2z"/>
<path d="M150.2 100.9a.35 .35 0 0 1 .4 0 .35 .35 0 0 1 .2 .3v.3h-.3v-.3a.1 .1 0 0 0-.1-.1 .1 .1 0 0 0 0 .1 .1 .1 0 0 0 .1 .1v.2a.35 .35 0 0 1-.4-.1 .35 .35 0 0 1 .1-.5z"/>
<path d="M151 100.9a.3 .3 0 0 1 .4 0 .3 .3 0 0 1 .2 .3v.3h-.3v-.4l-.1 .4h-.2z"/>
<path d="M151.7 100.6h.2v.3h.1v.2h-.1l.2 .2v.2l-.4-.2z"/>
<path d="M152.2 100.9h.2l.1 .4v-.4h.3v.6l-.3 .3h-.2v-.2h.1l.1-.1h-.2l-.1-.1z"/>
<path d="M134.4 103.7h.4v.3h-.4z"/>
<path d="M134.4 103.2h.3l.1 .3h-.4z"/>
<path d="M132.2 102.9h2.9v1.4h-2.9v-1.2h.1v.8l.2 .3h.2l.2-.1 .1-.8h.3l.1 .3 .4 .3-.1 .1h-.4v.1l.2 .1 .4-.1 .1-.2-.1-.2-.4-.2-.1-.2 .1-.1h.4l.1-.1h.3v1.1h.4l.3-.3-.2-.3 .1-.3-.2-.2h-.7l-.5-.1-.2 .3h-.3l-.1-.3-.1 .9-.1 .1h-.2l-.1-.1v-.8h-.2z"/>
<path d="M138.6 88.7a.34 .34 0 0 1 .4 .3 .34 .34 0 0 1-.4 .3z"/>
<path d="M136.7 88.4h2.5v1.1h-2.5v-.6h.1l.1 .4 .2 .2 .3-.2v-.3h-.2l.1 .1v.2a.32 .32 0 0 1-.4-.4 .32 .32 0 0 1 .5-.2v-.1h.3v.9l.1-.1v-.6l.3 .6h.1v-.8h.3v.9l.4-.1 .1-.2 .1-.3-.2-.3-.7-.1-.1 .7-.4-.7-.7 .1-.2 .3h-.1z"/>
<path d="M131.7 88.4h2.3v1.1h-2.3v-.9l.6 .1-.2 .2 .2 .1v.2l-.1 .1h-.3h-.1l.2 .2h.3l.1-.2v-.3l-.1-.2 .1-.2h.2l.2 .8h.1l.3-.8 .5 .1-.2 .2 .3 .2-.1 .2h-.4v.1l.4 .1 .2-.3v-.2l-.2-.2 .2-.2v-.1l-.8 .1-.2 .6-.2-.6h-1z"/>
<path d="M140 88.7h.1h.2v.4l-.1 .2h-.2z"/>
<path d="M139.4 88.4h1.1v1.1h-1.1v-.9h.1v.9l.1-.1v-.5h.2v.4l.2 .2 .3-.1 .2-.3-.1-.4-.1-.1-.3-.1-.1 .2-.1 .2h-.2v-.3h-.2z"/>
<circle cx="140.7" cy="74.9" r=".11"/>
<circle cx="148.8" cy="97.3" r=".13"/>
</g>
<path d="M127 97.8l.1-.1a.43 .43 0 0 1 .3 .4 .43 .43 0 0 1-.3 .4l-.1-.3z" fill="none" stroke="#f2eda1" stroke-width=".13"/>
<g fill="#f2eda1">
<path d="M143.1 108.1h2.8v1.3h-2.8v-1.2l.6 .1-.2 .4 .3 .1v.2l-.1 .2-.5-.1v.1l.2 .1h.3l.2-.1 .1-.4-.3-.2 .3-.3h.1l.4 1h.1l.3-1.1 .2 .1h.4l-.2 .4 .3 .1v.3l-.4 .1-.1-.1v.2h.4l.3-.2v-.3l-.3-.2 .3-.3-.1-.1h-.9l-.3 .8-.3-.8h-1.1z"/>
<path d="M144.2 88.5h1.4v2.9h-1.4v-.6h.2v.3l.2 .2v-.1l-.1-.4 .2-.1h.1l.6 .6 .1-.1v-.7l-.1 .1v.5l-.6-.6-.3 .1-.1 .2h-.2v-.8l.9 .3 .1-.5h.3v-.1h-.3l-.1-.2-.1 .2h-.3l.1 .1h.2v.3l-.6-.2-.2 .1v-1.3l1 .3-.8 .3v.2l1.1-.4-1-.5-.3 .1z"/>
<path d="M155.4 84.5h6.3v1.5h-6.3v-.2l3.6 .1v-.1h-3.6v-.1l.2 .1h.6v-.1h-.4l.2-.3 1 .1v.3h.1v-.3l.2-.1-.2-.1v-.3h-.1v.3h-.3l.2-.5h.5l.4 1 .4-1h.9v1h.6v-.1h-.4v-.4l.3-.1h-.1h-.2v-.4h.6l.3 .5-.3 .5h.2l.2-.4 .4 .4v-.1l-.3-.4 .3-.6h.1l.1 .1h.2v1h.1l.1-1h.2v-.1h-.9l-.3 .4-.3-.4-.1 .1-.7-.1-.1 .1h-.9l-.1-.1-.3 .8-.4-.8v.1h-.5v-.1l-.1-.1-.3 .8h-.5l.2-.2 .1-.3-.3-.2h-.3l-.1 .2 .4-.1 .1 .2v.1l-.6 .6h-.1z"/>
</g>
<path d="M110.6 100.5v.4" fill="none" stroke="#f2eda1" stroke-width=".13"/>
<g fill="#f2eda1">
<path d="M110.1 99h.3v.3h-.3z"/>
<path d="M110.1 98.6l.3 .1v.1l-.3 .1z"/>
<path d="M109.9 98.4h3.2v1.1h-3.2v-.9h.1v.8h.4l.2-.2-.1-.6h.3v.6l.2 .2 .3-.1 .1-.4h.2l.1 .3 .1 .2h.2l.2-.1a.35 .35 0 0 1-.5-.2 .35 .35 0 0 1 .3-.5l.2 .1v-.1h.2l.1 .8h.1v-.4l.3 .4h.1l-.3-.5 .3-.3v-.1l-.4 .4-.1-.4h-.6l-.2 .1-.1 .3h-.2v-.4h-.1v.7l-.3 .1-.1-.1v-.7l-1 .1z"/>
</g>
<path d="M161.7 95h.6" fill="none" stroke="#f2eda1" stroke-width=".15"/>
<g fill="#f2eda1">
<path d="M129.9 88.6a.34 .34 0 0 1 .4 .4 .34 .34 0 0 1-.4 .3z"/>
<path d="M128 88.4h2.5v1.1h-2.5v-.8h.1l.1 .3 .4 .2-.1 .1h-.3l-.1 .1h.4l.1-.1 .1-.2-.5-.4 .1-.1 .3 .1 .1-.1h.1l.3 .8 .1-.4 .1 .4h.1l.2-.8h.2l.1 .8h.3l.2-.4-.1-.3-.2-.2h-.5l-.2 .6-.2-.3-.1 .3-.2-.6h-.6l-.3 .2z"/>
<path d="M137.4 83.4h2v1h-2v-.2l.6 .1v-.1h-.3l.1-.2h.7l.1 .3v-.3h.1l-.1-.3h-.1v.2h-.2l.1-.4h.4l.2 .7 .1 .1 .3-.8h-.2l-.1 .5-.3-.5-.4-.1-.2 .6h-.4l.2-.4-.1-.1h-.3l-.1 .1h.3l.1 .1-.5 .5z"/>
<path d="M118.1 105.1h.2l.1 .3h-.4z"/>
<path d="M118.5 105h.3l.1 .4h-.4z"/>
<path d="M117.8 104.7h1.4v5.6h-1.4v-.7h.1v.5l.6 .1-.1-.5 .1-.1h.2l.2 .1-.1 .5 .2-.2v-.3l-.2-.2h-.3l-.2 .1v.4h-.3v-.5l-.2 .1v-1l.9 .3-.8 .3v.1l1.1-.4-1-.4-.2 .1v-.9h1.2v.8h.1v-.8h-1.3v-.8l.2 .1h.7l.2 .1v.2l-.2 .1h-.8v.1h.9l.2-.2v-.3l-.2-.2-1 .1v-.9h.1v.3l.2 .2 .3-.1 .3-.4 .2 .1v.4l.1-.2v-.3l-.3-.2-.2 .2-.2 .4h-.2v-.5l-.1-.1-.1 .2h-.1v-.9h.1v.4l1.1 .1v-.5l-.1-.2-.3-.1-.2 .2-.3-.1-.2 .2h-.1z"/>
<path d="M135.9 76.1l.3 .1v.2h-.3z"/>
<path d="M135.7 75.9h2.7v1.1h-2.7v-.9h.1v.8h.1v-.4l.4-.1v-.2l-.1-.1h.4v.8h.1v-.4h.2v-.1h-.2v-.3h.4h.1v.8h.5v-.1h-.3v-.8l.6 .1v.8h.1v-.8h.3l-.1-.1-2.6 .1z"/>
<path d="M122.6 76.3h.3l.1 .3-.4 .1z"/>
<path d="M122.6 75.8l.3 .1v.2l-.3 .1z"/>
<path d="M123.6 75.9h.3a.57 .57 0 0 1 0 .8l-.3-.1a.65 .65 0 0 1 0-.7z"/>
<path d="M124.6 75.9l.2-.1 .2 .1a.57 .57 0 0 1-.1 .8l-.2-.1a.7 .7 0 0 1-.1-.7z"/>
<path d="M122.3 75.6h3.9v1.3h-3.9v-1.1h.1v1h.1h.4l.2-.1 .1-.3-.2-.2 .1-.1h.3v.5l.3 .2h.2l.2-.1 .1-.6h.2l.1 .6 .2 .1h.3l.2-.1 .1-.3-.1-.5-.1-.2 .6 .1v1h.1v-1h.3l-.1-.1h-1.3l-.2 .2-.1 .2h-.2l-.2-.4h-.3l-.3 .2v.2h-.3l-.1-.4h-.5l-.2 .1z"/>
<path d="M112.1 83.4a.42 .42 0 0 1 .4 .5 .42 .42 0 0 1-.4 .4z"/>
<path d="M109.7 83.2h3.1v1.3h-3.1v-.7h.1l.2 .5 .2 .1 .4-.1v-.4h-.3l.2 .1-.1 .2a.41 .41 0 0 1-.4-.4 .41 .41 0 0 1 .5-.4h.4v1h.1v-.8l.5 .8h.1v-1h.3l.1 1h.4l.2-.3 .1-.3-.3-.5h-.9v.8l-.5-.8-.1 .1-.8-.1-.3 .5h-.1z"/>
<path d="M159.7 87.8h.4v.3l-.4 .1z"/>
<path d="M159.4 87.5h2.8v1.4h-2.8v-1.2h.2v1.1l.1-.1v-.4h.1l.4 .5h.1l-.3-.5 .2-.1 .1-.3h.2l.1 .3 .5 .2-.2 .2h-.3l-.1 .1 .2 .1 .4-.1 .1-.2v-.2l-.5-.2v-.2l.1-.1h.4v-.1l.5 .1v.9l.1 .1v-1l.3-.1-.1-.1h-1.2l-.3 .3h-.2l-.3-.3-.6 .1z"/>
<path d="M110.8 86.1h.3v.3h-.3z"/>
<path d="M111.3 86h.3v.4h-.3z"/>
<path d="M110.5 84.7h1.5v4.6h-1.5v-.7h.1l.1 .5 .5 .1v-.5l.1-.1h.2l.1 .1v.5l.2-.2v-.3l-.3-.2h-.2l-.2 .1-.1 .4h-.2l-.1-.5-.2 .1v-1l1 .3-.8 .3v.1l1.1-.4-1.1-.4-.2 .1v-.9h1.2v.8h.1h.1l-.1-.8h-1.3v-.6h.1l.1 .4 1 .1 .1-.1v-.4l-.3-.3-.3 .2-.3-.1-.3 .2h-.1v-1.2h.1l.5 .5h-.4v.1l1 .1v-.2l-.5-.1 .6-.4-.1-.1-.6 .4-.4-.4-.2 .1z"/>
<path d="M141.8 94.9h1.3v2.8h-1.3v-.8h.1v.7l.1-.1v-.5l.4 .3 .1-.3 .2-.1 .2 .2-.1 .4 .1 .1 .1-.3v-.3l-.2-.2h-.3l-.2 .2-.3-.2-.2 .1v-1l.9 .4-.8 .2v.2l1.1-.4-1-.5-.2 .1v-.8h.1v.7l.1-.1v-.5l.4 .3 .1-.4 .3 .1 .1 .3-.1 .2h.1l.1-.1v-.5l-.2-.1h-.3l-.2 .2-.3-.2-.2 .1z"/>
<path d="M158 103.3h3.6v1.3h-3.6v-.7h.2v.3l.2 .3h.4l.1-.1-.1-.1a.29 .29 0 0 1-.5-.1 .37 .37 0 0 1 0-.5 .37 .37 0 0 1 .5-.1h.1v-.1h.3v1h.1v-.5l.4-.1h-.1h-.3v-.4h.8v1h.5h.1l-.1-.1h-.4v-1l.8 .1v1h.1l.1-1h.2v-.1h-2.1l-.4 .1-.3-.1h-.2l-.2 .5h-.2z"/>
<path d="M144.9 83.9l.3 .1v.2h-.3z"/>
<path d="M144 83.7h2.3v1.1h-2.3v-1l.3 .1v.8h.1v-.8h.2h.2v.8h.1v-.4h.1l.3 .4-.2-.4 .3-.1-.1-.3h.3v.8h.1v-.6l.2 .4 .2-.4v.6h.1v-.9l-.3 .5-.2-.5h-1.7z"/>
</g>
<g fill="none" stroke="#f2eda1" stroke-width=".13">
<path d="M126.5 77v.5M127.5 77v.5M112.8 93.3v.6M114.2 93.3v.6M119.8 83.1v-2.5h1.4v2.5M120.3 99v.5M121.7 99v.5M142.5 89.5v2.4h1.5v-2.4M150.1 84.3v.2M151.1 84.3v.2M157.8 82.8h1.4v1.4h-1.4zM111 102.3v-2.5h1.5v2.5"/>
<path d="M143.8 109.8h1.4v1.4h-1.4zM156.5 100.8v.5M157.5 100.8v.5"/>
</g>
<path d="M120.5 90h.3l.2 .1v-.1h.4h-.7l.6-.2h.1l.1 .2v-.1l.1 .1-.1-.1-.2-.1h.1l-.7 .1 .7-.2h-.3l-.4 .2a.85 .85 0 0 1 .9-.3l.8-.3h-.1h.2l.1 .1 .1-.2-.1-.1h-.1l-.1 .2h-.1l.2-.3 .3 .2-.2 .3-.2-.1-.9 .3 .2 .5a.23 .23 0 0 1 .2 .1 .23 .23 0 0 1 0 .2l-.3 1.8-.3 .1a.39 .39 0 0 1-.5 0l-.5-.2 .9 .3 .1-.2a.19 .19 0 0 0 .3 0 .19 .19 0 0 0 0-.3v-.2h-.2l-.1 .5 .1-.5h-.1a.26 .26 0 0 0-.3 .1 .26 .26 0 0 0-.1 .3l-.1 .2 .1-.3a.14 .14 0 0 0 0-.2 .14 .14 0 0 0-.2-.1h.9l.1-.2h-.2l-.1 .2v-.2h-.3a.12 .12 0 0 0-.1 .1 .12 .12 0 0 0-.1 .1l-.4-.1-.1 .5-.3-.1h.2l.1-.4 .3 .1a.15 .15 0 0 0 .2 0 .15 .15 0 0 0 0-.2h-.1h.7a.38 .38 0 0 0 .2-.5 .39 .39 0 0 0-.2 .5v-.5h-.3a.28 .28 0 0 0-.2 .4l-.2 .1-.3-.1v.2l-.3-.1-.1 .4 .1-.4 .2 .1v-.2h.1l.4 .1 .1-.5h-.1l.8-.1 .1-.1h-.2v.2v-.2h-.5v.2l-.5-.1v.1a.22 .22 0 0 1 0 .2 .22 .22 0 0 1-.2 .1h-.2v.2v-.3l.3 .2 .1-.5h-.1l.4 .1a.11 .11 0 0 0 .2-.1 .11 .11 0 0 0-.2-.1l.9-.1 .1-.5-.2 .1-.1 .5v-.4l-.4-.1-.1 .5-.5-.1v.2l-.3-.1-.1 .4 .1-.5 .3 .2-.1-.2h.3a.19 .19 0 0 0 .3 .1 .19 .19 0 0 0 0-.3l.1-.2h-.3a.16 .16 0 0 0-.2-.1 .16 .16 0 0 0 0 .3l-.1 .2-.1-.1a.1 .1 0 0 0-.1 0 .1 .1 0 0 0-.1 .1 .13 .13 0 0 1 .1-.1 .13 .13 0 0 1 .2 0l.1-.4 .7 .1h.2l-.1-.1v.1h-.1v-.1l-.2 .1v-.1l-.2-.1-.1 .1v-.1l-.2 .1v-.1l1.2 .1-.6-.2-.1 .1h-.1l.6-.1-.1-.1-.1 .1h-.4l-.1 .1-.5-.1-.2 .5 .2-.5h.1a.15 .15 0 0 0 .2 .1 .15 .15 0 0 0 .1-.1h.5v-.1h.1h-.7l-.1 .1h-.1l.1-.1z" fill="#f2eda1"/>
<circle cx="128.3" cy="99" r=".12" fill="none" stroke="#f2eda1" stroke-width=".25"/>
<g fill="none" stroke="#f2eda1" stroke-width=".13">
<path d="M124 77.7h.5M124 78.8h.5M139.3 78.8h.6M124.9 99.5h3.8v1.3M130.4 91.8v2.1h2.1M130.7 89.9h11.1v3.7h-2.8v2.9h-5.5v-2.9h-2.8zM135.8 82.6v1.4h1.4v-1.4M136 99.8h.5M139.5 81h.2M139.5 82h.2M140 86v.5M141.5 86v.5"/>
<path d="M142.8 99.7v.5M144.3 99.7v.5M147 95h-.4v.5M151.8 84.1v.6M153.3 84.1v.6M153.8 95v.5M155.8 93.2v.3M158.2 94.4v.2M116 104.8v1.4h1.4v-1.4M128.7 105.1v1.2h-3.8M146.6 101.8v.4h.4M147.9 108.8h.3"/>
<path d="M147.9 109.8h.3M151.4 108.8h.3M151.4 109.8h.3M153.8 101.8v.4h-.5M158.2 100.8v.5M159.3 100.8v.5"/>
</g>
<g fill="#f2eda1" stroke="#f2eda1" stroke-width=".13">
<path d="M146.5 102.5l.5 .3-.5 .4z"/>
<path d="M123.4 99.3h.5l-.3 .3z"/>
</g>
<path d="M146.8 90.3h3v.7h-3zM149.9 88.8v1.1" fill="none" stroke="#f2eda1" stroke-width=".2"/>
<path d="M113 81.3a.51 .51 0 0 1 .8 .1 .53 .53 0 0 1 .8-.1 .53 .53 0 0 1 0 .8l-.7 .7a.18 .18 0 0 1-.2 .1 .18 .18 0 0 1-.1-.2 1.12 1.12 0 0 1-.7-1.3z" fill="#f2eda1"/>
<path d="M136 79.8v-2.5h1.5v2.5M115.9 98h.2M115.9 99.1h.2" fill="none" stroke="#f2eda1" stroke-width=".13"/>
<g fill="#f2eda1">
<path d="M121.5 86.4h.2v.3l-.2-.1 .1 .1 .1-.2-.3 .1z"/>
<path d="M120.9 86l.2 .1 .2 .3-.1 .2-.1-.1 .1 .1 .1-.2-.2 .1-.1-.1h.2l-.2-.1-.1-.3 .1 .2 .1-.1z"/>
<path d="M121.4 85.7h.2l.2 .2 .1 .3-.1 .1-.2-.1 .2 .1v-.1h-.2v-.1l-.2-.3 .2 .2 .1-.1-.2-.2-.1 .1z"/>
<path d="M120.4 85.7l.4-.3 .4-.1 .5 .1 .3-.2 .4 .2 .3 1-.1 .5-.4 .9-.5 .4-.3 .1-.3-.2h.3h-.3h.4h-.4h.4h-.4h.5h-.5h.4l-.5-.1 .9 .1h-.3l.2-.1h-.8h.6h-.6h.6l-.6-.1h.7h-.7h.6h-.6h.7h-.7v-.1l-.2-.1h-.4l-.4-.1-.1-.1h.4h-.4l.2-.1h-.2v-.6h.1v.3l.2 .1h.2l.3-.1-.3 .2 .6 .4 .4 .1 .5-.2 .4-.3 .3-.6h.1h-.1l-.1-.6-.2-.3-.4-.3-.3-.1 .3 .1 .5 .4v-.4l-.3-.2-.3 .1h-.6l-.4 .1-.4 .5-.2 .4 .2-.1-.3 .2-.1 .3h-.1z"/>
</g>
<g fill="none" stroke="#f2eda1" stroke-width=".2">
<path d="M130.2 80.5h3.1v4.9h-3.1zM133.7 85.5h1.5M147.8 84.1h1.5M150.7 91.4v1.1M150.8 90.3h3v.7h-3z"/>
<circle cx="121" cy="74.5" r=".1"/>
</g>
<g fill="none" stroke="#f2eda1" stroke-width=".13">
<path d="M116.7 75.7h-.1v2.5h1.8M118.3 75.7h1.9M121.8 75.7h.2v2.5h-1.9M128.5 76.1v3.9h2v-3.9M131.5 78v.5M132.5 78v.5M134 78.1v.3M135 78.1v.3M139.3 79.4h.6M151.1 78.3h.6M151.1 79.3h.6M151.2 80h.5"/>
<path d="M153.9 80v3.3M155.6 80v3.3M110.5 93.3v.6M110.5 89.8h1.5v1.4h-1.5zM112 93.3v.6M112.8 87.5v.6M113.1 83.2h1.3v1.4h-1.3zM114.1 99.8h3M114.2 87.5v.6M115.1 87.7v-3.1h12.3v3.1M115.1 93.8v3.1h10.1M115.3 83.1v-2.5h1.4v2.5"/>
<path d="M117.5 83.1v-2.5h1.5v2.5M118.5 99.4v.2M119.5 99.4v.2M122 83.1v-2.5h1.5v2.5M126.5 80.6v.3M127.4 93.8v3.1h-1.6M127.5 80.6v.3M130.7 88h.2M133.2 99.9v.5M134.3 99.9v.5M136 85.8v.3M137 85.8v.3"/>
<path d="M137.8 86v.5M139.2 86v.5M139.3 80.4h.6M140 97.1v-2.5h1.5v2.5M140.2 99.7v.6M141.3 99.7v.6M142.2 85.9v.2M143.3 85.9v.2M144.1 86.3v1.3h1.4M145.8 93.1v.3M146.7 84.9h2.7v2.7h-2.7zM151.2 81h.5"/>
<path d="M156.5 94.2v.6M157.1 90.4v.7M157.5 94.2v.6M157.8 92.4h2.9M157.8 89.2h2.9M161.3 90.4v.7M111.7 103.7h.6M111.7 104.8h.6M114.1 103h3M119.6 101.7h.2M119.6 102.8h.2M120.3 106v.5"/>
<path d="M121.7 106v.5M128 109.5h.5M128 111h.5M130.5 106.8h-4.1v2h4.1M132.7 107.3v1.7M137.3 103.5h1.3M137.3 100.4h1.3M142 107.3v1.7M144.8 103.7v.3M145.8 103.7v.3M152.4 104.5h-6v3.7h6M155.2 103.3h2.4v1.4h-2.4"/>
</g>
<g fill="#f2eda1" stroke="#f2eda1" stroke-width=".13">
<path d="M125.5 96.9l.2 .3h-.4z"/>
<path d="M113 100.1l.5-.5v.5z"/>
<path d="M136.7 100.1h.5l-.3 .4z"/>
</g>
<path d="M110.3 75.3a3.5 3.5 0 0 1 2.5-1h46.5a3.5 3.5 0 0 1 3.5 3.5l-.1 30.7a3.5 3.5 0 0 1-3.4 3.5h-46.5a3.5 3.5 0 0 1-3.5-3.5l-.1-30.8a3.5 3.5 0 0 1 1.1-2.4z" fill="none" stroke="#d0d2cd" stroke-width=".13"/>
<g fill="#fff" stroke="#fff" stroke-width=".13">
<circle cx="153.2" cy="90.5" r=".1"/>
<circle cx="153.3" cy="97.5" r=".1"/>
<circle cx="154" cy="91" r=".1"/>
<circle cx="151.5" cy="90.4" r=".1"/>
<circle cx="151.5" cy="91" r=".1"/>
<circle cx="123.3" cy="107.7" r=".15"/>
<circle cx="129.6" cy="96.7" r=".1"/>
<circle cx="161.7" cy="99.5" r=".15"/>
<circle cx="117" cy="110" r=".15"/>
<circle cx="155" cy="111" r=".15"/>
<circle cx="110.3" cy="82" r=".15"/>
<circle cx="115" cy="103.2" r=".15"/>
<circle cx="112.7" cy="99" r=".1"/>
<circle cx="132" cy="82.5" r=".15"/>
<circle cx="147.3" cy="88" r=".1"/>
<circle cx="144" cy="92.6" r=".15"/>
<circle cx="160.7" cy="86" r=".15"/>
<circle cx="161.7" cy="101" r=".15"/>
<circle cx="127.5" cy="102.7" r=".15"/>
<circle cx="122.3" cy="96.3" r=".15"/>
<circle cx="161" cy="100.2" r=".15"/>
<circle cx="125.9" cy="103.5" r=".15"/>
<circle cx="161" cy="101.7" r=".15"/>
<circle cx="126.4" cy="102.7" r=".15"/>
<circle cx="121" cy="96.3" r=".15"/>
<circle cx="142.1" cy="97.9" r=".15"/>
<circle cx="130.3" cy="96.7" r=".1"/>
<circle cx="155" cy="76.2" r=".15"/>
<circle cx="136" cy="100.5" r=".1"/>
<circle cx="110.5" cy="89.2" r=".15"/>
<circle cx="146.5" cy="103.4" r=".15"/>
<circle cx="124" cy="76.8" r=".15"/>
<circle cx="130.3" cy="95.9" r=".1"/>
<circle cx="131.1" cy="97.5" r=".1"/>
<circle cx="116.1" cy="103.2" r=".15"/>
<circle cx="127" cy="103.5" r=".15"/>
<circle cx="155" cy="107" r=".15"/>
<circle cx="137.1" cy="97.2" r=".1"/>
<circle cx="110.7" cy="97" r=".15"/>
<circle cx="117" cy="107.7" r=".15"/>
<circle cx="137.3" cy="79" r=".1"/>
<circle cx="135.5" cy="101.2" r=".1"/>
<circle cx="119.7" cy="96.3" r=".15"/>
<circle cx="111.5" cy="88.5" r=".15"/>
<circle cx="130.7" cy="82.5" r=".15"/>
<circle cx="160.2" cy="101" r=".15"/>
<circle cx="161" cy="98.7" r=".15"/>
<circle cx="138.1" cy="109.9" r=".1"/>
<circle cx="136.3" cy="79" r=".1"/>
<circle cx="129.6" cy="97.5" r=".1"/>
<circle cx="112.3" cy="82" r=".15"/>
<circle cx="140.8" cy="76.2" r=".15"/>
<circle cx="125.3" cy="76.8" r=".15"/>
<circle cx="132.5" cy="83.5" r=".15"/>
<circle cx="131.1" cy="96.7" r=".1"/>
<circle cx="131.1" cy="95.9" r=".1"/>
<circle cx="161.7" cy="86.5" r=".15"/>
<circle cx="130.3" cy="97.5" r=".1"/>
<circle cx="124.5" cy="75.8" r=".15"/>
<circle cx="123.3" cy="75.8" r=".15"/>
<circle cx="152.4" cy="93.2" r=".1"/>
<circle cx="135" cy="100.5" r=".1"/>
<circle cx="160.7" cy="87" r=".15"/>
<circle cx="155" cy="109" r=".15"/>
<circle cx="155" cy="78.2" r=".15"/>
<circle cx="131.3" cy="83.5" r=".15"/>
<circle cx="129.6" cy="95.9" r=".1"/>
<circle cx="161.7" cy="87.5" r=".15"/>
<circle cx="110.5" cy="88" r=".15"/>
<circle cx="111.5" cy="87.2" r=".15"/>
<circle cx="121.5" cy="103.5" r=".15"/>
<circle cx="132.1" cy="98.8" r=".1"/>
<circle cx="155" cy="108" r=".15"/>
<circle cx="122.3" cy="105.7" r=".15"/>
<circle cx="155" cy="77.2" r=".15"/>
<circle cx="134.5" cy="75" r=".15"/>
<circle cx="117" cy="108.8" r=".15"/>
<circle cx="155" cy="110" r=".15"/>
<circle cx="146" cy="102" r=".15"/>
<circle cx="119.5" cy="75.8" r=".1"/>
<circle cx="144.5" cy="110.5" r=".1"/>
<circle cx="111.3" cy="82" r=".15"/>
<circle cx="142" cy="102.5" r=".15"/>
<circle cx="159.3" cy="103.2" r=".1"/>
<circle cx="132.5" cy="98.4" r=".1"/>
<circle cx="155.5" cy="95.2" r=".15"/>
<circle cx="149.9" cy="93.1" r=".1"/>
<circle cx="110.3" cy="81" r=".15"/>
<circle cx="154" cy="76.2" r=".15"/>
<circle cx="124.3" cy="106.5" r=".15"/>
<circle cx="128" cy="103.5" r=".15"/>
<circle cx="139.1" cy="76.2" r=".15"/>
<circle cx="122.3" cy="104.7" r=".15"/>
<circle cx="143.5" cy="102.5" r=".15"/>
<circle cx="123" cy="106.5" r=".15"/>
<circle cx="133.3" cy="75" r=".15"/>
<circle cx="149" cy="91" r=".1"/>
<circle cx="117" cy="111.1" r=".15"/>
<circle cx="147.5" cy="88.5" r=".1"/>
<circle cx="147" cy="90.5" r=".1"/>
<circle cx="159.7" cy="89.8" r=".1"/>
<circle cx="150" cy="91.8" r=".1"/>
<circle cx="159.7" cy="90.5" r=".1"/>
<circle cx="159.7" cy="91.2" r=".1"/>
<circle cx="153.3" cy="99" r=".1"/>
<circle cx="149.2" cy="90.5" r=".1"/>
<circle cx="159.7" cy="92" r=".1"/>
<circle cx="148.7" cy="93" r=".1"/>
<circle cx="137.4" cy="104.1" r=".1"/>
<circle cx="138.2" cy="103.4" r=".1"/>
<circle cx="127.3" cy="109" r=".15"/>
<circle cx="138.5" cy="102" r=".15"/>
<circle cx="159.3" cy="96.2" r=".1"/>
<circle cx="151.6" cy="98.3" r=".1"/>
<circle cx="159.7" cy="93" r=".1"/>
<circle cx="149.2" cy="84.4" r=".1"/>
<circle cx="152.2" cy="101.7" r=".1"/>
<circle cx="159" cy="87" r=".15"/>
<circle cx="157" cy="87" r=".15"/>
<circle cx="155.7" cy="88" r=".15"/>
<circle cx="159" cy="89" r=".15"/>
<circle cx="155.7" cy="87" r=".15"/>
<circle cx="151.5" cy="83.5" r=".1"/>
<circle cx="159.7" cy="93.6" r=".1"/>
<circle cx="155.7" cy="100.4" r=".1"/>
<circle cx="150.7" cy="101.5" r=".1"/>
<circle cx="151.7" cy="101.5" r=".1"/>
<circle cx="153" cy="101.5" r=".1"/>
<circle cx="158.6" cy="97.2" r=".1"/>
<circle cx="151.3" cy="100" r=".1"/>
<circle cx="155.6" cy="101" r=".1"/>
<circle cx="137.9" cy="77.8" r=".1"/>
<circle cx="141.5" cy="81.8" r=".1"/>
<circle cx="139.8" cy="85.2" r=".1"/>
<circle cx="157.9" cy="100.2" r=".1"/>
<circle cx="148.8" cy="101.6" r=".1"/>
<circle cx="119.2" cy="87.2" r=".1"/>
<circle cx="142" cy="94.8" r=".1"/>
<circle cx="118.2" cy="84.2" r=".1"/>
<circle cx="113" cy="103.5" r=".1"/>
<circle cx="118" cy="101" r=".1"/>
<circle cx="116" cy="84.2" r=".1"/>
<circle cx="117.2" cy="87.5" r=".1"/>
<circle cx="153.3" cy="96.9" r=".1"/>
<circle cx="149.7" cy="81.2" r=".1"/>
<circle cx="151.4" cy="81.2" r=".1"/>
<circle cx="136.2" cy="104.2" r=".1"/>
<circle cx="138.7" cy="104.5" r=".1"/>
<circle cx="120.5" cy="84.2" r=".1"/>
<circle cx="121.5" cy="87" r=".1"/>
<circle cx="122.7" cy="84.2" r=".1"/>
<circle cx="138.8" cy="90.3" r=".1"/>
<circle cx="122.4" cy="88.2" r=".1"/>
<circle cx="153.2" cy="99.8" r=".1"/>
<circle cx="142" cy="100" r=".1"/>
<circle cx="142.1" cy="93.5" r=".1"/>
<circle cx="125.9" cy="77.5" r=".1"/>
<circle cx="149.6" cy="80.3" r=".1"/>
<circle cx="152" cy="79.6" r=".1"/>
<circle cx="149.6" cy="79.6" r=".1"/>
<circle cx="153.5" cy="81" r=".1"/>
<circle cx="142" cy="89.2" r=".1"/>
<circle cx="139.5" cy="80.2" r=".1"/>
<circle cx="141.6" cy="80.1" r=".1"/>
<circle cx="150.5" cy="103.8" r=".1"/>
<circle cx="153.7" cy="102.8" r=".1"/>
<circle cx="141.5" cy="79.4" r=".1"/>
<circle cx="138.3" cy="77.5" r=".1"/>
<circle cx="131" cy="78.8" r=".1"/>
<circle cx="153" cy="98" r=".1"/>
<circle cx="142.1" cy="90" r=".1"/>
<circle cx="142.9" cy="94.6" r=".1"/>
<circle cx="149.1" cy="97.9" r=".1"/>
<circle cx="133" cy="94.2" r=".1"/>
<circle cx="133.5" cy="94.8" r=".1"/>
<circle cx="150" cy="96.2" r=".1"/>
<circle cx="148.7" cy="99.5" r=".1"/>
<circle cx="148.5" cy="95.5" r=".1"/>
<circle cx="143.4" cy="94.4" r=".1"/>
<circle cx="149.3" cy="99.5" r=".1"/>
<circle cx="148.5" cy="96.8" r=".1"/>
<circle cx="125.3" cy="82" r=".15"/>
<circle cx="130.5" cy="86.5" r=".15"/>
<circle cx="129.5" cy="86.5" r=".15"/>
<circle cx="135.3" cy="85.8" r=".1"/>
<circle cx="139.2" cy="80.7" r=".1"/>
<circle cx="141.6" cy="80.7" r=".1"/>
<circle cx="135.1" cy="96.3" r=".1"/>
<circle cx="113.2" cy="102.4" r=".1"/>
<circle cx="114.5" cy="99.7" r=".1"/>
<circle cx="136.2" cy="93.1" r=".65"/>
<circle cx="132.5" cy="91.7" r=".6"/>
<circle cx="135" cy="91.7" r=".6"/>
<circle cx="137.5" cy="91.7" r=".6"/>
<circle cx="140" cy="91.7" r=".6"/>
<circle cx="159.2" cy="108.5" r="1.6"/>
<circle cx="112.7" cy="108.5" r="1.6"/>
<circle cx="112.7" cy="77.8" r="1.6"/>
<circle cx="134.5" cy="106.5" r=".32"/>
<circle cx="140.2" cy="106.5" r=".32"/>
<circle cx="159.2" cy="77.8" r="1.6"/>
<circle cx="145.5" cy="86.2" r=".5"/>
<circle cx="148" cy="86.2" r=".5"/>
<circle cx="157.9" cy="88.1" r=".42"/>
<circle cx="157.9" cy="98.7" r=".42"/>
</g>
<path d="M133 105.4v1.1M133 109.8v.8M141.7 105.4v1.1M141.7 109.8v.8" fill="none" stroke="#fff" stroke-width=".6"/>
<use href="#words"/>
</svg>
